VERSION 5.8 ;
BUSBITCHARS "[]" ;
DIVIDERCHAR "/" ;
UNITS
    DATABASE MICRONS 1000 ;
END UNITS

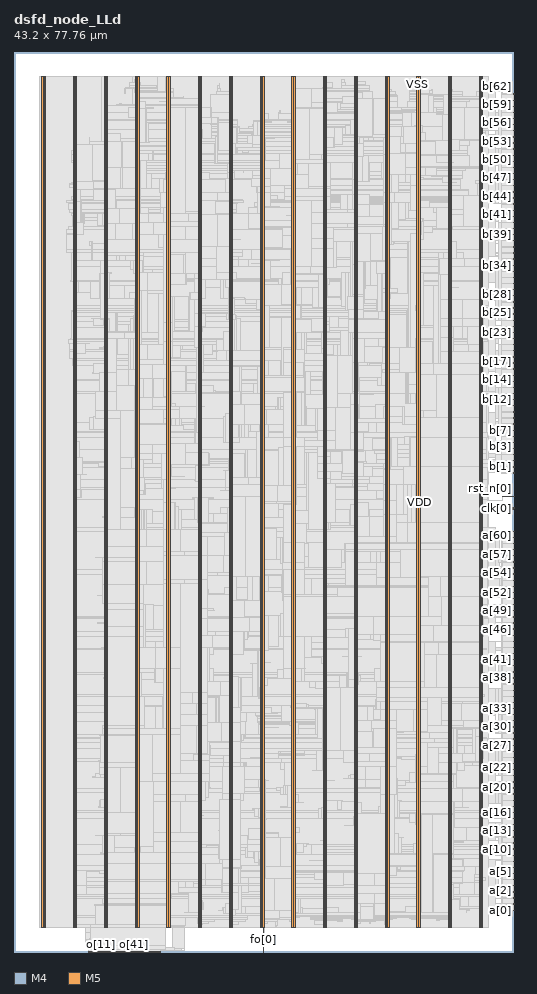
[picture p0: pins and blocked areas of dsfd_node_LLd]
MACRO dsfd_node_LLd
  FOREIGN dsfd_node_LLd 0 0 ;
  CLASS BLOCK ;
  SIZE 43.2 BY 77.76 ;
  PIN a[0]
    DIRECTION INPUT ;
    USE SIGNAL ;
    PORT
      LAYER M4 ;
        RECT  43.116 3.6 43.2 3.624 ;
    END
  END a[0]
  PIN a[10]
    DIRECTION INPUT ;
    USE SIGNAL ;
    PORT
      LAYER M4 ;
        RECT  43.116 8.88 43.2 8.904 ;
    END
  END a[10]
  PIN a[11]
    DIRECTION INPUT ;
    USE SIGNAL ;
    PORT
      LAYER M4 ;
        RECT  43.116 9.408 43.2 9.432 ;
    END
  END a[11]
  PIN a[12]
    DIRECTION INPUT ;
    USE SIGNAL ;
    PORT
      LAYER M4 ;
        RECT  43.116 9.936 43.2 9.96 ;
    END
  END a[12]
  PIN a[13]
    DIRECTION INPUT ;
    USE SIGNAL ;
    PORT
      LAYER M4 ;
        RECT  43.116 10.464 43.2 10.488 ;
    END
  END a[13]
  PIN a[14]
    DIRECTION INPUT ;
    USE SIGNAL ;
    PORT
      LAYER M4 ;
        RECT  43.116 10.992 43.2 11.016 ;
    END
  END a[14]
  PIN a[15]
    DIRECTION INPUT ;
    USE SIGNAL ;
    PORT
      LAYER M4 ;
        RECT  43.116 11.52 43.2 11.544 ;
    END
  END a[15]
  PIN a[16]
    DIRECTION INPUT ;
    USE SIGNAL ;
    PORT
      LAYER M4 ;
        RECT  43.116 12.048 43.2 12.072 ;
    END
  END a[16]
  PIN a[17]
    DIRECTION INPUT ;
    USE SIGNAL ;
    PORT
      LAYER M4 ;
        RECT  43.116 12.576 43.2 12.6 ;
    END
  END a[17]
  PIN a[18]
    DIRECTION INPUT ;
    USE SIGNAL ;
    PORT
      LAYER M4 ;
        RECT  43.116 13.104 43.2 13.128 ;
    END
  END a[18]
  PIN a[19]
    DIRECTION INPUT ;
    USE SIGNAL ;
    PORT
      LAYER M4 ;
        RECT  43.116 13.632 43.2 13.656 ;
    END
  END a[19]
  PIN a[1]
    DIRECTION INPUT ;
    USE SIGNAL ;
    PORT
      LAYER M4 ;
        RECT  43.116 4.128 43.2 4.152 ;
    END
  END a[1]
  PIN a[20]
    DIRECTION INPUT ;
    USE SIGNAL ;
    PORT
      LAYER M4 ;
        RECT  43.116 14.16 43.2 14.184 ;
    END
  END a[20]
  PIN a[21]
    DIRECTION INPUT ;
    USE SIGNAL ;
    PORT
      LAYER M4 ;
        RECT  43.116 14.688 43.2 14.712 ;
    END
  END a[21]
  PIN a[22]
    DIRECTION INPUT ;
    USE SIGNAL ;
    PORT
      LAYER M4 ;
        RECT  43.116 15.216 43.2 15.24 ;
    END
  END a[22]
  PIN a[23]
    DIRECTION INPUT ;
    USE SIGNAL ;
    PORT
      LAYER M4 ;
        RECT  43.116 15.744 43.2 15.768 ;
    END
  END a[23]
  PIN a[24]
    DIRECTION INPUT ;
    USE SIGNAL ;
    PORT
      LAYER M4 ;
        RECT  43.116 16.272 43.2 16.296 ;
    END
  END a[24]
  PIN a[25]
    DIRECTION INPUT ;
    USE SIGNAL ;
    PORT
      LAYER M4 ;
        RECT  43.116 16.8 43.2 16.824 ;
    END
  END a[25]
  PIN a[26]
    DIRECTION INPUT ;
    USE SIGNAL ;
    PORT
      LAYER M4 ;
        RECT  43.116 17.328 43.2 17.352 ;
    END
  END a[26]
  PIN a[27]
    DIRECTION INPUT ;
    USE SIGNAL ;
    PORT
      LAYER M4 ;
        RECT  43.116 17.856 43.2 17.88 ;
    END
  END a[27]
  PIN a[28]
    DIRECTION INPUT ;
    USE SIGNAL ;
    PORT
      LAYER M4 ;
        RECT  43.116 18.384 43.2 18.408 ;
    END
  END a[28]
  PIN a[29]
    DIRECTION INPUT ;
    USE SIGNAL ;
    PORT
      LAYER M4 ;
        RECT  43.116 18.912 43.2 18.936 ;
    END
  END a[29]
  PIN a[2]
    DIRECTION INPUT ;
    USE SIGNAL ;
    PORT
      LAYER M4 ;
        RECT  43.116 4.656 43.2 4.68 ;
    END
  END a[2]
  PIN a[30]
    DIRECTION INPUT ;
    USE SIGNAL ;
    PORT
      LAYER M4 ;
        RECT  43.116 19.44 43.2 19.464 ;
    END
  END a[30]
  PIN a[31]
    DIRECTION INPUT ;
    USE SIGNAL ;
    PORT
      LAYER M4 ;
        RECT  43.116 19.968 43.2 19.992 ;
    END
  END a[31]
  PIN a[32]
    DIRECTION INPUT ;
    USE SIGNAL ;
    PORT
      LAYER M4 ;
        RECT  43.116 20.496 43.2 20.52 ;
    END
  END a[32]
  PIN a[33]
    DIRECTION INPUT ;
    USE SIGNAL ;
    PORT
      LAYER M4 ;
        RECT  43.116 21.024 43.2 21.048 ;
    END
  END a[33]
  PIN a[34]
    DIRECTION INPUT ;
    USE SIGNAL ;
    PORT
      LAYER M4 ;
        RECT  43.116 21.552 43.2 21.576 ;
    END
  END a[34]
  PIN a[35]
    DIRECTION INPUT ;
    USE SIGNAL ;
    PORT
      LAYER M4 ;
        RECT  43.116 22.08 43.2 22.104 ;
    END
  END a[35]
  PIN a[36]
    DIRECTION INPUT ;
    USE SIGNAL ;
    PORT
      LAYER M4 ;
        RECT  43.116 22.608 43.2 22.632 ;
    END
  END a[36]
  PIN a[37]
    DIRECTION INPUT ;
    USE SIGNAL ;
    PORT
      LAYER M4 ;
        RECT  43.116 23.136 43.2 23.16 ;
    END
  END a[37]
  PIN a[38]
    DIRECTION INPUT ;
    USE SIGNAL ;
    PORT
      LAYER M4 ;
        RECT  43.116 23.664 43.2 23.688 ;
    END
  END a[38]
  PIN a[39]
    DIRECTION INPUT ;
    USE SIGNAL ;
    PORT
      LAYER M4 ;
        RECT  43.116 24.192 43.2 24.216 ;
    END
  END a[39]
  PIN a[3]
    DIRECTION INPUT ;
    USE SIGNAL ;
    PORT
      LAYER M4 ;
        RECT  43.116 5.184 43.2 5.208 ;
    END
  END a[3]
  PIN a[40]
    DIRECTION INPUT ;
    USE SIGNAL ;
    PORT
      LAYER M4 ;
        RECT  43.116 24.72 43.2 24.744 ;
    END
  END a[40]
  PIN a[41]
    DIRECTION INPUT ;
    USE SIGNAL ;
    PORT
      LAYER M4 ;
        RECT  43.116 25.248 43.2 25.272 ;
    END
  END a[41]
  PIN a[42]
    DIRECTION INPUT ;
    USE SIGNAL ;
    PORT
      LAYER M4 ;
        RECT  43.116 25.776 43.2 25.8 ;
    END
  END a[42]
  PIN a[43]
    DIRECTION INPUT ;
    USE SIGNAL ;
    PORT
      LAYER M4 ;
        RECT  43.116 26.304 43.2 26.328 ;
    END
  END a[43]
  PIN a[44]
    DIRECTION INPUT ;
    USE SIGNAL ;
    PORT
      LAYER M4 ;
        RECT  43.116 26.832 43.2 26.856 ;
    END
  END a[44]
  PIN a[45]
    DIRECTION INPUT ;
    USE SIGNAL ;
    PORT
      LAYER M4 ;
        RECT  43.116 27.36 43.2 27.384 ;
    END
  END a[45]
  PIN a[46]
    DIRECTION INPUT ;
    USE SIGNAL ;
    PORT
      LAYER M4 ;
        RECT  43.116 27.888 43.2 27.912 ;
    END
  END a[46]
  PIN a[47]
    DIRECTION INPUT ;
    USE SIGNAL ;
    PORT
      LAYER M4 ;
        RECT  43.116 28.416 43.2 28.44 ;
    END
  END a[47]
  PIN a[48]
    DIRECTION INPUT ;
    USE SIGNAL ;
    PORT
      LAYER M4 ;
        RECT  43.116 28.944 43.2 28.968 ;
    END
  END a[48]
  PIN a[49]
    DIRECTION INPUT ;
    USE SIGNAL ;
    PORT
      LAYER M4 ;
        RECT  43.116 29.472 43.2 29.496 ;
    END
  END a[49]
  PIN a[4]
    DIRECTION INPUT ;
    USE SIGNAL ;
    PORT
      LAYER M4 ;
        RECT  43.116 5.712 43.2 5.736 ;
    END
  END a[4]
  PIN a[50]
    DIRECTION INPUT ;
    USE SIGNAL ;
    PORT
      LAYER M4 ;
        RECT  43.116 30 43.2 30.024 ;
    END
  END a[50]
  PIN a[51]
    DIRECTION INPUT ;
    USE SIGNAL ;
    PORT
      LAYER M4 ;
        RECT  43.116 30.528 43.2 30.552 ;
    END
  END a[51]
  PIN a[52]
    DIRECTION INPUT ;
    USE SIGNAL ;
    PORT
      LAYER M4 ;
        RECT  43.116 31.056 43.2 31.08 ;
    END
  END a[52]
  PIN a[53]
    DIRECTION INPUT ;
    USE SIGNAL ;
    PORT
      LAYER M4 ;
        RECT  43.116 31.584 43.2 31.608 ;
    END
  END a[53]
  PIN a[54]
    DIRECTION INPUT ;
    USE SIGNAL ;
    PORT
      LAYER M4 ;
        RECT  43.116 32.112 43.2 32.136 ;
    END
  END a[54]
  PIN a[55]
    DIRECTION INPUT ;
    USE SIGNAL ;
    PORT
      LAYER M4 ;
        RECT  43.116 32.64 43.2 32.664 ;
    END
  END a[55]
  PIN a[56]
    DIRECTION INPUT ;
    USE SIGNAL ;
    PORT
      LAYER M4 ;
        RECT  43.116 33.168 43.2 33.192 ;
    END
  END a[56]
  PIN a[57]
    DIRECTION INPUT ;
    USE SIGNAL ;
    PORT
      LAYER M4 ;
        RECT  43.116 33.696 43.2 33.72 ;
    END
  END a[57]
  PIN a[58]
    DIRECTION INPUT ;
    USE SIGNAL ;
    PORT
      LAYER M4 ;
        RECT  43.116 34.224 43.2 34.248 ;
    END
  END a[58]
  PIN a[59]
    DIRECTION INPUT ;
    USE SIGNAL ;
    PORT
      LAYER M4 ;
        RECT  43.116 34.752 43.2 34.776 ;
    END
  END a[59]
  PIN a[5]
    DIRECTION INPUT ;
    USE SIGNAL ;
    PORT
      LAYER M4 ;
        RECT  43.116 6.24 43.2 6.264 ;
    END
  END a[5]
  PIN a[60]
    DIRECTION INPUT ;
    USE SIGNAL ;
    PORT
      LAYER M4 ;
        RECT  43.116 35.28 43.2 35.304 ;
    END
  END a[60]
  PIN a[61]
    DIRECTION INPUT ;
    USE SIGNAL ;
    PORT
      LAYER M4 ;
        RECT  43.116 35.808 43.2 35.832 ;
    END
  END a[61]
  PIN a[62]
    DIRECTION INPUT ;
    USE SIGNAL ;
    PORT
      LAYER M4 ;
        RECT  43.116 36.336 43.2 36.36 ;
    END
  END a[62]
  PIN a[6]
    DIRECTION INPUT ;
    USE SIGNAL ;
    PORT
      LAYER M4 ;
        RECT  43.116 6.768 43.2 6.792 ;
    END
  END a[6]
  PIN a[7]
    DIRECTION INPUT ;
    USE SIGNAL ;
    PORT
      LAYER M4 ;
        RECT  43.116 7.296 43.2 7.32 ;
    END
  END a[7]
  PIN a[8]
    DIRECTION INPUT ;
    USE SIGNAL ;
    PORT
      LAYER M4 ;
        RECT  43.116 7.824 43.2 7.848 ;
    END
  END a[8]
  PIN a[9]
    DIRECTION INPUT ;
    USE SIGNAL ;
    PORT
      LAYER M4 ;
        RECT  43.116 8.352 43.2 8.376 ;
    END
  END a[9]
  PIN b[0]
    DIRECTION INPUT ;
    USE SIGNAL ;
    PORT
      LAYER M4 ;
        RECT  43.116 41.376 43.2 41.4 ;
    END
  END b[0]
  PIN b[10]
    DIRECTION INPUT ;
    USE SIGNAL ;
    PORT
      LAYER M4 ;
        RECT  43.116 46.656 43.2 46.68 ;
    END
  END b[10]
  PIN b[11]
    DIRECTION INPUT ;
    USE SIGNAL ;
    PORT
      LAYER M4 ;
        RECT  43.116 47.184 43.2 47.208 ;
    END
  END b[11]
  PIN b[12]
    DIRECTION INPUT ;
    USE SIGNAL ;
    PORT
      LAYER M4 ;
        RECT  43.116 47.712 43.2 47.736 ;
    END
  END b[12]
  PIN b[13]
    DIRECTION INPUT ;
    USE SIGNAL ;
    PORT
      LAYER M4 ;
        RECT  43.116 48.24 43.2 48.264 ;
    END
  END b[13]
  PIN b[14]
    DIRECTION INPUT ;
    USE SIGNAL ;
    PORT
      LAYER M4 ;
        RECT  43.116 48.768 43.2 48.792 ;
    END
  END b[14]
  PIN b[15]
    DIRECTION INPUT ;
    USE SIGNAL ;
    PORT
      LAYER M4 ;
        RECT  43.116 49.296 43.2 49.32 ;
    END
  END b[15]
  PIN b[16]
    DIRECTION INPUT ;
    USE SIGNAL ;
    PORT
      LAYER M4 ;
        RECT  43.116 49.824 43.2 49.848 ;
    END
  END b[16]
  PIN b[17]
    DIRECTION INPUT ;
    USE SIGNAL ;
    PORT
      LAYER M4 ;
        RECT  43.116 50.352 43.2 50.376 ;
    END
  END b[17]
  PIN b[18]
    DIRECTION INPUT ;
    USE SIGNAL ;
    PORT
      LAYER M4 ;
        RECT  43.116 50.88 43.2 50.904 ;
    END
  END b[18]
  PIN b[19]
    DIRECTION INPUT ;
    USE SIGNAL ;
    PORT
      LAYER M4 ;
        RECT  43.116 51.408 43.2 51.432 ;
    END
  END b[19]
  PIN b[1]
    DIRECTION INPUT ;
    USE SIGNAL ;
    PORT
      LAYER M4 ;
        RECT  43.116 41.904 43.2 41.928 ;
    END
  END b[1]
  PIN b[20]
    DIRECTION INPUT ;
    USE SIGNAL ;
    PORT
      LAYER M4 ;
        RECT  43.116 51.936 43.2 51.96 ;
    END
  END b[20]
  PIN b[21]
    DIRECTION INPUT ;
    USE SIGNAL ;
    PORT
      LAYER M4 ;
        RECT  43.116 52.464 43.2 52.488 ;
    END
  END b[21]
  PIN b[22]
    DIRECTION INPUT ;
    USE SIGNAL ;
    PORT
      LAYER M4 ;
        RECT  43.116 52.992 43.2 53.016 ;
    END
  END b[22]
  PIN b[23]
    DIRECTION INPUT ;
    USE SIGNAL ;
    PORT
      LAYER M4 ;
        RECT  43.116 53.52 43.2 53.544 ;
    END
  END b[23]
  PIN b[24]
    DIRECTION INPUT ;
    USE SIGNAL ;
    PORT
      LAYER M4 ;
        RECT  43.116 54.048 43.2 54.072 ;
    END
  END b[24]
  PIN b[25]
    DIRECTION INPUT ;
    USE SIGNAL ;
    PORT
      LAYER M4 ;
        RECT  43.116 54.576 43.2 54.6 ;
    END
  END b[25]
  PIN b[26]
    DIRECTION INPUT ;
    USE SIGNAL ;
    PORT
      LAYER M4 ;
        RECT  43.116 55.104 43.2 55.128 ;
    END
  END b[26]
  PIN b[27]
    DIRECTION INPUT ;
    USE SIGNAL ;
    PORT
      LAYER M4 ;
        RECT  43.116 55.632 43.2 55.656 ;
    END
  END b[27]
  PIN b[28]
    DIRECTION INPUT ;
    USE SIGNAL ;
    PORT
      LAYER M4 ;
        RECT  43.116 56.16 43.2 56.184 ;
    END
  END b[28]
  PIN b[29]
    DIRECTION INPUT ;
    USE SIGNAL ;
    PORT
      LAYER M4 ;
        RECT  43.116 56.688 43.2 56.712 ;
    END
  END b[29]
  PIN b[2]
    DIRECTION INPUT ;
    USE SIGNAL ;
    PORT
      LAYER M4 ;
        RECT  43.116 42.432 43.2 42.456 ;
    END
  END b[2]
  PIN b[30]
    DIRECTION INPUT ;
    USE SIGNAL ;
    PORT
      LAYER M4 ;
        RECT  43.116 57.216 43.2 57.24 ;
    END
  END b[30]
  PIN b[31]
    DIRECTION INPUT ;
    USE SIGNAL ;
    PORT
      LAYER M4 ;
        RECT  43.116 57.744 43.2 57.768 ;
    END
  END b[31]
  PIN b[32]
    DIRECTION INPUT ;
    USE SIGNAL ;
    PORT
      LAYER M4 ;
        RECT  43.116 58.272 43.2 58.296 ;
    END
  END b[32]
  PIN b[33]
    DIRECTION INPUT ;
    USE SIGNAL ;
    PORT
      LAYER M4 ;
        RECT  43.116 58.8 43.2 58.824 ;
    END
  END b[33]
  PIN b[34]
    DIRECTION INPUT ;
    USE SIGNAL ;
    PORT
      LAYER M4 ;
        RECT  43.116 59.328 43.2 59.352 ;
    END
  END b[34]
  PIN b[35]
    DIRECTION INPUT ;
    USE SIGNAL ;
    PORT
      LAYER M4 ;
        RECT  43.116 59.856 43.2 59.88 ;
    END
  END b[35]
  PIN b[36]
    DIRECTION INPUT ;
    USE SIGNAL ;
    PORT
      LAYER M4 ;
        RECT  43.116 60.384 43.2 60.408 ;
    END
  END b[36]
  PIN b[37]
    DIRECTION INPUT ;
    USE SIGNAL ;
    PORT
      LAYER M4 ;
        RECT  43.116 60.912 43.2 60.936 ;
    END
  END b[37]
  PIN b[38]
    DIRECTION INPUT ;
    USE SIGNAL ;
    PORT
      LAYER M4 ;
        RECT  43.116 61.44 43.2 61.464 ;
    END
  END b[38]
  PIN b[39]
    DIRECTION INPUT ;
    USE SIGNAL ;
    PORT
      LAYER M4 ;
        RECT  43.116 61.968 43.2 61.992 ;
    END
  END b[39]
  PIN b[3]
    DIRECTION INPUT ;
    USE SIGNAL ;
    PORT
      LAYER M4 ;
        RECT  43.116 42.96 43.2 42.984 ;
    END
  END b[3]
  PIN b[40]
    DIRECTION INPUT ;
    USE SIGNAL ;
    PORT
      LAYER M4 ;
        RECT  43.116 62.496 43.2 62.52 ;
    END
  END b[40]
  PIN b[41]
    DIRECTION INPUT ;
    USE SIGNAL ;
    PORT
      LAYER M4 ;
        RECT  43.116 63.024 43.2 63.048 ;
    END
  END b[41]
  PIN b[42]
    DIRECTION INPUT ;
    USE SIGNAL ;
    PORT
      LAYER M4 ;
        RECT  43.116 63.552 43.2 63.576 ;
    END
  END b[42]
  PIN b[43]
    DIRECTION INPUT ;
    USE SIGNAL ;
    PORT
      LAYER M4 ;
        RECT  43.116 64.08 43.2 64.104 ;
    END
  END b[43]
  PIN b[44]
    DIRECTION INPUT ;
    USE SIGNAL ;
    PORT
      LAYER M4 ;
        RECT  43.116 64.608 43.2 64.632 ;
    END
  END b[44]
  PIN b[45]
    DIRECTION INPUT ;
    USE SIGNAL ;
    PORT
      LAYER M4 ;
        RECT  43.116 65.136 43.2 65.16 ;
    END
  END b[45]
  PIN b[46]
    DIRECTION INPUT ;
    USE SIGNAL ;
    PORT
      LAYER M4 ;
        RECT  43.116 65.664 43.2 65.688 ;
    END
  END b[46]
  PIN b[47]
    DIRECTION INPUT ;
    USE SIGNAL ;
    PORT
      LAYER M4 ;
        RECT  43.116 66.192 43.2 66.216 ;
    END
  END b[47]
  PIN b[48]
    DIRECTION INPUT ;
    USE SIGNAL ;
    PORT
      LAYER M4 ;
        RECT  43.116 66.72 43.2 66.744 ;
    END
  END b[48]
  PIN b[49]
    DIRECTION INPUT ;
    USE SIGNAL ;
    PORT
      LAYER M4 ;
        RECT  43.116 67.248 43.2 67.272 ;
    END
  END b[49]
  PIN b[4]
    DIRECTION INPUT ;
    USE SIGNAL ;
    PORT
      LAYER M4 ;
        RECT  43.116 43.488 43.2 43.512 ;
    END
  END b[4]
  PIN b[50]
    DIRECTION INPUT ;
    USE SIGNAL ;
    PORT
      LAYER M4 ;
        RECT  43.116 67.776 43.2 67.8 ;
    END
  END b[50]
  PIN b[51]
    DIRECTION INPUT ;
    USE SIGNAL ;
    PORT
      LAYER M4 ;
        RECT  43.116 68.304 43.2 68.328 ;
    END
  END b[51]
  PIN b[52]
    DIRECTION INPUT ;
    USE SIGNAL ;
    PORT
      LAYER M4 ;
        RECT  43.116 68.832 43.2 68.856 ;
    END
  END b[52]
  PIN b[53]
    DIRECTION INPUT ;
    USE SIGNAL ;
    PORT
      LAYER M4 ;
        RECT  43.116 69.36 43.2 69.384 ;
    END
  END b[53]
  PIN b[54]
    DIRECTION INPUT ;
    USE SIGNAL ;
    PORT
      LAYER M4 ;
        RECT  43.116 69.888 43.2 69.912 ;
    END
  END b[54]
  PIN b[55]
    DIRECTION INPUT ;
    USE SIGNAL ;
    PORT
      LAYER M4 ;
        RECT  43.116 70.416 43.2 70.44 ;
    END
  END b[55]
  PIN b[56]
    DIRECTION INPUT ;
    USE SIGNAL ;
    PORT
      LAYER M4 ;
        RECT  43.116 70.944 43.2 70.968 ;
    END
  END b[56]
  PIN b[57]
    DIRECTION INPUT ;
    USE SIGNAL ;
    PORT
      LAYER M4 ;
        RECT  43.116 71.472 43.2 71.496 ;
    END
  END b[57]
  PIN b[58]
    DIRECTION INPUT ;
    USE SIGNAL ;
    PORT
      LAYER M4 ;
        RECT  43.116 72 43.2 72.024 ;
    END
  END b[58]
  PIN b[59]
    DIRECTION INPUT ;
    USE SIGNAL ;
    PORT
      LAYER M4 ;
        RECT  43.116 72.528 43.2 72.552 ;
    END
  END b[59]
  PIN b[5]
    DIRECTION INPUT ;
    USE SIGNAL ;
    PORT
      LAYER M4 ;
        RECT  43.116 44.016 43.2 44.04 ;
    END
  END b[5]
  PIN b[60]
    DIRECTION INPUT ;
    USE SIGNAL ;
    PORT
      LAYER M4 ;
        RECT  43.116 73.056 43.2 73.08 ;
    END
  END b[60]
  PIN b[61]
    DIRECTION INPUT ;
    USE SIGNAL ;
    PORT
      LAYER M4 ;
        RECT  43.116 73.584 43.2 73.608 ;
    END
  END b[61]
  PIN b[62]
    DIRECTION INPUT ;
    USE SIGNAL ;
    PORT
      LAYER M4 ;
        RECT  43.116 74.112 43.2 74.136 ;
    END
  END b[62]
  PIN b[6]
    DIRECTION INPUT ;
    USE SIGNAL ;
    PORT
      LAYER M4 ;
        RECT  43.116 44.544 43.2 44.568 ;
    END
  END b[6]
  PIN b[7]
    DIRECTION INPUT ;
    USE SIGNAL ;
    PORT
      LAYER M4 ;
        RECT  43.116 45.072 43.2 45.096 ;
    END
  END b[7]
  PIN b[8]
    DIRECTION INPUT ;
    USE SIGNAL ;
    PORT
      LAYER M4 ;
        RECT  43.116 45.6 43.2 45.624 ;
    END
  END b[8]
  PIN b[9]
    DIRECTION INPUT ;
    USE SIGNAL ;
    PORT
      LAYER M4 ;
        RECT  43.116 46.128 43.2 46.152 ;
    END
  END b[9]
  PIN clk[0]
    DIRECTION INPUT ;
    USE SIGNAL ;
    PORT
      LAYER M4 ;
        RECT  43.116 38.352 43.2 38.376 ;
    END
    PORT
      LAYER M4 ;
        RECT  43.081 38.208 43.121 38.376 ;
    END
    PORT
      LAYER M4 ;
        RECT  43.121 38.352 43.164 38.376 ;
    END
  END clk[0]
  PIN fo[0]
    DIRECTION OUTPUT ;
    USE SIGNAL ;
    PORT
      LAYER M5 ;
        RECT  21.552 0 21.576 0.084 ;
    END
    PORT
      LAYER M5 ;
        RECT  21.552 0.016 21.576 2.137 ;
    END
  END fo[0]
  PIN o[0]
    DIRECTION OUTPUT ;
    USE SIGNAL ;
    PORT
      LAYER M5 ;
        RECT  6.432 0 6.456 0.084 ;
    END
  END o[0]
  PIN o[10]
    DIRECTION OUTPUT ;
    USE SIGNAL ;
    PORT
      LAYER M5 ;
        RECT  7.392 0 7.416 0.084 ;
    END
  END o[10]
  PIN o[11]
    DIRECTION OUTPUT ;
    USE SIGNAL ;
    PORT
      LAYER M5 ;
        RECT  7.488 0 7.512 0.084 ;
    END
  END o[11]
  PIN o[12]
    DIRECTION OUTPUT ;
    USE SIGNAL ;
    PORT
      LAYER M5 ;
        RECT  7.584 0 7.608 0.084 ;
    END
  END o[12]
  PIN o[13]
    DIRECTION OUTPUT ;
    USE SIGNAL ;
    PORT
      LAYER M5 ;
        RECT  7.68 0 7.704 0.084 ;
    END
  END o[13]
  PIN o[14]
    DIRECTION OUTPUT ;
    USE SIGNAL ;
    PORT
      LAYER M5 ;
        RECT  7.776 0 7.8 0.084 ;
    END
  END o[14]
  PIN o[15]
    DIRECTION OUTPUT ;
    USE SIGNAL ;
    PORT
      LAYER M5 ;
        RECT  7.872 0 7.896 0.084 ;
    END
  END o[15]
  PIN o[16]
    DIRECTION OUTPUT ;
    USE SIGNAL ;
    PORT
      LAYER M5 ;
        RECT  7.968 0 7.992 0.084 ;
    END
  END o[16]
  PIN o[17]
    DIRECTION OUTPUT ;
    USE SIGNAL ;
    PORT
      LAYER M5 ;
        RECT  8.064 0 8.088 0.084 ;
    END
  END o[17]
  PIN o[18]
    DIRECTION OUTPUT ;
    USE SIGNAL ;
    PORT
      LAYER M5 ;
        RECT  8.16 0 8.184 0.084 ;
    END
  END o[18]
  PIN o[19]
    DIRECTION OUTPUT ;
    USE SIGNAL ;
    PORT
      LAYER M5 ;
        RECT  8.256 0 8.28 0.084 ;
    END
  END o[19]
  PIN o[1]
    DIRECTION OUTPUT ;
    USE SIGNAL ;
    PORT
      LAYER M5 ;
        RECT  6.528 0 6.552 0.084 ;
    END
  END o[1]
  PIN o[20]
    DIRECTION OUTPUT ;
    USE SIGNAL ;
    PORT
      LAYER M5 ;
        RECT  8.352 0 8.376 0.084 ;
    END
  END o[20]
  PIN o[21]
    DIRECTION OUTPUT ;
    USE SIGNAL ;
    PORT
      LAYER M5 ;
        RECT  8.448 0 8.472 0.084 ;
    END
  END o[21]
  PIN o[22]
    DIRECTION OUTPUT ;
    USE SIGNAL ;
    PORT
      LAYER M5 ;
        RECT  8.544 0 8.568 0.084 ;
    END
  END o[22]
  PIN o[23]
    DIRECTION OUTPUT ;
    USE SIGNAL ;
    PORT
      LAYER M5 ;
        RECT  8.64 0 8.664 0.084 ;
    END
  END o[23]
  PIN o[24]
    DIRECTION OUTPUT ;
    USE SIGNAL ;
    PORT
      LAYER M5 ;
        RECT  8.736 0 8.76 0.084 ;
    END
  END o[24]
  PIN o[25]
    DIRECTION OUTPUT ;
    USE SIGNAL ;
    PORT
      LAYER M5 ;
        RECT  8.832 0 8.856 0.084 ;
    END
  END o[25]
  PIN o[26]
    DIRECTION OUTPUT ;
    USE SIGNAL ;
    PORT
      LAYER M5 ;
        RECT  8.928 0 8.952 0.084 ;
    END
  END o[26]
  PIN o[27]
    DIRECTION OUTPUT ;
    USE SIGNAL ;
    PORT
      LAYER M5 ;
        RECT  9.024 0 9.048 0.084 ;
    END
  END o[27]
  PIN o[28]
    DIRECTION OUTPUT ;
    USE SIGNAL ;
    PORT
      LAYER M5 ;
        RECT  9.12 0 9.144 0.084 ;
    END
  END o[28]
  PIN o[29]
    DIRECTION OUTPUT ;
    USE SIGNAL ;
    PORT
      LAYER M5 ;
        RECT  9.216 0 9.24 0.084 ;
    END
  END o[29]
  PIN o[2]
    DIRECTION OUTPUT ;
    USE SIGNAL ;
    PORT
      LAYER M5 ;
        RECT  6.624 0 6.648 0.084 ;
    END
  END o[2]
  PIN o[30]
    DIRECTION OUTPUT ;
    USE SIGNAL ;
    PORT
      LAYER M5 ;
        RECT  9.312 0 9.336 0.084 ;
    END
  END o[30]
  PIN o[31]
    DIRECTION OUTPUT ;
    USE SIGNAL ;
    PORT
      LAYER M5 ;
        RECT  9.408 0 9.432 0.084 ;
    END
  END o[31]
  PIN o[32]
    DIRECTION OUTPUT ;
    USE SIGNAL ;
    PORT
      LAYER M5 ;
        RECT  9.504 0 9.528 0.084 ;
    END
  END o[32]
  PIN o[33]
    DIRECTION OUTPUT ;
    USE SIGNAL ;
    PORT
      LAYER M5 ;
        RECT  9.6 0 9.624 0.084 ;
    END
  END o[33]
  PIN o[34]
    DIRECTION OUTPUT ;
    USE SIGNAL ;
    PORT
      LAYER M5 ;
        RECT  9.696 0 9.72 0.084 ;
    END
  END o[34]
  PIN o[35]
    DIRECTION OUTPUT ;
    USE SIGNAL ;
    PORT
      LAYER M5 ;
        RECT  9.792 0 9.816 0.084 ;
    END
  END o[35]
  PIN o[36]
    DIRECTION OUTPUT ;
    USE SIGNAL ;
    PORT
      LAYER M5 ;
        RECT  9.888 0 9.912 0.084 ;
    END
  END o[36]
  PIN o[37]
    DIRECTION OUTPUT ;
    USE SIGNAL ;
    PORT
      LAYER M5 ;
        RECT  9.984 0 10.008 0.084 ;
    END
  END o[37]
  PIN o[38]
    DIRECTION OUTPUT ;
    USE SIGNAL ;
    PORT
      LAYER M5 ;
        RECT  10.08 0 10.104 0.084 ;
    END
  END o[38]
  PIN o[39]
    DIRECTION OUTPUT ;
    USE SIGNAL ;
    PORT
      LAYER M5 ;
        RECT  10.176 0 10.2 0.084 ;
    END
  END o[39]
  PIN o[3]
    DIRECTION OUTPUT ;
    USE SIGNAL ;
    PORT
      LAYER M5 ;
        RECT  6.72 0 6.744 0.084 ;
    END
  END o[3]
  PIN o[40]
    DIRECTION OUTPUT ;
    USE SIGNAL ;
    PORT
      LAYER M5 ;
        RECT  10.272 0 10.296 0.084 ;
    END
  END o[40]
  PIN o[41]
    DIRECTION OUTPUT ;
    USE SIGNAL ;
    PORT
      LAYER M5 ;
        RECT  10.368 0 10.392 0.084 ;
    END
  END o[41]
  PIN o[42]
    DIRECTION OUTPUT ;
    USE SIGNAL ;
    PORT
      LAYER M5 ;
        RECT  10.464 0 10.488 0.084 ;
    END
  END o[42]
  PIN o[43]
    DIRECTION OUTPUT ;
    USE SIGNAL ;
    PORT
      LAYER M5 ;
        RECT  10.56 0 10.584 0.084 ;
    END
  END o[43]
  PIN o[44]
    DIRECTION OUTPUT ;
    USE SIGNAL ;
    PORT
      LAYER M5 ;
        RECT  10.656 0 10.68 0.084 ;
    END
  END o[44]
  PIN o[45]
    DIRECTION OUTPUT ;
    USE SIGNAL ;
    PORT
      LAYER M5 ;
        RECT  10.752 0 10.776 0.084 ;
    END
  END o[45]
  PIN o[46]
    DIRECTION OUTPUT ;
    USE SIGNAL ;
    PORT
      LAYER M5 ;
        RECT  10.848 0 10.872 0.084 ;
    END
  END o[46]
  PIN o[47]
    DIRECTION OUTPUT ;
    USE SIGNAL ;
    PORT
      LAYER M5 ;
        RECT  10.944 0 10.968 0.084 ;
    END
  END o[47]
  PIN o[48]
    DIRECTION OUTPUT ;
    USE SIGNAL ;
    PORT
      LAYER M5 ;
        RECT  11.04 0 11.064 0.084 ;
    END
  END o[48]
  PIN o[49]
    DIRECTION OUTPUT ;
    USE SIGNAL ;
    PORT
      LAYER M5 ;
        RECT  11.136 0 11.16 0.084 ;
    END
  END o[49]
  PIN o[4]
    DIRECTION OUTPUT ;
    USE SIGNAL ;
    PORT
      LAYER M5 ;
        RECT  6.816 0 6.84 0.084 ;
    END
  END o[4]
  PIN o[50]
    DIRECTION OUTPUT ;
    USE SIGNAL ;
    PORT
      LAYER M5 ;
        RECT  11.232 0 11.256 0.084 ;
    END
  END o[50]
  PIN o[51]
    DIRECTION OUTPUT ;
    USE SIGNAL ;
    PORT
      LAYER M5 ;
        RECT  11.328 0 11.352 0.084 ;
    END
  END o[51]
  PIN o[52]
    DIRECTION OUTPUT ;
    USE SIGNAL ;
    PORT
      LAYER M5 ;
        RECT  11.424 0 11.448 0.084 ;
    END
  END o[52]
  PIN o[53]
    DIRECTION OUTPUT ;
    USE SIGNAL ;
    PORT
      LAYER M5 ;
        RECT  11.52 0 11.544 0.084 ;
    END
  END o[53]
  PIN o[54]
    DIRECTION OUTPUT ;
    USE SIGNAL ;
    PORT
      LAYER M5 ;
        RECT  11.616 0 11.64 0.084 ;
    END
  END o[54]
  PIN o[55]
    DIRECTION OUTPUT ;
    USE SIGNAL ;
    PORT
      LAYER M5 ;
        RECT  11.712 0 11.736 0.084 ;
    END
  END o[55]
  PIN o[56]
    DIRECTION OUTPUT ;
    USE SIGNAL ;
    PORT
      LAYER M5 ;
        RECT  11.808 0 11.832 0.084 ;
    END
  END o[56]
  PIN o[57]
    DIRECTION OUTPUT ;
    USE SIGNAL ;
    PORT
      LAYER M5 ;
        RECT  11.904 0 11.928 0.084 ;
    END
  END o[57]
  PIN o[58]
    DIRECTION OUTPUT ;
    USE SIGNAL ;
    PORT
      LAYER M5 ;
        RECT  12 0 12.024 0.084 ;
    END
  END o[58]
  PIN o[59]
    DIRECTION OUTPUT ;
    USE SIGNAL ;
    PORT
      LAYER M5 ;
        RECT  12.096 0 12.12 0.084 ;
    END
  END o[59]
  PIN o[5]
    DIRECTION OUTPUT ;
    USE SIGNAL ;
    PORT
      LAYER M5 ;
        RECT  6.912 0 6.936 0.084 ;
    END
  END o[5]
  PIN o[60]
    DIRECTION OUTPUT ;
    USE SIGNAL ;
    PORT
      LAYER M5 ;
        RECT  12.192 0 12.216 0.084 ;
    END
  END o[60]
  PIN o[61]
    DIRECTION OUTPUT ;
    USE SIGNAL ;
    PORT
      LAYER M5 ;
        RECT  12.288 0 12.312 0.084 ;
    END
  END o[61]
  PIN o[62]
    DIRECTION OUTPUT ;
    USE SIGNAL ;
    PORT
      LAYER M5 ;
        RECT  12.384 0 12.408 0.084 ;
    END
  END o[62]
  PIN o[63]
    DIRECTION OUTPUT ;
    USE SIGNAL ;
    PORT
      LAYER M5 ;
        RECT  12.48 0 12.504 0.084 ;
    END
  END o[63]
  PIN o[64]
    DIRECTION OUTPUT ;
    USE SIGNAL ;
    PORT
      LAYER M5 ;
        RECT  12.576 0 12.6 0.084 ;
    END
  END o[64]
  PIN o[65]
    DIRECTION OUTPUT ;
    USE SIGNAL ;
    PORT
      LAYER M5 ;
        RECT  12.672 0 12.696 0.084 ;
    END
  END o[65]
  PIN o[6]
    DIRECTION OUTPUT ;
    USE SIGNAL ;
    PORT
      LAYER M5 ;
        RECT  7.008 0 7.032 0.084 ;
    END
  END o[6]
  PIN o[7]
    DIRECTION OUTPUT ;
    USE SIGNAL ;
    PORT
      LAYER M5 ;
        RECT  7.104 0 7.128 0.084 ;
    END
  END o[7]
  PIN o[8]
    DIRECTION OUTPUT ;
    USE SIGNAL ;
    PORT
      LAYER M5 ;
        RECT  7.2 0 7.224 0.084 ;
    END
  END o[8]
  PIN o[9]
    DIRECTION OUTPUT ;
    USE SIGNAL ;
    PORT
      LAYER M5 ;
        RECT  7.296 0 7.32 0.084 ;
    END
  END o[9]
  PIN rst_n[0]
    DIRECTION INPUT ;
    USE SIGNAL ;
    PORT
      LAYER M4 ;
        RECT  43.116 39.36 43.2 39.384 ;
    END
    PORT
      LAYER M4 ;
        RECT  42.181 39.36 43.164 39.384 ;
    END
  END rst_n[0]
  PIN VDD
    DIRECTION INOUT ;
    USE POWER ;
    PORT
      LAYER M5 ;
        RECT  40.392 2.151 40.512 75.609 ;
        RECT  37.692 2.151 37.812 75.609 ;
        RECT  34.992 2.151 35.112 75.609 ;
        RECT  32.292 2.151 32.412 75.609 ;
        RECT  29.592 2.151 29.712 75.609 ;
        RECT  26.892 2.151 27.012 75.609 ;
        RECT  24.192 2.151 24.312 75.609 ;
        RECT  21.492 2.151 21.612 75.609 ;
        RECT  18.792 2.151 18.912 75.609 ;
        RECT  16.092 2.151 16.212 75.609 ;
        RECT  13.392 2.151 13.512 75.609 ;
        RECT  10.692 2.151 10.812 75.609 ;
        RECT  7.992 2.151 8.112 75.609 ;
        RECT  5.292 2.151 5.412 75.609 ;
        RECT  2.592 2.151 2.712 75.609 ;
    END
  END VDD
  PIN VSS
    DIRECTION INOUT ;
    USE GROUND ;
    PORT
      LAYER M5 ;
        RECT  40.2 2.137 40.32 75.623 ;
        RECT  37.5 2.137 37.62 75.623 ;
        RECT  34.8 2.137 34.92 75.623 ;
        RECT  32.1 2.137 32.22 75.623 ;
        RECT  29.4 2.137 29.52 75.623 ;
        RECT  26.7 2.137 26.82 75.623 ;
        RECT  24 2.137 24.12 75.623 ;
        RECT  21.3 2.137 21.42 75.623 ;
        RECT  18.6 2.137 18.72 75.623 ;
        RECT  15.9 2.137 16.02 75.623 ;
        RECT  13.2 2.137 13.32 75.623 ;
        RECT  10.5 2.137 10.62 75.623 ;
        RECT  7.8 2.137 7.92 75.623 ;
        RECT  5.1 2.137 5.22 75.623 ;
        RECT  2.4 2.137 2.52 75.623 ;
    END
  END VSS
  # OT_OBS_CLOSED layer=M5 d_um=1.536 added=273
  OBS
    LAYER RVTN ;
     RECT  2.16 2.16 41.04 2.295 ;
     RECT  2.16 2.565 41.04 2.835 ;
     RECT  2.16 3.105 41.04 3.375 ;
     RECT  2.16 3.645 41.04 3.915 ;
     RECT  2.16 4.185 41.04 4.455 ;
     RECT  2.16 4.725 41.04 4.995 ;
     RECT  2.16 5.265 41.04 5.535 ;
     RECT  2.16 5.805 41.04 6.075 ;
     RECT  2.16 6.345 41.04 6.615 ;
     RECT  2.16 6.885 41.04 7.155 ;
     RECT  2.16 7.425 41.04 7.695 ;
     RECT  2.16 7.965 41.04 8.235 ;
     RECT  2.16 8.505 41.04 8.775 ;
     RECT  2.16 9.045 41.04 9.315 ;
     RECT  2.16 9.585 41.04 9.855 ;
     RECT  2.16 10.125 41.04 10.395 ;
     RECT  2.16 10.665 41.04 10.935 ;
     RECT  2.16 11.205 41.04 11.475 ;
     RECT  2.16 11.745 41.04 12.015 ;
     RECT  2.16 12.285 41.04 12.555 ;
     RECT  2.16 12.825 41.04 13.095 ;
     RECT  2.16 13.365 41.04 13.635 ;
     RECT  2.16 13.905 41.04 14.175 ;
     RECT  2.16 14.445 41.04 14.715 ;
     RECT  2.16 14.985 41.04 15.255 ;
     RECT  2.16 15.525 41.04 15.795 ;
     RECT  2.16 16.065 41.04 16.335 ;
     RECT  2.16 16.605 41.04 16.875 ;
     RECT  2.16 17.145 41.04 17.415 ;
     RECT  2.16 17.685 41.04 17.955 ;
     RECT  2.16 18.225 41.04 18.495 ;
     RECT  2.16 18.765 41.04 19.035 ;
     RECT  2.16 19.305 41.04 19.575 ;
     RECT  2.16 19.845 41.04 20.115 ;
     RECT  2.16 20.385 41.04 20.655 ;
     RECT  2.16 20.925 41.04 21.195 ;
     RECT  2.16 21.465 41.04 21.735 ;
     RECT  2.16 22.005 41.04 22.275 ;
     RECT  2.16 22.545 41.04 22.815 ;
     RECT  2.16 23.085 41.04 23.355 ;
     RECT  2.16 23.625 41.04 23.895 ;
     RECT  2.16 24.165 41.04 24.435 ;
     RECT  2.16 24.705 41.04 24.975 ;
     RECT  2.16 25.245 41.04 25.515 ;
     RECT  2.16 25.785 41.04 26.055 ;
     RECT  2.16 26.325 41.04 26.595 ;
     RECT  2.16 26.865 41.04 27.135 ;
     RECT  2.16 27.405 41.04 27.675 ;
     RECT  2.16 27.945 41.04 28.215 ;
     RECT  2.16 28.485 41.04 28.755 ;
     RECT  2.16 29.025 41.04 29.295 ;
     RECT  2.16 29.565 41.04 29.835 ;
     RECT  2.16 30.105 41.04 30.375 ;
     RECT  2.16 30.645 41.04 30.915 ;
     RECT  2.16 31.185 41.04 31.455 ;
     RECT  2.16 31.725 41.04 31.995 ;
     RECT  2.16 32.265 41.04 32.535 ;
     RECT  2.16 32.805 41.04 33.075 ;
     RECT  2.16 33.345 41.04 33.615 ;
     RECT  2.16 33.885 41.04 34.155 ;
     RECT  2.16 34.425 41.04 34.695 ;
     RECT  2.16 34.965 41.04 35.235 ;
     RECT  2.16 35.505 41.04 35.775 ;
     RECT  2.16 36.045 41.04 36.315 ;
     RECT  2.16 36.585 41.04 36.855 ;
     RECT  2.16 37.125 41.04 37.395 ;
     RECT  2.16 37.665 41.04 37.935 ;
     RECT  2.16 38.205 41.04 38.475 ;
     RECT  2.16 38.745 41.04 39.015 ;
     RECT  2.16 39.285 41.04 39.555 ;
     RECT  2.16 39.825 41.04 40.095 ;
     RECT  2.16 40.365 41.04 40.635 ;
     RECT  2.16 40.905 41.04 41.175 ;
     RECT  2.16 41.445 41.04 41.715 ;
     RECT  2.16 41.985 41.04 42.255 ;
     RECT  2.16 42.525 41.04 42.795 ;
     RECT  2.16 43.065 41.04 43.335 ;
     RECT  2.16 43.605 41.04 43.875 ;
     RECT  2.16 44.145 41.04 44.415 ;
     RECT  2.16 44.685 41.04 44.955 ;
     RECT  2.16 45.225 41.04 45.495 ;
     RECT  2.16 45.765 41.04 46.035 ;
     RECT  2.16 46.305 41.04 46.575 ;
     RECT  2.16 46.845 41.04 47.115 ;
     RECT  2.16 47.385 41.04 47.655 ;
     RECT  2.16 47.925 41.04 48.195 ;
     RECT  2.16 48.465 41.04 48.735 ;
     RECT  2.16 49.005 41.04 49.275 ;
     RECT  2.16 49.545 41.04 49.815 ;
     RECT  2.16 50.085 41.04 50.355 ;
     RECT  2.16 50.625 41.04 50.895 ;
     RECT  2.16 51.165 41.04 51.435 ;
     RECT  2.16 51.705 41.04 51.975 ;
     RECT  2.16 52.245 41.04 52.515 ;
     RECT  2.16 52.785 41.04 53.055 ;
     RECT  2.16 53.325 41.04 53.595 ;
     RECT  2.16 53.865 41.04 54.135 ;
     RECT  2.16 54.405 41.04 54.675 ;
     RECT  2.16 54.945 41.04 55.215 ;
     RECT  2.16 55.485 41.04 55.755 ;
     RECT  2.16 56.025 41.04 56.295 ;
     RECT  2.16 56.565 41.04 56.835 ;
     RECT  2.16 57.105 41.04 57.375 ;
     RECT  2.16 57.645 41.04 57.915 ;
     RECT  2.16 58.185 41.04 58.455 ;
     RECT  2.16 58.725 41.04 58.995 ;
     RECT  2.16 59.265 41.04 59.535 ;
     RECT  2.16 59.805 41.04 60.075 ;
     RECT  2.16 60.345 41.04 60.615 ;
     RECT  2.16 60.885 41.04 61.155 ;
     RECT  2.16 61.425 41.04 61.695 ;
     RECT  2.16 61.965 41.04 62.235 ;
     RECT  2.16 62.505 41.04 62.775 ;
     RECT  2.16 63.045 41.04 63.315 ;
     RECT  2.16 63.585 41.04 63.855 ;
     RECT  2.16 64.125 41.04 64.395 ;
     RECT  2.16 64.665 41.04 64.935 ;
     RECT  2.16 65.205 41.04 65.475 ;
     RECT  2.16 65.745 41.04 66.015 ;
     RECT  2.16 66.285 41.04 66.555 ;
     RECT  2.16 66.825 41.04 67.095 ;
     RECT  2.16 67.365 41.04 67.635 ;
     RECT  2.16 67.905 41.04 68.175 ;
     RECT  2.16 68.445 41.04 68.715 ;
     RECT  2.16 68.985 41.04 69.255 ;
     RECT  2.16 69.525 41.04 69.795 ;
     RECT  2.16 70.065 41.04 70.335 ;
     RECT  2.16 70.605 41.04 70.875 ;
     RECT  2.16 71.145 41.04 71.415 ;
     RECT  2.16 71.685 41.04 71.955 ;
     RECT  2.16 72.225 41.04 72.495 ;
     RECT  2.16 72.765 41.04 73.035 ;
     RECT  2.16 73.305 41.04 73.575 ;
     RECT  2.16 73.845 41.04 74.115 ;
     RECT  2.16 74.385 41.04 74.655 ;
     RECT  2.16 74.925 41.04 75.195 ;
     RECT  2.16 75.465 41.04 75.6 ;
    LAYER RVTP ;
     RECT  2.16 2.295 41.04 2.565 ;
     RECT  2.16 2.835 41.04 3.105 ;
     RECT  2.16 3.375 41.04 3.645 ;
     RECT  2.16 3.915 41.04 4.185 ;
     RECT  2.16 4.455 41.04 4.725 ;
     RECT  2.16 4.995 41.04 5.265 ;
     RECT  2.16 5.535 41.04 5.805 ;
     RECT  2.16 6.075 41.04 6.345 ;
     RECT  2.16 6.615 41.04 6.885 ;
     RECT  2.16 7.155 41.04 7.425 ;
     RECT  2.16 7.695 41.04 7.965 ;
     RECT  2.16 8.235 41.04 8.505 ;
     RECT  2.16 8.775 41.04 9.045 ;
     RECT  2.16 9.315 41.04 9.585 ;
     RECT  2.16 9.855 41.04 10.125 ;
     RECT  2.16 10.395 41.04 10.665 ;
     RECT  2.16 10.935 41.04 11.205 ;
     RECT  2.16 11.475 41.04 11.745 ;
     RECT  2.16 12.015 41.04 12.285 ;
     RECT  2.16 12.555 41.04 12.825 ;
     RECT  2.16 13.095 41.04 13.365 ;
     RECT  2.16 13.635 41.04 13.905 ;
     RECT  2.16 14.175 41.04 14.445 ;
     RECT  2.16 14.715 41.04 14.985 ;
     RECT  2.16 15.255 41.04 15.525 ;
     RECT  2.16 15.795 41.04 16.065 ;
     RECT  2.16 16.335 41.04 16.605 ;
     RECT  2.16 16.875 41.04 17.145 ;
     RECT  2.16 17.415 41.04 17.685 ;
     RECT  2.16 17.955 41.04 18.225 ;
     RECT  2.16 18.495 41.04 18.765 ;
     RECT  2.16 19.035 41.04 19.305 ;
     RECT  2.16 19.575 41.04 19.845 ;
     RECT  2.16 20.115 41.04 20.385 ;
     RECT  2.16 20.655 41.04 20.925 ;
     RECT  2.16 21.195 41.04 21.465 ;
     RECT  2.16 21.735 41.04 22.005 ;
     RECT  2.16 22.275 41.04 22.545 ;
     RECT  2.16 22.815 41.04 23.085 ;
     RECT  2.16 23.355 41.04 23.625 ;
     RECT  2.16 23.895 41.04 24.165 ;
     RECT  2.16 24.435 41.04 24.705 ;
     RECT  2.16 24.975 41.04 25.245 ;
     RECT  2.16 25.515 41.04 25.785 ;
     RECT  2.16 26.055 41.04 26.325 ;
     RECT  2.16 26.595 41.04 26.865 ;
     RECT  2.16 27.135 41.04 27.405 ;
     RECT  2.16 27.675 41.04 27.945 ;
     RECT  2.16 28.215 41.04 28.485 ;
     RECT  2.16 28.755 41.04 29.025 ;
     RECT  2.16 29.295 41.04 29.565 ;
     RECT  2.16 29.835 41.04 30.105 ;
     RECT  2.16 30.375 41.04 30.645 ;
     RECT  2.16 30.915 41.04 31.185 ;
     RECT  2.16 31.455 41.04 31.725 ;
     RECT  2.16 31.995 41.04 32.265 ;
     RECT  2.16 32.535 41.04 32.805 ;
     RECT  2.16 33.075 41.04 33.345 ;
     RECT  2.16 33.615 41.04 33.885 ;
     RECT  2.16 34.155 41.04 34.425 ;
     RECT  2.16 34.695 41.04 34.965 ;
     RECT  2.16 35.235 41.04 35.505 ;
     RECT  2.16 35.775 41.04 36.045 ;
     RECT  2.16 36.315 41.04 36.585 ;
     RECT  2.16 36.855 41.04 37.125 ;
     RECT  2.16 37.395 41.04 37.665 ;
     RECT  2.16 37.935 41.04 38.205 ;
     RECT  2.16 38.475 41.04 38.745 ;
     RECT  2.16 39.015 41.04 39.285 ;
     RECT  2.16 39.555 41.04 39.825 ;
     RECT  2.16 40.095 41.04 40.365 ;
     RECT  2.16 40.635 41.04 40.905 ;
     RECT  2.16 41.175 41.04 41.445 ;
     RECT  2.16 41.715 41.04 41.985 ;
     RECT  2.16 42.255 41.04 42.525 ;
     RECT  2.16 42.795 41.04 43.065 ;
     RECT  2.16 43.335 41.04 43.605 ;
     RECT  2.16 43.875 41.04 44.145 ;
     RECT  2.16 44.415 41.04 44.685 ;
     RECT  2.16 44.955 41.04 45.225 ;
     RECT  2.16 45.495 41.04 45.765 ;
     RECT  2.16 46.035 41.04 46.305 ;
     RECT  2.16 46.575 41.04 46.845 ;
     RECT  2.16 47.115 41.04 47.385 ;
     RECT  2.16 47.655 41.04 47.925 ;
     RECT  2.16 48.195 41.04 48.465 ;
     RECT  2.16 48.735 41.04 49.005 ;
     RECT  2.16 49.275 41.04 49.545 ;
     RECT  2.16 49.815 41.04 50.085 ;
     RECT  2.16 50.355 41.04 50.625 ;
     RECT  2.16 50.895 41.04 51.165 ;
     RECT  2.16 51.435 41.04 51.705 ;
     RECT  2.16 51.975 41.04 52.245 ;
     RECT  2.16 52.515 41.04 52.785 ;
     RECT  2.16 53.055 41.04 53.325 ;
     RECT  2.16 53.595 41.04 53.865 ;
     RECT  2.16 54.135 41.04 54.405 ;
     RECT  2.16 54.675 41.04 54.945 ;
     RECT  2.16 55.215 41.04 55.485 ;
     RECT  2.16 55.755 41.04 56.025 ;
     RECT  2.16 56.295 41.04 56.565 ;
     RECT  2.16 56.835 41.04 57.105 ;
     RECT  2.16 57.375 41.04 57.645 ;
     RECT  2.16 57.915 41.04 58.185 ;
     RECT  2.16 58.455 41.04 58.725 ;
     RECT  2.16 58.995 41.04 59.265 ;
     RECT  2.16 59.535 41.04 59.805 ;
     RECT  2.16 60.075 41.04 60.345 ;
     RECT  2.16 60.615 41.04 60.885 ;
     RECT  2.16 61.155 41.04 61.425 ;
     RECT  2.16 61.695 41.04 61.965 ;
     RECT  2.16 62.235 41.04 62.505 ;
     RECT  2.16 62.775 41.04 63.045 ;
     RECT  2.16 63.315 41.04 63.585 ;
     RECT  2.16 63.855 41.04 64.125 ;
     RECT  2.16 64.395 41.04 64.665 ;
     RECT  2.16 64.935 41.04 65.205 ;
     RECT  2.16 65.475 41.04 65.745 ;
     RECT  2.16 66.015 41.04 66.285 ;
     RECT  2.16 66.555 41.04 66.825 ;
     RECT  2.16 67.095 41.04 67.365 ;
     RECT  2.16 67.635 41.04 67.905 ;
     RECT  2.16 68.175 41.04 68.445 ;
     RECT  2.16 68.715 41.04 68.985 ;
     RECT  2.16 69.255 41.04 69.525 ;
     RECT  2.16 69.795 41.04 70.065 ;
     RECT  2.16 70.335 41.04 70.605 ;
     RECT  2.16 70.875 41.04 71.145 ;
     RECT  2.16 71.415 41.04 71.685 ;
     RECT  2.16 71.955 41.04 72.225 ;
     RECT  2.16 72.495 41.04 72.765 ;
     RECT  2.16 73.035 41.04 73.305 ;
     RECT  2.16 73.575 41.04 73.845 ;
     RECT  2.16 74.115 41.04 74.385 ;
     RECT  2.16 74.655 41.04 74.925 ;
     RECT  2.16 75.195 41.04 75.465 ;
    LAYER M1 ;
     RECT  2.16 2.151 41.04 75.609 ;
    LAYER M2 ;
     RECT  6.367 1.152 6.467 1.17 ;
     RECT  2.16 2.151 7.555 75.609 ;
     RECT  7.555 2.106 10.211 75.609 ;
     RECT  11.443 1.152 11.543 1.17 ;
     RECT  10.211 2.151 12.415 75.609 ;
     RECT  12.415 2.106 13.091 75.609 ;
     RECT  13.855 1.152 13.991 1.17 ;
     RECT  13.091 2.151 41.04 75.609 ;
     RECT  41.04 3.618 41.603 7.956 ;
     RECT  41.04 8.82 41.603 8.838 ;
     RECT  41.04 12.798 41.603 18.486 ;
     RECT  41.04 19.584 41.603 19.638 ;
     RECT  41.04 20.43 41.603 22.806 ;
     RECT  41.04 23.598 41.603 26.856 ;
     RECT  41.04 27.648 41.603 29.556 ;
     RECT  41.04 33.048 41.603 36.648 ;
     RECT  41.04 41.418 41.603 41.976 ;
     RECT  41.04 42.732 41.603 43.056 ;
     RECT  41.04 43.848 41.603 46.638 ;
     RECT  41.04 47.43 41.603 49.302 ;
     RECT  41.04 50.13 41.603 55.278 ;
     RECT  41.04 56.268 41.603 56.826 ;
     RECT  41.04 57.888 41.603 58.986 ;
     RECT  41.04 60.12 41.603 63.576 ;
     RECT  41.04 64.638 41.603 70.596 ;
     RECT  41.04 71.73 41.603 74.376 ;
     RECT  41.04 9.63 41.639 11.196 ;
     RECT  41.603 25.02 41.639 26.316 ;
     RECT  41.603 48.24 41.639 48.258 ;
     RECT  41.603 5.85 41.855 6.84 ;
     RECT  41.639 9.63 41.855 9.648 ;
     RECT  41.603 12.798 41.855 14.706 ;
     RECT  41.603 15.84 41.855 15.858 ;
     RECT  41.603 20.7 41.855 22.806 ;
     RECT  41.603 52.56 41.855 53.01 ;
     RECT  41.603 61.2 41.855 61.218 ;
     RECT  41.603 63.09 41.855 63.576 ;
     RECT  41.603 64.638 41.855 65.268 ;
     RECT  41.603 67.95 41.855 68.274 ;
     RECT  41.603 71.73 41.855 71.748 ;
     RECT  41.603 19.62 41.927 19.638 ;
     RECT  41.639 25.02 41.927 25.038 ;
     RECT  41.04 30.618 41.927 32.256 ;
     RECT  41.603 33.318 41.927 36.306 ;
     RECT  41.603 44.658 41.927 45.828 ;
     RECT  41.603 55.26 41.927 55.278 ;
     RECT  41.603 60.12 41.927 60.138 ;
     RECT  41.855 68.256 41.927 68.274 ;
     RECT  41.603 73.35 41.927 73.368 ;
     RECT  41.603 3.618 42.179 4.176 ;
     RECT  41.855 6.318 42.179 6.84 ;
     RECT  41.603 7.938 42.179 7.956 ;
     RECT  41.639 10.638 42.179 11.196 ;
     RECT  41.04 11.952 42.179 11.97 ;
     RECT  41.855 12.798 42.179 13.662 ;
     RECT  41.855 14.688 42.179 14.706 ;
     RECT  41.603 18.468 42.179 18.486 ;
     RECT  41.855 21.24 42.179 22.806 ;
     RECT  41.603 23.598 42.179 23.886 ;
     RECT  41.639 26.028 42.179 26.316 ;
     RECT  41.603 27.648 42.179 27.666 ;
     RECT  41.603 28.458 42.179 28.476 ;
     RECT  41.603 29.538 42.179 29.556 ;
     RECT  41.927 30.618 42.179 30.636 ;
     RECT  41.927 31.698 42.179 32.256 ;
     RECT  41.927 33.318 42.179 33.336 ;
     RECT  41.927 35.748 42.179 36.306 ;
     RECT  41.603 41.418 42.179 41.436 ;
     RECT  41.603 43.848 42.179 43.866 ;
     RECT  41.927 44.658 42.179 44.676 ;
     RECT  41.603 49.284 42.179 49.302 ;
     RECT  41.603 51.138 42.179 51.156 ;
     RECT  41.855 52.992 42.179 53.01 ;
     RECT  41.603 54.108 42.179 54.126 ;
     RECT  41.855 63.558 42.179 63.576 ;
     RECT  41.855 64.638 42.179 64.656 ;
     RECT  41.603 70.038 42.179 70.056 ;
     RECT  41.603 74.358 42.179 74.376 ;
     RECT  42.179 21.24 42.215 21.258 ;
     RECT  41.04 38.988 42.215 39.006 ;
    LAYER M3 ;
     RECT  11.16 0.091 11.178 0.139 ;
     RECT  11.916 0.091 11.934 0.139 ;
     RECT  13.68 0.139 13.698 0.187 ;
     RECT  13.68 0.187 13.95 0.283 ;
     RECT  14.688 0.091 14.706 0.283 ;
     RECT  8.352 0.091 8.802 0.317 ;
     RECT  6.444 0.427 6.462 0.475 ;
     RECT  8.676 0.317 8.802 0.523 ;
     RECT  6.156 0.475 6.462 0.571 ;
     RECT  7.236 0.091 7.254 0.571 ;
     RECT  11.16 0.139 11.934 0.571 ;
     RECT  6.156 0.571 7.254 1.003 ;
     RECT  6.156 1.003 7.326 1.099 ;
     RECT  8.676 0.523 9.09 1.147 ;
     RECT  8.676 1.147 9.126 1.675 ;
     RECT  6.156 1.099 7.362 1.723 ;
     RECT  8.172 1.675 9.126 1.723 ;
     RECT  10.08 0.523 10.098 1.723 ;
     RECT  11.16 0.571 12.654 1.723 ;
     RECT  10.08 1.723 12.654 2.101 ;
     RECT  13.68 0.283 14.706 2.101 ;
     RECT  21.636 1.723 21.654 2.143 ;
     RECT  6.156 1.723 9.126 2.191 ;
     RECT  10.08 2.101 14.706 2.191 ;
     RECT  22.68 2.191 22.698 2.227 ;
     RECT  5.115 2.143 5.205 2.263 ;
     RECT  6.156 2.191 14.742 2.263 ;
     RECT  22.608 2.227 22.698 2.263 ;
     RECT  15.915 2.143 16.005 2.371 ;
     RECT  18.615 2.143 18.705 2.371 ;
     RECT  26.715 2.143 26.805 2.371 ;
     RECT  32.115 2.143 32.205 2.371 ;
     RECT  2.415 2.143 2.505 2.413 ;
     RECT  24.015 2.143 24.105 2.413 ;
     RECT  25.992 2.371 26.805 2.413 ;
     RECT  29.415 2.143 29.505 2.413 ;
     RECT  32.04 2.371 32.205 2.413 ;
     RECT  34.815 2.143 34.905 2.413 ;
     RECT  37.515 2.143 37.605 2.413 ;
     RECT  40.215 2.143 40.305 2.413 ;
     RECT  15.915 2.371 16.254 2.461 ;
     RECT  21.315 2.143 21.654 2.461 ;
     RECT  15.915 2.461 16.614 2.497 ;
     RECT  29.415 2.413 29.697 2.497 ;
     RECT  30.744 2.497 30.762 2.533 ;
     RECT  21.315 2.461 21.87 2.605 ;
     RECT  22.608 2.263 22.77 2.605 ;
     RECT  15.876 2.497 16.83 2.641 ;
     RECT  18.615 2.371 19.422 2.641 ;
     RECT  24.015 2.413 24.297 2.641 ;
     RECT  28.368 2.605 28.386 2.641 ;
     RECT  29.415 2.497 29.97 2.641 ;
     RECT  30.708 2.533 30.762 2.641 ;
     RECT  25.992 2.413 26.997 2.731 ;
     RECT  27.936 2.641 28.386 2.731 ;
     RECT  29.415 2.641 31.23 2.731 ;
     RECT  32.04 2.413 32.397 2.731 ;
     RECT  29.415 2.731 32.397 2.767 ;
     RECT  25.992 2.731 28.386 2.803 ;
     RECT  29.268 2.767 32.397 2.803 ;
     RECT  36.54 2.731 36.774 2.803 ;
     RECT  37.515 2.413 37.797 2.803 ;
     RECT  15.876 2.641 17.298 2.839 ;
     RECT  18.615 2.641 19.962 2.839 ;
     RECT  21.315 2.605 22.77 2.839 ;
     RECT  23.76 2.641 24.297 2.839 ;
     RECT  29.124 2.803 32.397 2.839 ;
     RECT  34.815 2.413 35.097 2.839 ;
     RECT  25.632 2.803 28.386 2.875 ;
     RECT  29.124 2.839 32.67 2.875 ;
     RECT  36.54 2.803 37.797 2.875 ;
     RECT  25.632 2.875 32.67 2.911 ;
     RECT  34.344 2.839 35.097 2.911 ;
     RECT  36.396 2.875 37.797 2.911 ;
     RECT  5.115 2.263 14.778 3.001 ;
     RECT  15.876 2.839 20.142 3.001 ;
     RECT  21.315 2.839 24.297 3.001 ;
     RECT  25.632 2.911 33.03 3.001 ;
     RECT  34.164 2.911 37.797 3.001 ;
     RECT  21.315 3.001 24.642 3.037 ;
     RECT  25.632 3.001 37.797 3.037 ;
     RECT  5.115 3.001 20.142 3.145 ;
     RECT  5.115 3.145 20.286 3.181 ;
     RECT  21.315 3.037 37.797 3.181 ;
     RECT  39.096 3.451 39.114 3.577 ;
     RECT  39.096 3.577 39.366 3.649 ;
     RECT  38.52 3.649 39.366 3.721 ;
     RECT  40.215 2.413 40.497 3.721 ;
     RECT  38.52 3.721 40.497 3.947 ;
     RECT  42.156 3.595 42.174 4.181 ;
     RECT  5.115 3.181 37.797 4.621 ;
     RECT  38.52 3.947 38.538 4.621 ;
     RECT  5.115 4.621 38.538 4.801 ;
     RECT  39.276 3.947 40.497 4.801 ;
     RECT  5.115 4.801 40.497 4.955 ;
     RECT  5.115 4.955 38.466 4.991 ;
     RECT  41.58 4.651 41.598 5.333 ;
     RECT  6.228 4.991 38.466 5.567 ;
     RECT  41.832 5.707 41.85 5.873 ;
     RECT  15.552 5.567 38.466 5.881 ;
     RECT  39.78 4.955 40.497 5.995 ;
     RECT  39.708 5.995 40.497 6.035 ;
     RECT  6.228 5.567 14.778 6.071 ;
     RECT  39.78 6.035 40.497 6.151 ;
     RECT  39.78 6.151 40.698 6.413 ;
     RECT  6.3 6.071 14.778 6.421 ;
     RECT  15.552 5.881 38.79 6.421 ;
     RECT  39.78 6.413 40.497 6.683 ;
     RECT  42.156 6.235 42.174 6.845 ;
     RECT  6.3 6.421 38.79 6.961 ;
     RECT  5.115 4.991 5.397 7.051 ;
     RECT  6.3 6.961 38.826 7.051 ;
     RECT  41.58 7.291 41.598 7.421 ;
     RECT  5.115 7.051 38.898 7.501 ;
     RECT  39.852 6.683 40.497 7.501 ;
     RECT  42.156 7.819 42.174 7.961 ;
     RECT  5.115 7.501 40.497 8.429 ;
     RECT  26.604 8.429 40.497 8.465 ;
     RECT  41.58 8.347 41.598 8.843 ;
     RECT  26.715 8.465 40.497 8.875 ;
     RECT  26.715 8.875 41.022 9.113 ;
     RECT  5.115 8.429 25.722 9.247 ;
     RECT  26.715 9.113 40.497 9.247 ;
     RECT  41.832 9.403 41.85 9.653 ;
     RECT  41.616 9.895 41.634 9.965 ;
     RECT  42.156 10.459 42.174 11.201 ;
     RECT  5.115 9.247 40.497 11.515 ;
     RECT  5.115 11.515 40.554 12.091 ;
     RECT  5.115 12.091 40.626 12.209 ;
     RECT  42.156 11.947 42.174 13.667 ;
     RECT  5.115 12.209 40.497 13.801 ;
     RECT  5.115 13.801 40.734 14.099 ;
     RECT  41.832 14.155 41.85 14.243 ;
     RECT  42.156 14.683 42.174 14.72 ;
     RECT  41.58 15.211 41.598 15.323 ;
     RECT  41.832 15.739 41.85 15.863 ;
     RECT  5.115 14.099 40.497 16.681 ;
     RECT  5.115 16.681 40.59 17.581 ;
     RECT  41.58 16.267 41.598 18.023 ;
     RECT  5.115 17.581 40.806 18.121 ;
     RECT  5.115 18.121 40.914 18.419 ;
     RECT  42.156 18.379 42.174 18.491 ;
     RECT  5.115 18.419 40.806 18.527 ;
     RECT  5.115 18.527 40.518 18.833 ;
     RECT  41.58 18.907 41.598 19.435 ;
     RECT  41.58 19.435 41.922 19.643 ;
     RECT  21.096 18.833 40.518 19.651 ;
     RECT  21.096 19.651 40.842 19.769 ;
     RECT  21.096 19.769 40.497 19.849 ;
     RECT  5.115 18.833 20.034 19.921 ;
     RECT  21.06 19.849 40.497 19.949 ;
     RECT  23.94 19.949 40.497 20.075 ;
     RECT  21.06 19.949 23.13 20.155 ;
     RECT  21.024 20.155 23.13 20.353 ;
     RECT  20.952 20.353 23.13 20.425 ;
     RECT  41.58 19.643 41.598 20.453 ;
     RECT  41.832 20.491 41.85 20.723 ;
     RECT  5.115 19.921 20.106 20.731 ;
     RECT  20.844 20.425 23.13 20.731 ;
     RECT  23.976 20.075 40.497 21.001 ;
     RECT  23.976 21.001 40.518 21.091 ;
     RECT  23.868 21.091 40.518 21.155 ;
     RECT  42.192 21.019 42.21 21.263 ;
     RECT  5.115 20.731 23.13 21.271 ;
     RECT  23.868 21.155 40.497 21.271 ;
     RECT  5.115 21.271 40.497 22.081 ;
     RECT  5.115 22.081 40.662 22.235 ;
     RECT  42.156 21.547 42.174 23.891 ;
     RECT  5.115 22.235 40.497 23.971 ;
     RECT  5.115 23.971 40.626 24.161 ;
     RECT  41.58 24.187 41.598 24.431 ;
     RECT  41.904 24.715 41.922 25.043 ;
     RECT  41.616 25.243 41.634 25.547 ;
     RECT  5.115 24.161 40.497 26.131 ;
     RECT  5.115 26.131 40.842 26.249 ;
     RECT  42.156 25.771 42.174 26.333 ;
     RECT  41.58 26.824 41.598 26.861 ;
     RECT  5.115 26.249 40.497 27.301 ;
     RECT  42.156 27.355 42.174 27.671 ;
     RECT  5.115 27.301 40.554 27.715 ;
     RECT  41.58 27.883 41.598 27.941 ;
     RECT  42.156 28.411 42.174 28.481 ;
     RECT  5.115 27.715 40.59 28.831 ;
     RECT  5.115 28.831 40.878 28.939 ;
     RECT  5.115 28.939 41.598 29.021 ;
     RECT  42.156 29.467 42.174 29.561 ;
     RECT  42.156 30.523 42.174 30.641 ;
     RECT  41.904 31.051 41.922 31.253 ;
     RECT  42.156 31.579 42.174 32.261 ;
     RECT  5.115 29.021 40.878 32.635 ;
     RECT  5.115 32.635 41.598 33.071 ;
     RECT  41.904 33.163 42.174 33.341 ;
     RECT  41.904 33.341 41.922 35.033 ;
     RECT  42.156 35.275 42.174 36.311 ;
     RECT  5.115 33.071 40.878 36.331 ;
     RECT  5.115 36.331 41.598 36.653 ;
     RECT  43.092 38.203 43.11 38.381 ;
     RECT  5.115 36.653 40.878 39.091 ;
     RECT  42.192 38.983 42.21 39.389 ;
     RECT  5.115 39.091 40.95 40.091 ;
     RECT  5.115 40.091 40.914 40.829 ;
     RECT  42.156 41.371 42.174 41.441 ;
     RECT  5.115 40.829 40.878 41.899 ;
     RECT  5.115 41.899 41.598 42.179 ;
     RECT  5.115 42.179 30.474 42.359 ;
     RECT  31.356 42.179 41.598 42.521 ;
     RECT  31.356 42.521 40.806 43.033 ;
     RECT  41.58 42.521 41.598 43.061 ;
     RECT  5.115 42.359 30.402 43.411 ;
     RECT  31.176 43.033 40.806 43.411 ;
     RECT  42.156 43.483 42.174 44.011 ;
     RECT  41.58 44.011 42.174 44.213 ;
     RECT  5.115 43.411 40.806 44.419 ;
     RECT  42.156 44.213 42.174 44.681 ;
     RECT  5.115 44.419 40.914 44.879 ;
     RECT  5.115 44.879 30.618 44.987 ;
     RECT  5.115 44.987 20.43 45.733 ;
     RECT  21.168 44.987 30.618 45.733 ;
     RECT  5.115 45.733 30.618 45.769 ;
     RECT  31.356 44.879 40.806 45.769 ;
     RECT  41.904 45.067 41.922 45.833 ;
     RECT  41.58 46.123 41.598 48.229 ;
     RECT  41.58 48.229 41.634 48.269 ;
     RECT  5.115 45.769 40.806 48.271 ;
     RECT  41.58 48.269 41.598 48.271 ;
     RECT  5.115 48.271 41.598 48.461 ;
     RECT  41.58 48.461 41.598 49.001 ;
     RECT  42.156 49.279 42.174 49.325 ;
     RECT  5.115 48.461 40.806 49.351 ;
     RECT  5.115 49.351 40.914 49.469 ;
     RECT  41.58 49.819 41.598 50.423 ;
     RECT  5.115 49.469 40.554 50.701 ;
     RECT  5.04 50.701 40.554 51.089 ;
     RECT  42.156 50.875 42.174 51.161 ;
     RECT  5.04 51.089 17.514 51.241 ;
     RECT  4.752 51.241 17.514 51.871 ;
     RECT  41.58 51.403 41.598 51.971 ;
     RECT  4.752 51.871 17.55 52.051 ;
     RECT  18.324 51.089 40.554 52.051 ;
     RECT  41.832 52.459 41.85 52.583 ;
     RECT  4.752 52.051 40.554 52.789 ;
     RECT  4.752 52.789 40.914 52.925 ;
     RECT  4.896 52.925 40.914 52.979 ;
     RECT  42.156 52.987 42.174 53.024 ;
     RECT  41.58 53.515 41.598 53.591 ;
     RECT  5.115 52.979 40.554 53.969 ;
     RECT  42.156 54.043 42.174 54.131 ;
     RECT  5.115 53.969 27.27 54.445 ;
     RECT  41.58 54.571 41.598 54.635 ;
     RECT  28.044 53.969 40.554 54.751 ;
     RECT  28.044 54.751 40.626 54.869 ;
     RECT  5.004 54.445 27.27 54.949 ;
     RECT  28.044 54.869 40.554 54.949 ;
     RECT  41.904 55.099 41.922 55.283 ;
     RECT  5.004 54.949 40.554 55.291 ;
     RECT  4.968 55.291 40.554 55.409 ;
     RECT  5.115 55.409 40.554 55.627 ;
     RECT  5.115 55.627 41.022 55.823 ;
     RECT  5.115 55.823 40.554 55.859 ;
     RECT  41.58 56.155 41.598 56.831 ;
     RECT  5.115 55.859 40.497 57.931 ;
     RECT  4.896 57.931 40.497 57.983 ;
     RECT  41.58 57.739 41.598 58.991 ;
     RECT  5.115 57.983 40.497 59.261 ;
     RECT  20.268 59.261 40.497 59.837 ;
     RECT  5.115 59.261 19.386 60.115 ;
     RECT  41.904 59.851 41.922 60.143 ;
     RECT  5.115 60.115 19.782 60.427 ;
     RECT  41.58 60.379 41.598 60.611 ;
     RECT  4.572 60.427 19.782 60.655 ;
     RECT  20.52 59.837 40.497 60.655 ;
     RECT  41.832 60.907 41.85 61.223 ;
     RECT  4.572 60.655 40.497 62.465 ;
     RECT  41.58 61.435 41.598 62.573 ;
     RECT  4.716 62.465 40.497 62.699 ;
     RECT  41.832 63.019 41.85 63.113 ;
     RECT  5.04 62.699 40.497 63.239 ;
     RECT  42.156 63.544 42.174 63.581 ;
     RECT  5.04 63.239 19.422 63.661 ;
     RECT  5.004 63.661 19.422 63.779 ;
     RECT  5.004 63.779 19.242 63.823 ;
     RECT  4.932 63.823 19.242 63.931 ;
     RECT  4.824 63.931 19.242 64.129 ;
     RECT  20.232 63.239 40.497 64.355 ;
     RECT  42.156 64.603 42.174 64.661 ;
     RECT  4.68 64.129 19.242 64.705 ;
     RECT  4.68 64.705 19.278 64.741 ;
     RECT  20.808 64.355 40.497 64.769 ;
     RECT  21.06 64.769 40.497 64.831 ;
     RECT  21.06 64.831 40.734 64.859 ;
     RECT  4.572 64.741 19.818 64.895 ;
     RECT  4.572 64.895 19.746 64.925 ;
     RECT  21.132 64.859 40.734 64.931 ;
     RECT  4.932 64.925 19.746 64.973 ;
     RECT  21.168 64.931 40.734 64.973 ;
     RECT  19.728 64.973 19.746 65.039 ;
     RECT  23.868 64.973 40.734 65.129 ;
     RECT  23.868 65.129 40.662 65.165 ;
     RECT  4.932 64.973 18.897 65.237 ;
     RECT  23.868 65.165 40.497 65.237 ;
     RECT  41.832 65.131 41.85 65.273 ;
     RECT  21.168 64.973 22.77 65.399 ;
     RECT  21.168 65.399 22.158 65.659 ;
     RECT  23.868 65.237 39.294 65.785 ;
     RECT  23.508 65.785 39.294 65.821 ;
     RECT  23.004 65.821 39.294 65.849 ;
     RECT  5.115 65.237 18.897 66.091 ;
     RECT  20.988 65.659 22.158 66.139 ;
     RECT  20.556 66.139 22.158 66.187 ;
     RECT  23.004 65.849 38.538 66.187 ;
     RECT  4.788 66.091 18.897 66.361 ;
     RECT  40.068 65.237 40.497 66.361 ;
     RECT  4.788 66.361 18.918 66.365 ;
     RECT  4.932 66.365 18.918 66.479 ;
     RECT  5.115 66.479 18.918 66.515 ;
     RECT  39.852 66.361 40.497 66.623 ;
     RECT  20.556 66.187 38.538 66.757 ;
     RECT  5.115 66.515 18.897 66.785 ;
     RECT  20.232 66.757 38.538 66.793 ;
     RECT  20.232 66.793 38.754 66.797 ;
     RECT  20.592 66.797 38.754 67.055 ;
     RECT  20.592 67.055 35.55 67.091 ;
     RECT  5.115 66.785 5.454 67.199 ;
     RECT  6.228 66.785 18.897 67.291 ;
     RECT  6.228 67.291 19.062 67.531 ;
     RECT  19.836 67.369 19.854 67.531 ;
     RECT  20.592 67.091 21.597 67.531 ;
     RECT  36.54 67.055 38.754 67.531 ;
     RECT  41.58 65.659 41.598 67.631 ;
     RECT  6.228 67.531 21.597 67.711 ;
     RECT  36.54 67.531 39.006 67.711 ;
     RECT  40.215 66.623 40.497 67.711 ;
     RECT  22.5 67.091 35.55 67.801 ;
     RECT  36.54 67.711 40.497 67.801 ;
     RECT  22.5 67.801 40.497 67.901 ;
     RECT  5.115 67.199 5.397 67.945 ;
     RECT  6.192 67.711 21.597 67.945 ;
     RECT  41.832 67.771 41.85 67.973 ;
     RECT  5.115 67.945 21.597 68.251 ;
     RECT  40.215 67.901 40.497 68.251 ;
     RECT  41.904 68.251 41.922 68.333 ;
     RECT  4.968 68.251 21.597 68.347 ;
     RECT  40.215 68.251 40.698 68.405 ;
     RECT  23.04 67.901 39.33 68.783 ;
     RECT  4.968 68.347 22.194 68.945 ;
     RECT  7.416 68.945 22.194 68.989 ;
     RECT  23.04 68.783 39.15 68.989 ;
     RECT  4.968 68.945 6.642 69.215 ;
     RECT  7.416 68.989 39.15 69.215 ;
     RECT  6.264 69.215 6.642 69.521 ;
     RECT  41.58 68.827 41.598 69.521 ;
     RECT  7.416 69.215 37.797 69.581 ;
     RECT  40.215 68.405 40.497 69.601 ;
     RECT  6.516 69.521 6.642 69.691 ;
     RECT  7.416 69.581 20.214 69.691 ;
     RECT  38.52 69.215 39.15 69.691 ;
     RECT  40.215 69.601 40.554 69.871 ;
     RECT  6.516 69.691 20.214 69.989 ;
     RECT  21.204 69.581 37.797 69.989 ;
     RECT  42.156 69.883 42.174 70.061 ;
     RECT  38.52 69.691 39.366 70.141 ;
     RECT  40.215 69.871 40.734 70.141 ;
     RECT  7.815 69.989 20.214 70.295 ;
     RECT  21.204 69.989 33.498 70.375 ;
     RECT  6.516 69.989 6.534 70.403 ;
     RECT  34.236 69.989 37.797 70.411 ;
     RECT  38.52 70.141 40.734 70.411 ;
     RECT  17.028 70.295 20.214 70.507 ;
     RECT  21.06 70.375 33.498 70.507 ;
     RECT  41.58 70.411 41.598 70.601 ;
     RECT  17.028 70.507 33.498 70.807 ;
     RECT  34.236 70.411 40.734 70.807 ;
     RECT  17.028 70.807 40.734 70.835 ;
     RECT  17.028 70.835 38.61 70.877 ;
     RECT  39.348 70.835 40.734 70.939 ;
     RECT  34.38 70.877 38.61 70.979 ;
     RECT  34.38 70.979 37.854 71.069 ;
     RECT  7.815 70.295 16.29 71.105 ;
     RECT  39.348 70.939 41.022 71.141 ;
     RECT  17.028 70.877 33.534 71.177 ;
     RECT  39.744 71.141 41.022 71.213 ;
     RECT  17.028 71.177 19.494 71.339 ;
     RECT  20.232 71.177 33.534 71.339 ;
     RECT  17.028 71.339 19.314 71.455 ;
     RECT  20.592 71.339 33.534 71.483 ;
     RECT  41.832 71.467 41.85 71.753 ;
     RECT  38.592 70.979 38.61 71.761 ;
     RECT  38.592 71.761 38.898 71.837 ;
     RECT  7.815 71.105 16.197 71.851 ;
     RECT  16.956 71.455 19.314 71.851 ;
     RECT  20.736 71.483 33.534 71.879 ;
     RECT  39.744 71.213 40.497 71.879 ;
     RECT  7.815 71.851 19.314 71.915 ;
     RECT  21.315 71.879 33.534 71.915 ;
     RECT  38.592 71.837 38.61 72.265 ;
     RECT  21.315 71.915 21.978 72.419 ;
     RECT  22.824 71.915 33.534 72.419 ;
     RECT  39.888 71.879 40.497 72.455 ;
     RECT  7.815 71.915 18.897 72.563 ;
     RECT  22.824 72.419 22.986 72.563 ;
     RECT  23.94 72.419 33.534 72.571 ;
     RECT  34.38 71.069 37.797 72.571 ;
     RECT  23.94 72.571 37.797 72.661 ;
     RECT  38.52 72.265 38.61 72.661 ;
     RECT  22.968 72.563 22.986 72.689 ;
     RECT  23.94 72.661 38.61 72.769 ;
     RECT  23.94 72.769 39.114 72.833 ;
     RECT  41.58 71.995 41.598 72.833 ;
     RECT  24.015 72.833 39.114 72.959 ;
     RECT  25.128 72.959 39.114 72.989 ;
     RECT  25.128 72.989 33.102 72.995 ;
     RECT  7.815 72.563 16.197 73.103 ;
     RECT  8.892 73.103 16.197 73.229 ;
     RECT  8.892 73.229 9.306 73.265 ;
     RECT  9.108 73.265 9.306 73.301 ;
     RECT  9.108 73.301 9.126 73.337 ;
     RECT  41.904 73.051 41.922 73.373 ;
     RECT  25.128 72.995 31.158 73.421 ;
     RECT  40.215 72.455 40.497 73.471 ;
     RECT  26.028 73.421 31.158 73.499 ;
     RECT  32.076 72.995 33.102 73.499 ;
     RECT  34.02 72.989 39.114 73.499 ;
     RECT  34.164 73.499 39.114 73.507 ;
     RECT  25.128 73.421 25.146 73.535 ;
     RECT  34.164 73.507 39.366 73.651 ;
     RECT  40.215 73.471 40.554 73.651 ;
     RECT  10.515 73.229 16.197 73.769 ;
     RECT  26.028 73.499 31.014 73.769 ;
     RECT  34.164 73.651 40.554 73.769 ;
     RECT  10.515 73.769 14.67 73.805 ;
     RECT  41.58 73.579 41.598 73.841 ;
     RECT  34.164 73.769 40.497 73.877 ;
     RECT  32.115 73.499 33.102 73.885 ;
     RECT  14.652 73.805 14.67 73.913 ;
     RECT  34.164 73.877 39.042 73.949 ;
     RECT  32.115 73.885 33.138 74.039 ;
     RECT  34.164 73.949 38.79 74.075 ;
     RECT  16.992 72.563 18.897 74.111 ;
     RECT  32.115 74.039 33.066 74.111 ;
     RECT  34.164 74.075 36.774 74.111 ;
     RECT  34.164 74.111 36.126 74.147 ;
     RECT  10.515 73.805 13.77 74.281 ;
     RECT  17.532 74.111 18.897 74.309 ;
     RECT  26.028 73.769 30.978 74.309 ;
     RECT  32.115 74.111 32.994 74.309 ;
     RECT  39.924 73.877 40.497 74.309 ;
     RECT  10.404 74.281 13.77 74.345 ;
     RECT  37.515 74.075 38.79 74.345 ;
     RECT  17.568 74.309 18.897 74.381 ;
     RECT  34.164 74.147 35.154 74.381 ;
     RECT  37.515 74.345 38.142 74.381 ;
     RECT  42.156 74.107 42.174 74.381 ;
     RECT  35.928 74.147 36.126 74.417 ;
     RECT  10.404 74.345 12.402 74.425 ;
     RECT  34.164 74.381 35.097 74.453 ;
     RECT  26.028 74.309 30.726 74.461 ;
     RECT  32.115 74.309 32.634 74.489 ;
     RECT  36.108 74.417 36.126 74.489 ;
     RECT  37.515 74.381 37.854 74.489 ;
     RECT  9.576 74.191 9.594 74.579 ;
     RECT  13.215 74.345 13.77 74.579 ;
     RECT  25.92 74.461 30.726 74.579 ;
     RECT  17.568 74.381 17.838 74.615 ;
     RECT  25.92 74.579 25.938 74.621 ;
     RECT  10.368 74.425 12.402 74.623 ;
     RECT  9.684 74.623 12.402 74.651 ;
     RECT  26.676 74.579 27.522 74.651 ;
     RECT  9.684 74.651 12.33 74.717 ;
     RECT  9.972 74.717 12.33 74.849 ;
     RECT  17.568 74.615 17.766 74.849 ;
     RECT  28.296 74.579 30.726 74.849 ;
     RECT  29.415 74.849 30.366 74.957 ;
     RECT  17.748 74.849 17.766 75.029 ;
     RECT  9.972 74.849 10.926 75.119 ;
     RECT  26.715 74.651 27.522 75.119 ;
     RECT  28.296 74.849 28.674 75.119 ;
     RECT  9.972 75.119 10.797 75.155 ;
     RECT  26.715 75.119 27.378 75.155 ;
     RECT  29.415 74.957 30.33 75.191 ;
     RECT  2.415 2.413 2.697 75.347 ;
     RECT  5.115 69.215 5.397 75.347 ;
     RECT  7.815 73.103 8.097 75.347 ;
     RECT  10.404 75.155 10.797 75.347 ;
     RECT  13.215 74.579 13.497 75.347 ;
     RECT  15.915 73.769 16.197 75.347 ;
     RECT  18.615 74.381 18.897 75.347 ;
     RECT  21.315 72.419 21.597 75.347 ;
     RECT  24.015 72.959 24.297 75.347 ;
     RECT  26.715 75.155 26.997 75.347 ;
     RECT  29.415 75.191 29.697 75.347 ;
     RECT  32.115 74.489 32.397 75.347 ;
     RECT  34.815 74.453 35.097 75.347 ;
     RECT  37.515 74.489 37.797 75.347 ;
     RECT  40.215 74.309 40.497 75.347 ;
     RECT  28.296 75.119 28.53 75.389 ;
     RECT  10.404 75.347 10.605 75.425 ;
     RECT  28.296 75.389 28.314 75.425 ;
     RECT  2.415 75.347 2.505 75.617 ;
     RECT  5.115 75.347 5.205 75.617 ;
     RECT  7.815 75.347 7.905 75.617 ;
     RECT  10.515 75.425 10.605 75.617 ;
     RECT  13.215 75.347 13.305 75.617 ;
     RECT  15.915 75.347 16.005 75.617 ;
     RECT  18.615 75.347 18.705 75.617 ;
     RECT  21.315 75.347 21.405 75.617 ;
     RECT  24.015 75.347 24.105 75.617 ;
     RECT  26.715 75.347 26.805 75.617 ;
     RECT  29.415 75.347 29.505 75.617 ;
     RECT  32.115 75.347 32.205 75.617 ;
     RECT  34.815 75.347 34.905 75.617 ;
     RECT  37.515 75.347 37.605 75.617 ;
     RECT  40.215 75.347 40.305 75.617 ;
    LAYER M4 ;
     RECT  2.408 2.148 2.512 75.612 ;
     RECT  2.512 2.418 2.704 75.342 ;
     RECT  4.957 55.296 4.981 55.32 ;
     RECT  4.741 52.56 5.108 52.92 ;
     RECT  4.981 54.624 5.108 55.32 ;
     RECT  4.885 57.936 5.108 57.96 ;
     RECT  4.981 59.232 5.108 59.256 ;
     RECT  4.561 60.432 5.108 60.456 ;
     RECT  4.561 62.016 5.108 62.04 ;
     RECT  4.561 64.896 5.108 64.92 ;
     RECT  4.777 66.336 5.108 66.36 ;
     RECT  4.957 68.4 5.108 68.424 ;
     RECT  5.108 2.148 5.212 75.612 ;
     RECT  5.212 2.418 5.404 75.342 ;
     RECT  5.404 56.976 5.555 57.96 ;
     RECT  5.404 44.064 5.651 44.088 ;
     RECT  5.404 39.312 5.795 39.96 ;
     RECT  5.404 62.016 5.795 64.92 ;
     RECT  5.404 42.288 5.891 42.744 ;
     RECT  5.795 62.016 5.897 63.864 ;
     RECT  5.897 62.016 6.035 63.816 ;
     RECT  6.035 62.976 6.076 63.816 ;
     RECT  5.404 51.696 6.149 52.584 ;
     RECT  5.404 41.232 6.257 41.256 ;
     RECT  6.145 0.48 6.38 0.504 ;
     RECT  6.38 0.48 6.433 0.552 ;
     RECT  6.433 0.432 6.505 0.552 ;
     RECT  6.505 61.008 6.541 61.032 ;
     RECT  6.149 52.56 6.545 52.584 ;
     RECT  5.555 56.976 6.577 57.912 ;
     RECT  5.404 68.4 6.613 68.952 ;
     RECT  6.541 61.008 6.709 61.416 ;
     RECT  5.404 66.336 6.716 66.648 ;
     RECT  6.613 68.4 6.716 69.192 ;
     RECT  6.716 66.336 6.757 69.192 ;
     RECT  6.709 59.76 6.797 61.416 ;
     RECT  6.757 66.336 6.803 69.72 ;
     RECT  6.721 54.72 6.829 54.744 ;
     RECT  5.795 64.896 6.86 64.92 ;
     RECT  6.803 66.336 6.86 66.888 ;
     RECT  6.541 45.168 6.865 46.152 ;
     RECT  6.757 50.016 6.901 50.04 ;
     RECT  6.965 3.984 6.973 4.008 ;
     RECT  6.793 15.12 7.081 15.144 ;
     RECT  6.505 0.432 7.181 1.128 ;
     RECT  7.045 48.432 7.225 48.456 ;
     RECT  6.076 63.504 7.225 63.816 ;
     RECT  5.404 16.464 7.261 16.488 ;
     RECT  7.181 0.096 7.265 1.128 ;
     RECT  5.891 42.288 7.333 42.312 ;
     RECT  5.404 7.056 7.369 7.08 ;
     RECT  7.261 16.464 7.381 16.584 ;
     RECT  7.297 12.528 7.397 12.552 ;
     RECT  6.577 56.496 7.429 57.912 ;
     RECT  7.004 47.328 7.441 47.352 ;
     RECT  7.225 48.384 7.441 48.456 ;
     RECT  6.973 3.984 7.621 4.104 ;
     RECT  7.513 8.544 7.621 8.568 ;
     RECT  7.081 10.08 7.621 10.104 ;
     RECT  7.225 62.784 7.621 63.816 ;
     RECT  7.429 18.672 7.669 18.696 ;
     RECT  7.225 30.816 7.669 30.84 ;
     RECT  7.045 34.08 7.669 34.104 ;
     RECT  7.405 52.176 7.729 52.2 ;
     RECT  6.829 54.096 7.765 54.744 ;
     RECT  6.613 2.304 7.808 2.328 ;
     RECT  7.621 3.984 7.808 4.584 ;
     RECT  5.404 5.712 7.808 5.736 ;
     RECT  7.369 6.816 7.808 7.08 ;
     RECT  7.621 8.544 7.808 10.104 ;
     RECT  7.397 12.528 7.808 13.128 ;
     RECT  7.081 15.12 7.808 15.384 ;
     RECT  7.381 16.368 7.808 16.584 ;
     RECT  7.669 18.672 7.808 19.56 ;
     RECT  7.693 23.664 7.808 23.688 ;
     RECT  7.549 26.256 7.808 26.28 ;
     RECT  7.225 28.416 7.808 28.44 ;
     RECT  7.669 30.144 7.808 30.84 ;
     RECT  7.669 32.16 7.808 32.184 ;
     RECT  7.669 33.264 7.808 34.104 ;
     RECT  7.621 37.584 7.808 37.608 ;
     RECT  5.795 39.936 7.808 39.96 ;
     RECT  7.333 41.952 7.808 42.312 ;
     RECT  6.865 45.168 7.808 46.248 ;
     RECT  7.441 47.328 7.808 48.456 ;
     RECT  6.901 50.016 7.808 50.856 ;
     RECT  7.729 52.176 7.808 52.296 ;
     RECT  7.765 54.096 7.808 54.888 ;
     RECT  7.429 56.496 7.808 58.632 ;
     RECT  6.797 59.76 7.808 59.784 ;
     RECT  6.797 61.2 7.808 61.224 ;
     RECT  7.621 62.736 7.808 63.816 ;
     RECT  6.86 64.896 7.808 66.888 ;
     RECT  6.803 68.448 7.808 69.72 ;
     RECT  7.265 0.144 7.861 1.128 ;
     RECT  7.808 2.148 7.861 75.612 ;
     RECT  7.861 0.144 7.912 75.612 ;
     RECT  7.912 0.144 8.104 75.342 ;
     RECT  8.104 19.104 8.201 19.56 ;
     RECT  8.104 56.496 8.273 58.68 ;
     RECT  8.104 0.144 8.29 2.952 ;
     RECT  8.104 33.024 8.309 35.928 ;
     RECT  8.104 45.168 8.309 46.056 ;
     RECT  8.29 0.096 8.345 2.952 ;
     RECT  8.104 27.936 8.345 28.44 ;
     RECT  8.309 34.752 8.353 35.928 ;
     RECT  8.273 58.656 8.381 58.68 ;
     RECT  8.104 4.128 8.489 5.16 ;
     RECT  8.104 41.952 8.597 42.312 ;
     RECT  8.104 6.192 8.669 6.84 ;
     RECT  8.669 6.192 8.723 6.264 ;
     RECT  8.201 19.104 8.723 19.512 ;
     RECT  8.104 21.984 8.741 22.008 ;
     RECT  8.104 49.536 8.777 55.272 ;
     RECT  8.104 11.424 8.813 12.024 ;
     RECT  8.104 30.144 8.813 30.168 ;
     RECT  8.777 51.36 8.813 55.272 ;
     RECT  8.104 59.76 8.819 64.968 ;
     RECT  8.345 0.096 8.849 2.28 ;
     RECT  8.345 27.936 8.921 27.96 ;
     RECT  8.813 51.6 8.921 55.272 ;
     RECT  8.104 20.544 8.957 20.568 ;
     RECT  8.104 14.832 8.993 16.392 ;
     RECT  8.921 55.248 9.029 55.272 ;
     RECT  8.104 23.328 9.101 24.168 ;
     RECT  8.819 59.76 9.101 63 ;
     RECT  8.104 7.968 9.109 10.104 ;
     RECT  8.813 11.424 9.109 11.448 ;
     RECT  8.104 47.088 9.125 48.456 ;
     RECT  8.849 0.096 9.137 1.176 ;
     RECT  9.109 7.968 9.155 11.448 ;
     RECT  8.104 65.952 9.173 70.728 ;
     RECT  8.489 4.56 9.205 5.16 ;
     RECT  9.125 46.752 9.205 48.456 ;
     RECT  9.205 46.752 9.209 48.504 ;
     RECT  8.104 31.392 9.277 31.464 ;
     RECT  8.104 37.584 9.277 37.896 ;
     RECT  8.104 25.776 9.349 26.76 ;
     RECT  9.205 29.76 9.349 29.784 ;
     RECT  9.209 47.088 9.349 48.504 ;
     RECT  8.777 49.536 9.349 49.992 ;
     RECT  9.241 17.472 9.385 17.496 ;
     RECT  9.349 25.776 9.385 26.808 ;
     RECT  9.173 65.952 9.388 70.008 ;
     RECT  8.993 14.832 9.389 14.856 ;
     RECT  9.205 4.56 9.397 5.208 ;
     RECT  9.385 25.776 9.457 26.904 ;
     RECT  8.353 35.328 9.457 35.928 ;
     RECT  8.993 16.08 9.497 16.392 ;
     RECT  8.273 56.496 9.529 57.624 ;
     RECT  9.313 3.408 9.541 3.432 ;
     RECT  9.155 7.968 9.541 10.92 ;
     RECT  9.277 42.672 9.565 42.696 ;
     RECT  9.541 3.312 9.637 3.432 ;
     RECT  9.397 4.56 9.637 5.736 ;
     RECT  9.277 31.392 9.644 31.992 ;
     RECT  8.309 33.024 9.644 33.672 ;
     RECT  9.644 31.392 9.685 33.672 ;
     RECT  9.541 7.536 9.709 10.92 ;
     RECT  9.685 31.392 9.733 34.104 ;
     RECT  9.457 35.328 9.733 36.024 ;
     RECT  9.565 12.48 9.781 12.504 ;
     RECT  9.349 28.944 9.781 29.784 ;
     RECT  9.733 31.392 9.781 36.024 ;
     RECT  9.277 37.056 9.781 37.896 ;
     RECT  9.781 31.392 9.788 37.896 ;
     RECT  8.104 40.368 9.817 40.392 ;
     RECT  9.637 2.304 9.829 2.328 ;
     RECT  9.637 3.312 9.829 5.736 ;
     RECT  9.709 7.296 9.829 10.92 ;
     RECT  9.349 47.088 9.877 49.992 ;
     RECT  8.309 45.168 9.889 45.288 ;
     RECT  9.877 47.088 9.889 50.28 ;
     RECT  8.921 51.6 9.889 54.216 ;
     RECT  9.889 72.144 9.925 72.168 ;
     RECT  8.723 19.488 9.961 19.512 ;
     RECT  9.277 20.976 9.961 21.192 ;
     RECT  9.889 45.168 9.997 45.48 ;
     RECT  9.781 12.48 10.033 13.32 ;
     RECT  9.889 47.088 10.069 54.216 ;
     RECT  9.101 59.76 10.069 60.408 ;
     RECT  9.101 61.488 10.069 63 ;
     RECT  9.829 2.304 10.105 5.736 ;
     RECT  9.829 6.864 10.105 10.92 ;
     RECT  9.137 0.096 10.115 0.552 ;
     RECT  9.565 42 10.165 42.696 ;
     RECT  9.817 39.552 10.177 40.392 ;
     RECT  10.165 41.76 10.177 42.696 ;
     RECT  10.105 2.304 10.213 10.92 ;
     RECT  10.033 12.48 10.213 13.368 ;
     RECT  10.069 58.944 10.285 60.408 ;
     RECT  10.115 0.096 10.307 0.504 ;
     RECT  9.457 25.776 10.357 27.192 ;
     RECT  9.788 30.768 10.357 37.896 ;
     RECT  10.177 39.552 10.357 42.696 ;
     RECT  10.069 47.088 10.357 54.744 ;
     RECT  10.213 2.064 10.385 10.92 ;
     RECT  9.781 28.464 10.429 29.784 ;
     RECT  9.961 19.488 10.465 21.192 ;
     RECT  9.101 23.328 10.465 23.832 ;
     RECT  10.385 1.728 10.508 10.92 ;
     RECT  10.213 12.48 10.508 13.656 ;
     RECT  9.497 16.368 10.508 16.392 ;
     RECT  9.385 17.472 10.508 18.312 ;
     RECT  10.465 19.488 10.508 23.832 ;
     RECT  10.357 25.056 10.508 27.192 ;
     RECT  10.429 28.272 10.508 29.784 ;
     RECT  10.357 30.768 10.508 38.424 ;
     RECT  10.357 39.552 10.508 43.032 ;
     RECT  9.997 44.928 10.508 45.48 ;
     RECT  10.357 47.088 10.508 54.984 ;
     RECT  9.529 56.448 10.508 57.624 ;
     RECT  10.285 58.656 10.508 60.408 ;
     RECT  10.069 61.488 10.508 63.096 ;
     RECT  8.819 64.176 10.508 64.968 ;
     RECT  9.388 65.952 10.508 67.752 ;
     RECT  9.388 68.88 10.508 70.008 ;
     RECT  9.925 72.144 10.508 72.936 ;
     RECT  9.673 74.688 10.508 74.712 ;
     RECT  10.508 1.728 10.612 75.612 ;
     RECT  10.612 1.728 10.804 75.342 ;
     RECT  10.804 51.216 10.829 57.336 ;
     RECT  10.804 74.688 10.865 74.712 ;
     RECT  10.804 62.544 10.937 69 ;
     RECT  10.804 25.536 10.973 38.232 ;
     RECT  10.829 51.216 10.973 57.192 ;
     RECT  10.973 25.776 11.009 38.232 ;
     RECT  10.804 18.768 11.045 24.168 ;
     RECT  10.804 39.552 11.153 42.552 ;
     RECT  10.804 43.872 11.153 50.04 ;
     RECT  11.009 25.968 11.219 38.232 ;
     RECT  10.804 58.416 11.219 60.456 ;
     RECT  11.045 18.768 11.267 22.056 ;
     RECT  11.219 31.728 11.297 38.232 ;
     RECT  11.153 39.552 11.315 40.968 ;
     RECT  10.307 0.096 11.317 0.456 ;
     RECT  10.804 17.472 11.333 17.496 ;
     RECT  11.315 39.552 11.333 40.488 ;
     RECT  10.804 69.984 11.363 73.512 ;
     RECT  11.219 25.968 11.369 30.024 ;
     RECT  11.363 69.984 11.441 72.936 ;
     RECT  11.297 33.024 11.459 38.232 ;
     RECT  10.937 65.952 11.477 69 ;
     RECT  11.459 33.648 11.485 38.232 ;
     RECT  11.219 60.432 11.513 60.456 ;
     RECT  10.973 53.568 11.555 57.192 ;
     RECT  11.441 69.984 11.621 71.64 ;
     RECT  10.937 62.544 11.644 64.344 ;
     RECT  10.804 11.376 11.693 11.4 ;
     RECT  11.485 33.648 11.729 36.024 ;
     RECT  11.621 69.984 11.729 70.008 ;
     RECT  10.804 1.728 11.833 9.72 ;
     RECT  11.477 65.952 11.837 67.272 ;
     RECT  11.153 42.192 11.941 42.552 ;
     RECT  11.153 43.872 11.941 45.624 ;
     RECT  11.153 46.848 11.941 50.04 ;
     RECT  10.973 51.216 11.941 52.488 ;
     RECT  11.219 58.416 11.941 58.968 ;
     RECT  11.833 1.728 11.945 10.296 ;
     RECT  11.729 34.368 11.945 36.024 ;
     RECT  11.485 37.056 11.945 38.232 ;
     RECT  11.644 62.544 11.945 63.192 ;
     RECT  11.477 68.4 11.977 69 ;
     RECT  10.804 12.528 12.013 14.952 ;
     RECT  10.804 16.368 12.013 16.392 ;
     RECT  11.441 72.912 12.017 72.936 ;
     RECT  11.941 46.848 12.025 52.488 ;
     RECT  12.013 12.528 12.035 16.392 ;
     RECT  11.945 62.544 12.037 63.096 ;
     RECT  11.945 1.728 12.089 6.552 ;
     RECT  11.369 27.888 12.089 30.024 ;
     RECT  11.977 68.4 12.089 69.24 ;
     RECT  11.045 23.568 12.121 24.168 ;
     RECT  12.121 23.28 12.157 24.168 ;
     RECT  11.369 25.968 12.188 26.808 ;
     RECT  12.157 23.28 12.229 24.456 ;
     RECT  11.267 18.768 12.265 21.192 ;
     RECT  11.317 0.096 12.277 0.6 ;
     RECT  12.089 1.728 12.277 2.328 ;
     RECT  12.037 62.016 12.481 63.096 ;
     RECT  12.277 0.096 12.515 2.328 ;
     RECT  12.025 51.408 12.517 52.488 ;
     RECT  11.555 53.568 12.517 56.856 ;
     RECT  12.515 1.728 12.557 2.328 ;
     RECT  11.837 65.952 12.613 66.84 ;
     RECT  12.515 0.096 12.665 0.6 ;
     RECT  11.333 40.08 12.757 40.488 ;
     RECT  11.941 42.192 12.757 45.624 ;
     RECT  12.265 18.192 12.841 21.192 ;
     RECT  12.481 60.912 12.913 63.096 ;
     RECT  11.945 34.368 13.021 35.304 ;
     RECT  12.517 51.408 13.021 56.856 ;
     RECT  11.297 31.728 13.052 31.944 ;
     RECT  12.613 65.616 13.057 66.84 ;
     RECT  12.089 3.408 13.093 6.552 ;
     RECT  11.941 58.368 13.093 58.968 ;
     RECT  11.644 64.32 13.093 64.344 ;
     RECT  11.945 37.056 13.129 38.04 ;
     RECT  12.557 2.148 13.208 2.328 ;
     RECT  13.093 3.408 13.208 6.84 ;
     RECT  11.945 8.064 13.208 10.296 ;
     RECT  12.035 12.528 13.208 15.576 ;
     RECT  12.841 18.192 13.208 21.96 ;
     RECT  12.229 23.28 13.208 24.504 ;
     RECT  12.188 25.584 13.208 26.808 ;
     RECT  12.089 27.888 13.208 29.928 ;
     RECT  13.052 31.728 13.208 32.76 ;
     RECT  13.021 34.368 13.208 35.736 ;
     RECT  13.129 37.056 13.208 38.472 ;
     RECT  12.757 40.08 13.208 45.624 ;
     RECT  12.025 46.848 13.208 49.848 ;
     RECT  13.021 51.408 13.208 57.048 ;
     RECT  13.093 58.368 13.208 59.016 ;
     RECT  12.913 60.384 13.208 63.096 ;
     RECT  13.093 64.32 13.208 64.632 ;
     RECT  13.057 65.616 13.208 67.32 ;
     RECT  12.089 69.024 13.208 69.24 ;
     RECT  11.621 71.616 13.208 71.64 ;
     RECT  12.553 73.488 13.208 73.512 ;
     RECT  13.208 2.148 13.312 75.612 ;
     RECT  13.312 2.418 13.504 75.342 ;
     RECT  13.504 4.704 13.565 5.736 ;
     RECT  13.504 41.088 13.601 42.696 ;
     RECT  13.504 18.192 13.619 21.672 ;
     RECT  13.504 31.728 13.619 31.848 ;
     RECT  13.504 45.456 13.619 50.136 ;
     RECT  13.504 34.896 13.637 38.808 ;
     RECT  13.504 60.864 13.637 60.984 ;
     RECT  13.619 20.928 13.667 21.672 ;
     RECT  13.504 51.408 13.667 56.616 ;
     RECT  13.504 6.816 13.673 9.768 ;
     RECT  13.504 40.032 13.673 40.104 ;
     RECT  13.619 18.192 13.811 19.8 ;
     RECT  13.504 23.568 13.817 24.12 ;
     RECT  13.811 18.672 13.852 19.368 ;
     RECT  13.817 23.664 13.853 24.12 ;
     RECT  12.665 0.096 13.889 0.36 ;
     RECT  13.667 53.616 13.889 56.616 ;
     RECT  13.504 64.608 13.889 67.32 ;
     RECT  13.504 25.248 13.925 29.016 ;
     RECT  13.673 40.08 13.925 40.104 ;
     RECT  13.619 45.456 13.925 47.352 ;
     RECT  13.504 62.544 13.925 63.24 ;
     RECT  13.637 34.944 13.933 38.808 ;
     RECT  13.889 64.608 13.961 64.632 ;
     RECT  13.925 27.216 13.997 29.016 ;
     RECT  13.673 6.816 14.033 8.568 ;
     RECT  13.889 67.056 14.105 67.32 ;
     RECT  13.997 27.216 14.14 27.912 ;
     RECT  13.565 5.088 14.195 5.736 ;
     RECT  13.925 25.248 14.213 25.704 ;
     RECT  13.933 34.944 14.213 38.472 ;
     RECT  14.033 6.816 14.285 8.184 ;
     RECT  13.925 45.456 14.291 47.16 ;
     RECT  13.504 17.04 14.321 17.064 ;
     RECT  13.667 51.408 14.393 52.44 ;
     RECT  13.889 0.096 14.429 0.312 ;
     RECT  14.285 7.152 14.429 8.184 ;
     RECT  13.504 15.36 14.429 15.576 ;
     RECT  13.852 18.96 14.465 19.368 ;
     RECT  14.105 67.296 14.497 67.32 ;
     RECT  14.213 34.944 14.501 38.232 ;
     RECT  14.291 45.456 14.501 46.152 ;
     RECT  14.393 52.032 14.537 52.44 ;
     RECT  13.601 42.672 14.569 42.696 ;
     RECT  13.667 20.928 14.605 21.528 ;
     RECT  13.925 62.64 14.605 63.24 ;
     RECT  13.504 30.192 14.608 30.744 ;
     RECT  13.637 60.864 14.629 60.936 ;
     RECT  14.501 45.456 14.641 45.576 ;
     RECT  14.501 34.944 14.645 35.736 ;
     RECT  13.504 12.288 14.677 13.176 ;
     RECT  14.569 42.672 14.677 43.272 ;
     RECT  14.629 60.24 14.677 60.936 ;
     RECT  14.497 67.296 14.681 67.416 ;
     RECT  14.677 60.24 14.716 61.608 ;
     RECT  14.429 0.096 14.717 0.12 ;
     RECT  14.14 27.216 14.717 27.24 ;
     RECT  13.601 41.088 14.717 41.112 ;
     RECT  14.681 67.392 14.717 67.416 ;
     RECT  13.619 31.824 14.723 31.848 ;
     RECT  14.677 42.144 14.741 43.272 ;
     RECT  14.677 11.952 14.773 13.176 ;
     RECT  13.504 57.696 14.78 58.68 ;
     RECT  13.619 48.432 14.785 50.136 ;
     RECT  14.773 11.952 14.819 13.656 ;
     RECT  14.741 42.144 14.819 43.896 ;
     RECT  14.716 60.432 14.819 61.608 ;
     RECT  14.605 62.64 14.821 63.528 ;
     RECT  13.504 69.84 14.821 69.864 ;
     RECT  13.504 71.616 14.821 71.928 ;
     RECT  13.504 72.96 14.821 72.984 ;
     RECT  14.608 30.192 14.825 30.792 ;
     RECT  14.819 60.432 14.825 60.888 ;
     RECT  13.997 28.944 14.861 29.016 ;
     RECT  14.785 48.432 14.861 50.664 ;
     RECT  14.78 57.696 14.861 59.064 ;
     RECT  13.889 65.904 14.861 65.976 ;
     RECT  14.861 58.128 14.867 59.064 ;
     RECT  14.821 71.616 14.867 72.984 ;
     RECT  14.429 15.36 14.893 15.432 ;
     RECT  14.465 19.2 14.897 19.368 ;
     RECT  14.821 69.84 14.905 70.44 ;
     RECT  14.605 20.544 14.929 21.528 ;
     RECT  13.504 33.12 15.037 33.288 ;
     RECT  13.889 53.616 15.037 53.688 ;
     RECT  13.889 54.672 15.037 56.616 ;
     RECT  13.673 9.648 15.061 9.768 ;
     RECT  14.713 3.408 15.073 3.432 ;
     RECT  14.195 5.088 15.073 5.112 ;
     RECT  14.821 62.64 15.109 63.816 ;
     RECT  14.897 19.296 15.145 19.368 ;
     RECT  14.929 20.544 15.145 22.2 ;
     RECT  15.037 53.616 15.153 56.616 ;
     RECT  15.145 19.296 15.181 22.2 ;
     RECT  13.853 23.664 15.181 23.928 ;
     RECT  14.905 69.84 15.289 69.864 ;
     RECT  15.061 9.648 15.361 10.296 ;
     RECT  14.861 28.944 15.361 28.968 ;
     RECT  15.109 62.64 15.361 64.008 ;
     RECT  15.037 33.12 15.397 33.432 ;
     RECT  14.677 34.608 15.397 34.632 ;
     RECT  15.361 9.6 15.541 10.296 ;
     RECT  14.501 37.392 15.577 38.232 ;
     RECT  15.433 39.216 15.577 39.24 ;
     RECT  14.537 52.416 15.589 52.44 ;
     RECT  14.641 45.12 15.613 45.576 ;
     RECT  14.819 43.872 15.637 43.896 ;
     RECT  15.613 45.12 15.637 46.104 ;
     RECT  15.289 69.216 15.649 69.864 ;
     RECT  14.861 48.432 15.685 49.08 ;
     RECT  15.541 16.56 15.692 17.16 ;
     RECT  14.291 47.136 15.749 47.16 ;
     RECT  15.685 48.384 15.749 49.08 ;
     RECT  14.861 65.952 15.757 65.976 ;
     RECT  15.589 52.224 15.781 52.44 ;
     RECT  14.213 25.68 15.793 25.704 ;
     RECT  14.819 11.952 15.865 12.312 ;
     RECT  15.577 37.392 15.865 39.24 ;
     RECT  15.781 51.936 15.865 52.44 ;
     RECT  14.825 60.432 15.865 60.456 ;
     RECT  15.073 3.408 15.901 5.112 ;
     RECT  15.061 6.096 15.901 6.12 ;
     RECT  15.541 9.264 15.901 10.296 ;
     RECT  15.865 11.76 15.901 12.312 ;
     RECT  15.901 3.408 15.908 6.12 ;
     RECT  14.429 7.152 15.908 7.176 ;
     RECT  14.429 8.16 15.908 8.184 ;
     RECT  15.901 9.264 15.908 12.312 ;
     RECT  14.819 13.632 15.908 13.656 ;
     RECT  14.893 14.928 15.908 15.432 ;
     RECT  15.692 16.56 15.908 17.64 ;
     RECT  15.181 19.296 15.908 23.928 ;
     RECT  15.793 25.008 15.908 25.704 ;
     RECT  15.505 27.696 15.908 27.72 ;
     RECT  15.361 28.704 15.908 28.968 ;
     RECT  14.825 30.192 15.908 30.696 ;
     RECT  15.397 32.208 15.908 34.632 ;
     RECT  14.645 35.616 15.908 35.736 ;
     RECT  15.865 37.104 15.908 39.24 ;
     RECT  15.637 40.704 15.908 40.728 ;
     RECT  15.865 42.72 15.908 42.744 ;
     RECT  15.637 43.872 15.908 46.104 ;
     RECT  15.749 47.136 15.908 49.08 ;
     RECT  14.861 50.112 15.908 50.664 ;
     RECT  15.865 51.648 15.908 52.488 ;
     RECT  15.153 53.616 15.908 57 ;
     RECT  14.867 58.128 15.908 58.152 ;
     RECT  15.865 60.288 15.908 60.456 ;
     RECT  15.361 62.256 15.908 64.008 ;
     RECT  15.757 65.952 15.908 66.792 ;
     RECT  15.649 69.024 15.908 69.864 ;
     RECT  14.867 71.616 15.908 72.264 ;
     RECT  15.908 2.148 16.012 75.612 ;
     RECT  16.012 2.418 16.204 75.342 ;
     RECT  16.204 62.256 16.229 62.568 ;
     RECT  16.204 53.616 16.265 54.12 ;
     RECT  16.204 3.696 16.301 4.44 ;
     RECT  16.204 28.704 16.301 29.64 ;
     RECT  16.301 3.696 16.373 4.248 ;
     RECT  16.204 11.76 16.373 11.784 ;
     RECT  16.204 65.568 16.373 67.32 ;
     RECT  16.204 50.112 16.409 52.488 ;
     RECT  16.204 47.136 16.481 47.16 ;
     RECT  16.229 62.256 16.481 62.28 ;
     RECT  16.204 13.104 16.517 15.528 ;
     RECT  16.204 5.76 16.547 7.656 ;
     RECT  16.265 54.096 16.547 54.12 ;
     RECT  16.204 56.496 16.553 58.152 ;
     RECT  16.204 9.072 16.589 9.288 ;
     RECT  16.204 32.544 16.589 33.096 ;
     RECT  16.204 23.136 16.625 26.328 ;
     RECT  16.204 30.672 16.697 31.464 ;
     RECT  16.301 28.848 16.739 29.64 ;
     RECT  16.517 13.344 16.805 15.528 ;
     RECT  16.204 34.176 16.805 39.24 ;
     RECT  16.204 42.048 16.835 43.128 ;
     RECT  16.697 30.912 16.841 31.32 ;
     RECT  16.805 34.176 16.841 37.896 ;
     RECT  16.835 42.048 16.877 43.032 ;
     RECT  16.805 14.16 16.883 15.528 ;
     RECT  16.204 16.56 16.883 17.832 ;
     RECT  16.373 66.768 16.883 67.32 ;
     RECT  16.625 23.376 16.913 26.328 ;
     RECT  16.877 42.048 16.913 42.6 ;
     RECT  16.883 67.296 16.924 67.32 ;
     RECT  16.204 59.232 16.931 60.312 ;
     RECT  16.883 16.992 16.949 17.832 ;
     RECT  16.883 14.16 16.985 14.184 ;
     RECT  16.949 16.992 16.985 17.064 ;
     RECT  16.931 59.808 17.021 60.312 ;
     RECT  16.204 71.616 17.027 72.984 ;
     RECT  16.883 15.504 17.165 15.528 ;
     RECT  16.409 51.648 17.165 52.488 ;
     RECT  16.913 25.728 17.237 26.328 ;
     RECT  16.841 34.704 17.237 37.896 ;
     RECT  16.913 23.376 17.273 24.456 ;
     RECT  16.739 29.52 17.273 29.64 ;
     RECT  16.805 39.216 17.273 39.24 ;
     RECT  16.204 48.336 17.273 48.984 ;
     RECT  16.204 69.024 17.341 69.864 ;
     RECT  17.273 29.52 17.345 29.544 ;
     RECT  16.204 63.792 17.372 63.816 ;
     RECT  16.204 19.392 17.377 21.96 ;
     RECT  16.373 65.568 17.413 65.592 ;
     RECT  17.341 68.112 17.413 69.864 ;
     RECT  17.197 15.888 17.417 15.912 ;
     RECT  17.273 48.336 17.417 48.504 ;
     RECT  16.204 27.312 17.449 27.72 ;
     RECT  17.165 51.936 17.521 52.488 ;
     RECT  17.377 18.192 17.525 21.96 ;
     RECT  16.589 32.544 17.561 33.048 ;
     RECT  17.237 34.704 17.561 36.744 ;
     RECT  17.413 68.112 17.593 70.44 ;
     RECT  17.027 71.616 17.593 72.12 ;
     RECT  17.593 68.112 17.597 72.12 ;
     RECT  17.372 63.744 17.605 63.816 ;
     RECT  17.597 69.216 17.633 72.12 ;
     RECT  16.589 9.072 17.665 9.192 ;
     RECT  17.525 19.392 17.665 21.96 ;
     RECT  17.665 8.112 17.729 9.192 ;
     RECT  17.701 10.512 17.749 10.536 ;
     RECT  17.665 19.392 17.773 22.104 ;
     RECT  17.729 7.968 17.804 9.192 ;
     RECT  17.804 7.968 17.845 9.288 ;
     RECT  17.749 10.512 17.845 11.496 ;
     RECT  17.237 37.872 17.845 37.896 ;
     RECT  16.553 57.456 17.845 58.152 ;
     RECT  17.605 63.264 17.845 63.816 ;
     RECT  17.413 64.896 17.845 65.592 ;
     RECT  16.547 5.76 17.917 6.552 ;
     RECT  17.845 7.968 17.989 11.496 ;
     RECT  17.749 13.104 17.989 13.128 ;
     RECT  17.665 3.6 18.025 3.624 ;
     RECT  16.204 44.448 18.061 46.104 ;
     RECT  17.521 51.936 18.061 52.92 ;
     RECT  17.989 15.984 18.085 16.008 ;
     RECT  16.985 16.992 18.085 17.016 ;
     RECT  18.025 3.6 18.133 3.864 ;
     RECT  17.561 34.704 18.133 36.264 ;
     RECT  18.061 44.064 18.133 46.104 ;
     RECT  17.845 56.496 18.133 58.152 ;
     RECT  16.841 30.912 18.205 30.936 ;
     RECT  17.845 64.896 18.229 65.928 ;
     RECT  17.881 39.888 18.236 39.912 ;
     RECT  18.133 3.36 18.241 3.864 ;
     RECT  18.133 44.064 18.277 46.248 ;
     RECT  17.417 48.336 18.277 48.36 ;
     RECT  18.241 3.36 18.313 4.152 ;
     RECT  17.917 5.136 18.313 6.552 ;
     RECT  17.989 7.968 18.313 13.128 ;
     RECT  16.204 55.152 18.385 55.176 ;
     RECT  18.229 64.896 18.469 66.792 ;
     RECT  17.597 68.112 18.469 68.136 ;
     RECT  17.845 62.736 18.493 63.816 ;
     RECT  18.061 41.568 18.529 41.592 ;
     RECT  16.913 42.576 18.529 42.6 ;
     RECT  18.385 54.672 18.529 55.176 ;
     RECT  18.133 56.496 18.529 58.68 ;
     RECT  18.313 3.312 18.608 4.152 ;
     RECT  18.313 5.136 18.608 13.128 ;
     RECT  18.493 14.208 18.608 14.232 ;
     RECT  18.085 15.984 18.608 17.016 ;
     RECT  17.525 18.192 18.608 18.216 ;
     RECT  17.773 19.392 18.608 22.248 ;
     RECT  17.273 23.376 18.608 23.88 ;
     RECT  17.449 26.688 18.608 27.72 ;
     RECT  18.205 30.912 18.608 31.464 ;
     RECT  17.561 32.544 18.608 32.856 ;
     RECT  18.133 34.224 18.608 36.264 ;
     RECT  17.845 37.872 18.608 38.424 ;
     RECT  18.236 39.888 18.608 40.2 ;
     RECT  18.529 41.568 18.608 42.6 ;
     RECT  18.277 44.064 18.608 46.536 ;
     RECT  18.277 48.24 18.608 48.36 ;
     RECT  16.409 50.112 18.608 50.664 ;
     RECT  18.061 51.936 18.608 53.592 ;
     RECT  18.529 54.672 18.608 58.68 ;
     RECT  17.021 59.808 18.608 59.88 ;
     RECT  17.423 60.96 18.608 60.984 ;
     RECT  18.493 62.544 18.608 63.816 ;
     RECT  18.469 64.896 18.608 68.136 ;
     RECT  17.633 69.216 18.608 71.64 ;
     RECT  18.608 2.148 18.712 75.612 ;
     RECT  18.712 2.418 18.904 75.342 ;
     RECT  18.904 62.544 19.037 63.288 ;
     RECT  18.904 51.936 19.043 56.52 ;
     RECT  18.904 66.768 19.073 67.32 ;
     RECT  18.904 3.168 19.145 5.88 ;
     RECT  18.904 30.144 19.181 32.856 ;
     RECT  18.904 64.944 19.181 64.968 ;
     RECT  18.904 68.928 19.187 71.208 ;
     RECT  18.904 58.128 19.217 58.68 ;
     RECT  19.043 51.936 19.245 55.032 ;
     RECT  19.187 68.976 19.325 71.208 ;
     RECT  18.904 12 19.397 17.016 ;
     RECT  18.904 20.544 19.397 23.784 ;
     RECT  19.397 12 19.405 16.392 ;
     RECT  18.904 44.064 19.505 50.616 ;
     RECT  19.325 70.752 19.505 71.208 ;
     RECT  19.245 51.936 19.541 54.696 ;
     RECT  18.904 61.536 19.541 61.56 ;
     RECT  19.405 12.24 19.577 16.392 ;
     RECT  19.397 20.544 19.577 23.688 ;
     RECT  18.904 28.944 19.577 29.112 ;
     RECT  19.505 44.448 19.613 50.616 ;
     RECT  18.904 7.2 19.619 7.512 ;
     RECT  19.577 20.832 19.621 23.688 ;
     RECT  19.145 3.312 19.649 5.88 ;
     RECT  19.613 44.448 19.66 49.128 ;
     RECT  18.904 18.192 19.685 18.792 ;
     RECT  19.621 20.832 19.685 20.856 ;
     RECT  19.325 68.976 19.757 69.24 ;
     RECT  19.577 13.104 19.793 16.392 ;
     RECT  19.685 18.24 19.793 18.792 ;
     RECT  18.904 25.68 19.829 27.72 ;
     RECT  19.181 30.144 19.868 30.456 ;
     RECT  19.793 18.432 19.901 18.792 ;
     RECT  19.829 26.016 19.901 27.72 ;
     RECT  19.043 56.352 19.901 56.52 ;
     RECT  19.66 44.448 19.907 47.304 ;
     RECT  18.904 39.552 19.933 43.032 ;
     RECT  19.793 13.68 19.937 16.392 ;
     RECT  19.937 13.68 19.955 14.616 ;
     RECT  19.868 30 19.955 30.456 ;
     RECT  19.933 39.36 19.969 43.032 ;
     RECT  19.901 56.352 19.973 56.424 ;
     RECT  19.937 15.984 19.981 16.392 ;
     RECT  18.904 34.608 20.003 34.632 ;
     RECT  18.904 8.784 20.005 9.048 ;
     RECT  19.649 3.312 20.009 3.96 ;
     RECT  19.901 18.528 20.009 18.792 ;
     RECT  19.973 56.352 20.041 56.376 ;
     RECT  19.981 16.032 20.045 16.392 ;
     RECT  20.005 8.16 20.149 9.048 ;
     RECT  18.904 10.08 20.149 10.104 ;
     RECT  19.955 30.144 20.149 30.456 ;
     RECT  19.181 31.488 20.149 32.856 ;
     RECT  19.901 27.024 20.153 27.72 ;
     RECT  18.904 37.92 20.185 38.04 ;
     RECT  19.969 39.36 20.185 43.416 ;
     RECT  20.149 8.16 20.189 10.104 ;
     RECT  20.185 37.92 20.189 43.416 ;
     RECT  19.037 63.072 20.204 63.288 ;
     RECT  20.189 9.696 20.221 10.104 ;
     RECT  20.204 62.448 20.221 63.768 ;
     RECT  20.153 27.168 20.225 27.72 ;
     RECT  19.757 69.072 20.225 69.24 ;
     RECT  19.649 5.136 20.257 5.88 ;
     RECT  18.904 35.76 20.257 35.784 ;
     RECT  20.257 5.136 20.261 6.408 ;
     RECT  19.907 44.448 20.261 46.584 ;
     RECT  20.221 62.448 20.291 64.344 ;
     RECT  20.257 35.76 20.293 35.88 ;
     RECT  18.904 59.808 20.297 59.832 ;
     RECT  20.225 27.36 20.3 27.72 ;
     RECT  20.293 35.664 20.437 35.88 ;
     RECT  20.189 37.92 20.437 39.336 ;
     RECT  20.437 35.664 20.473 39.336 ;
     RECT  19.073 66.768 20.533 66.792 ;
     RECT  19.505 70.752 20.54 70.776 ;
     RECT  20.533 66.192 20.545 66.792 ;
     RECT  19.621 22.08 20.581 23.688 ;
     RECT  20.401 24.912 20.581 24.936 ;
     RECT  20.149 30.144 20.581 32.856 ;
     RECT  20.54 70.512 20.581 70.776 ;
     RECT  19.66 48.432 20.653 49.128 ;
     RECT  20.189 8.16 20.725 8.664 ;
     RECT  20.581 69.552 20.725 70.776 ;
     RECT  20.617 12.336 20.761 12.36 ;
     RECT  20.725 8.112 20.797 8.664 ;
     RECT  20.761 12.288 20.797 12.36 ;
     RECT  20.291 64.32 20.869 64.344 ;
     RECT  20.189 40.368 20.941 43.416 ;
     RECT  20.261 44.448 20.941 44.952 ;
     RECT  20.041 56.064 20.977 56.376 ;
     RECT  20.545 66.144 20.977 66.792 ;
     RECT  19.955 13.872 21.013 14.616 ;
     RECT  21.013 13.872 21.049 14.712 ;
     RECT  20.581 22.08 21.049 24.936 ;
     RECT  19.901 26.016 21.049 26.04 ;
     RECT  20.653 48.288 21.049 49.128 ;
     RECT  19.613 50.304 21.049 50.616 ;
     RECT  19.577 28.944 21.085 28.968 ;
     RECT  21.049 13.872 21.109 14.808 ;
     RECT  20.797 7.728 21.157 8.664 ;
     RECT  20.797 11.712 21.157 12.36 ;
     RECT  21.049 22.08 21.157 26.04 ;
     RECT  20.581 30.144 21.229 33.048 ;
     RECT  21.229 30.144 21.265 33.96 ;
     RECT  20.009 3.36 21.308 3.96 ;
     RECT  20.261 5.232 21.308 6.408 ;
     RECT  21.157 7.488 21.308 8.664 ;
     RECT  20.221 9.696 21.308 10.632 ;
     RECT  21.157 11.664 21.308 12.36 ;
     RECT  21.109 13.872 21.308 14.856 ;
     RECT  20.473 16.8 21.308 16.824 ;
     RECT  21.157 21.888 21.308 26.04 ;
     RECT  20.3 27.36 21.308 27.768 ;
     RECT  21.085 28.944 21.308 29.112 ;
     RECT  21.265 30.144 21.308 34.152 ;
     RECT  20.473 35.232 21.308 39.336 ;
     RECT  20.941 40.368 21.308 44.952 ;
     RECT  20.261 46.08 21.308 46.584 ;
     RECT  21.049 48.288 21.308 50.616 ;
     RECT  19.541 51.936 21.308 54.456 ;
     RECT  20.977 55.536 21.308 56.376 ;
     RECT  19.217 58.128 21.308 58.152 ;
     RECT  20.509 59.472 21.308 59.496 ;
     RECT  20.291 62.544 21.308 63.288 ;
     RECT  20.869 64.32 21.308 64.44 ;
     RECT  20.977 65.664 21.308 66.792 ;
     RECT  20.725 69.552 21.308 71.736 ;
     RECT  21.308 2.148 21.412 75.612 ;
     RECT  21.412 2.148 21.541 75.342 ;
     RECT  21.541 1.728 21.604 75.342 ;
     RECT  21.604 11.472 21.629 11.736 ;
     RECT  21.604 1.728 21.665 1.752 ;
     RECT  21.604 64.32 21.665 65.688 ;
     RECT  21.604 14.448 21.701 14.856 ;
     RECT  21.604 67.872 21.731 70.344 ;
     RECT  21.629 11.472 21.779 11.496 ;
     RECT  21.604 4.704 21.875 8.472 ;
     RECT  21.604 23.04 21.881 23.688 ;
     RECT  21.875 4.704 21.916 5.16 ;
     RECT  21.604 26.016 21.953 29.112 ;
     RECT  21.701 14.832 21.989 14.856 ;
     RECT  21.604 44.448 21.989 45.576 ;
     RECT  21.604 48.432 21.989 51.144 ;
     RECT  21.604 31.152 22.025 32.568 ;
     RECT  21.989 44.448 22.097 44.472 ;
     RECT  21.604 52.224 22.097 56.088 ;
     RECT  21.604 58.128 22.133 59.736 ;
     RECT  21.665 64.416 22.133 65.688 ;
     RECT  21.604 25.008 22.169 25.032 ;
     RECT  22.133 58.128 22.169 58.68 ;
     RECT  22.133 65.664 22.211 65.688 ;
     RECT  21.731 67.872 22.211 68.952 ;
     RECT  21.604 20.592 22.277 21.144 ;
     RECT  21.604 71.712 22.277 71.736 ;
     RECT  21.916 5.136 22.499 5.16 ;
     RECT  21.875 6.288 22.499 8.472 ;
     RECT  21.989 48.432 22.499 48.456 ;
     RECT  21.731 70.32 22.529 70.344 ;
     RECT  21.989 45.552 22.633 45.576 ;
     RECT  21.604 46.56 22.633 47.112 ;
     RECT  21.604 33.936 22.709 36.552 ;
     RECT  22.277 20.592 22.745 20.616 ;
     RECT  21.881 23.664 22.777 23.688 ;
     RECT  22.633 45.552 22.777 47.112 ;
     RECT  21.604 16.656 22.805 17.064 ;
     RECT  21.604 10.272 22.813 10.296 ;
     RECT  22.025 32.544 22.813 32.568 ;
     RECT  22.169 58.128 22.813 58.152 ;
     RECT  21.604 19.392 22.817 19.416 ;
     RECT  21.953 26.4 22.817 29.112 ;
     RECT  21.604 37.584 22.849 43.32 ;
     RECT  22.813 9.888 22.853 10.296 ;
     RECT  22.849 37.584 22.853 43.56 ;
     RECT  22.777 45.552 22.853 47.88 ;
     RECT  22.805 16.656 22.885 17.16 ;
     RECT  22.211 67.872 22.892 67.896 ;
     RECT  22.853 45.552 22.925 45.576 ;
     RECT  22.133 59.712 22.925 59.736 ;
     RECT  22.133 64.416 22.925 64.44 ;
     RECT  21.604 2.88 22.961 3.72 ;
     RECT  22.892 67.68 22.979 67.896 ;
     RECT  22.817 27.264 22.993 29.112 ;
     RECT  22.499 6.672 22.997 8.472 ;
     RECT  22.853 46.56 22.997 47.88 ;
     RECT  22.997 6.672 23.027 7.416 ;
     RECT  22.853 9.888 23.027 9.912 ;
     RECT  22.669 13.968 23.029 14.184 ;
     RECT  22.885 16.512 23.029 17.352 ;
     RECT  22.709 33.936 23.029 35.832 ;
     RECT  21.989 49.776 23.029 51.144 ;
     RECT  22.025 31.152 23.101 31.464 ;
     RECT  22.813 32.544 23.101 32.616 ;
     RECT  22.097 56.064 23.125 56.088 ;
     RECT  22.813 57.6 23.125 58.152 ;
     RECT  23.029 49.488 23.137 51.144 ;
     RECT  22.097 52.224 23.137 54.792 ;
     RECT  23.101 31.104 23.209 32.616 ;
     RECT  23.125 55.872 23.209 58.152 ;
     RECT  23.209 30.336 23.221 32.616 ;
     RECT  23.029 33.6 23.221 35.832 ;
     RECT  21.604 62.544 23.221 62.568 ;
     RECT  23.029 13.632 23.324 14.184 ;
     RECT  22.993 27.264 23.353 29.256 ;
     RECT  23.221 30.336 23.353 35.832 ;
     RECT  23.324 13.632 23.425 14.424 ;
     RECT  23.065 12.528 23.605 12.552 ;
     RECT  23.425 13.584 23.605 14.424 ;
     RECT  23.029 19.872 23.785 19.896 ;
     RECT  22.853 37.584 23.785 38.232 ;
     RECT  21.604 60.816 23.852 60.84 ;
     RECT  23.209 55.872 23.893 58.68 ;
     RECT  23.852 60 23.893 60.84 ;
     RECT  23.365 64.944 24.001 64.968 ;
     RECT  22.961 2.976 24.008 3.72 ;
     RECT  23.027 6.672 24.008 6.696 ;
     RECT  22.997 8.4 24.008 8.472 ;
     RECT  23.605 12.528 24.008 14.424 ;
     RECT  23.029 15.792 24.008 17.352 ;
     RECT  23.785 19.536 24.008 19.896 ;
     RECT  22.777 23.664 24.008 24.408 ;
     RECT  23.713 25.44 24.008 25.464 ;
     RECT  23.353 27.264 24.008 35.832 ;
     RECT  23.785 37.008 24.008 38.232 ;
     RECT  22.853 39.216 24.008 43.56 ;
     RECT  23.749 44.928 24.008 44.952 ;
     RECT  22.997 47.136 24.008 47.88 ;
     RECT  23.137 49.488 24.008 54.792 ;
     RECT  23.893 55.872 24.008 60.84 ;
     RECT  23.221 61.872 24.008 62.568 ;
     RECT  23.533 63.6 24.008 63.624 ;
     RECT  24.001 64.656 24.008 64.968 ;
     RECT  22.597 66.192 24.008 66.216 ;
     RECT  22.979 67.872 24.008 67.896 ;
     RECT  22.933 68.976 24.008 69 ;
     RECT  23.137 70.368 24.008 70.392 ;
     RECT  23.641 71.712 24.008 71.736 ;
     RECT  24.008 2.148 24.112 75.612 ;
     RECT  24.112 2.418 24.304 75.342 ;
     RECT  24.304 8.448 24.365 9.336 ;
     RECT  24.304 40.368 24.419 57.432 ;
     RECT  24.304 12.912 24.581 13.608 ;
     RECT  24.304 59.184 24.581 59.208 ;
     RECT  24.304 18.768 24.617 19.848 ;
     RECT  24.304 10.368 24.653 10.728 ;
     RECT  24.304 61.008 24.689 61.032 ;
     RECT  24.304 3.36 24.761 4.584 ;
     RECT  24.304 23.376 24.797 34.2 ;
     RECT  24.419 45.456 24.803 57.432 ;
     RECT  24.761 3.36 24.905 3.816 ;
     RECT  24.365 8.64 24.977 9.336 ;
     RECT  24.581 12.912 25.049 12.936 ;
     RECT  24.304 62.496 25.049 68.52 ;
     RECT  25.049 64.416 25.085 68.52 ;
     RECT  24.304 16.992 25.091 17.448 ;
     RECT  24.797 23.376 25.121 24.504 ;
     RECT  24.797 25.488 25.139 34.2 ;
     RECT  24.419 40.368 25.139 44.472 ;
     RECT  24.803 45.456 25.139 54.744 ;
     RECT  25.121 24.48 25.165 24.504 ;
     RECT  25.139 44.448 25.18 44.472 ;
     RECT  25.139 45.456 25.193 50.136 ;
     RECT  24.304 70.128 25.228 72.936 ;
     RECT  24.977 9.12 25.229 9.336 ;
     RECT  25.193 45.456 25.229 47.112 ;
     RECT  24.304 21.12 25.265 21.432 ;
     RECT  24.304 35.328 25.265 37.032 ;
     RECT  24.304 38.112 25.297 39.384 ;
     RECT  25.139 40.368 25.297 43.128 ;
     RECT  25.228 72.384 25.297 72.936 ;
     RECT  25.139 51.744 25.301 54.744 ;
     RECT  25.229 9.312 25.409 9.336 ;
     RECT  25.139 33.264 25.441 34.2 ;
     RECT  25.265 35.328 25.441 35.352 ;
     RECT  25.265 36.48 25.441 37.032 ;
     RECT  25.297 38.112 25.441 43.128 ;
     RECT  25.265 21.12 25.445 21.384 ;
     RECT  25.085 64.656 25.523 68.52 ;
     RECT  25.121 23.376 25.549 23.4 ;
     RECT  25.333 59.424 25.58 59.448 ;
     RECT  25.193 48.192 25.589 50.136 ;
     RECT  25.297 72.384 25.697 73.416 ;
     RECT  25.58 58.656 25.717 59.448 ;
     RECT  25.139 25.488 25.733 32.28 ;
     RECT  24.803 55.92 25.801 57.432 ;
     RECT  24.304 6.672 25.945 6.84 ;
     RECT  25.621 21.024 25.945 21.048 ;
     RECT  25.549 22.896 26.053 23.4 ;
     RECT  24.617 18.768 26.089 19.32 ;
     RECT  25.945 20.976 26.089 21.048 ;
     RECT  25.229 45.456 26.089 46.92 ;
     RECT  25.717 58.56 26.089 59.448 ;
     RECT  25.765 15.696 26.125 15.72 ;
     RECT  25.091 17.088 26.125 17.448 ;
     RECT  26.089 18.768 26.197 21.048 ;
     RECT  26.089 45.024 26.197 46.92 ;
     RECT  25.049 62.496 26.197 62.856 ;
     RECT  25.228 70.128 26.233 71.208 ;
     RECT  25.801 55.728 26.269 57.432 ;
     RECT  26.089 58.56 26.269 59.592 ;
     RECT  25.333 11.52 26.341 11.544 ;
     RECT  25.523 64.656 26.369 65.112 ;
     RECT  25.523 66.144 26.377 68.52 ;
     RECT  26.377 66.144 26.557 68.664 ;
     RECT  25.301 51.744 26.581 52.44 ;
     RECT  25.301 53.52 26.581 54.744 ;
     RECT  26.557 66.144 26.581 68.808 ;
     RECT  26.341 11.52 26.593 12.36 ;
     RECT  25.733 25.488 26.593 25.512 ;
     RECT  26.125 15.696 26.629 17.448 ;
     RECT  26.197 18.432 26.629 21.048 ;
     RECT  25.589 48.192 26.665 48.552 ;
     RECT  25.589 49.728 26.665 50.136 ;
     RECT  24.905 3.36 26.708 3.72 ;
     RECT  25.945 6.24 26.708 6.84 ;
     RECT  25.549 7.872 26.708 7.896 ;
     RECT  26.485 9.6 26.708 9.624 ;
     RECT  26.593 11.52 26.708 12.504 ;
     RECT  26.629 15.696 26.708 21.048 ;
     RECT  26.053 22.752 26.708 23.4 ;
     RECT  26.593 24.912 26.708 25.512 ;
     RECT  25.733 26.784 26.708 32.28 ;
     RECT  25.441 33.264 26.708 35.352 ;
     RECT  25.441 36.48 26.708 43.128 ;
     RECT  26.197 44.208 26.708 46.92 ;
     RECT  26.665 48.192 26.708 50.136 ;
     RECT  26.581 51.744 26.708 54.744 ;
     RECT  26.269 55.728 26.708 59.592 ;
     RECT  26.089 60.816 26.708 60.84 ;
     RECT  26.197 62.448 26.708 62.856 ;
     RECT  26.369 64.416 26.708 65.112 ;
     RECT  26.581 66.144 26.708 68.904 ;
     RECT  26.233 69.984 26.708 71.208 ;
     RECT  25.697 72.864 26.708 73.416 ;
     RECT  25.669 74.592 26.708 74.616 ;
     RECT  26.708 2.148 26.812 75.612 ;
     RECT  26.812 2.418 27.004 75.342 ;
     RECT  27.004 56.544 27.065 58.152 ;
     RECT  27.004 40.32 27.101 43.32 ;
     RECT  27.004 74.592 27.101 74.664 ;
     RECT  27.004 36.528 27.209 38.232 ;
     RECT  27.065 57.648 27.245 58.152 ;
     RECT  27.004 53.52 27.281 54.168 ;
     RECT  27.209 36.528 27.317 37.128 ;
     RECT  27.101 40.416 27.347 43.32 ;
     RECT  27.004 65.328 27.347 68.232 ;
     RECT  27.347 66.432 27.353 68.232 ;
     RECT  27.101 74.592 27.389 74.616 ;
     RECT  27.004 48.192 27.587 52.488 ;
     RECT  27.004 59.184 27.628 61.608 ;
     RECT  27.004 69.504 27.676 71.208 ;
     RECT  27.004 14.832 27.677 14.856 ;
     RECT  27.347 40.464 27.779 43.32 ;
     RECT  27.004 44.304 27.827 47.112 ;
     RECT  27.628 59.184 27.893 61.416 ;
     RECT  27.827 45.216 27.923 47.112 ;
     RECT  27.587 49.488 27.923 52.488 ;
     RECT  27.004 12.24 27.929 13.08 ;
     RECT  27.004 72.528 27.965 73.416 ;
     RECT  27.004 3.408 28.037 3.864 ;
     RECT  27.004 20.352 28.073 20.376 ;
     RECT  27.004 23.376 28.141 23.928 ;
     RECT  27.004 62.976 28.177 63.864 ;
     RECT  27.347 65.328 28.177 65.448 ;
     RECT  27.965 72.816 28.181 73.416 ;
     RECT  27.004 17.376 28.211 17.448 ;
     RECT  27.923 49.776 28.213 52.488 ;
     RECT  27.281 53.52 28.213 53.736 ;
     RECT  27.065 56.544 28.213 56.664 ;
     RECT  27.245 58.128 28.213 58.152 ;
     RECT  28.213 56.544 28.249 58.152 ;
     RECT  28.249 56.352 28.285 58.152 ;
     RECT  27.779 40.848 28.309 43.32 ;
     RECT  28.285 56.352 28.321 58.728 ;
     RECT  27.929 12.336 28.325 13.08 ;
     RECT  27.004 33.264 28.325 34.776 ;
     RECT  28.181 73.344 28.357 73.416 ;
     RECT  28.325 13.008 28.361 13.08 ;
     RECT  27.676 69.744 28.361 71.208 ;
     RECT  27.004 5.76 28.433 6.84 ;
     RECT  28.211 17.376 28.465 17.4 ;
     RECT  28.325 33.648 28.597 34.776 ;
     RECT  28.321 55.776 28.609 58.728 ;
     RECT  28.609 55.68 28.645 58.728 ;
     RECT  28.361 70.656 28.645 71.208 ;
     RECT  27.004 27.168 28.681 27.864 ;
     RECT  28.141 22.752 28.717 23.928 ;
     RECT  28.717 22.752 28.789 24.12 ;
     RECT  27.923 45.216 28.789 46.632 ;
     RECT  28.177 62.976 28.796 65.448 ;
     RECT  28.465 14.976 28.861 15 ;
     RECT  27.587 48.192 28.861 48.504 ;
     RECT  28.861 48.144 28.933 48.504 ;
     RECT  28.213 49.776 28.933 53.736 ;
     RECT  28.645 55.44 28.933 58.728 ;
     RECT  27.317 36.816 28.969 37.128 ;
     RECT  27.209 38.208 28.969 38.232 ;
     RECT  28.357 25.536 29.029 25.56 ;
     RECT  28.681 27.168 29.029 27.96 ;
     RECT  28.861 14.976 29.041 15.24 ;
     RECT  28.165 20.592 29.041 20.952 ;
     RECT  29.029 25.536 29.041 25.656 ;
     RECT  28.933 49.776 29.041 58.728 ;
     RECT  27.893 60 29.041 61.416 ;
     RECT  28.645 70.656 29.041 71.4 ;
     RECT  29.041 20.064 29.077 21.192 ;
     RECT  28.969 36.816 29.077 38.232 ;
     RECT  28.309 40.848 29.221 43.368 ;
     RECT  28.933 48.144 29.257 48.696 ;
     RECT  29.041 49.776 29.257 61.416 ;
     RECT  27.353 66.816 29.257 68.232 ;
     RECT  28.789 22.752 29.269 24.168 ;
     RECT  29.041 25.296 29.269 25.656 ;
     RECT  29.221 40.608 29.269 43.368 ;
     RECT  28.573 10.896 29.365 10.92 ;
     RECT  28.037 3.408 29.408 3.432 ;
     RECT  28.433 5.856 29.408 6.84 ;
     RECT  27.004 8.592 29.408 8.616 ;
     RECT  29.365 10.896 29.408 11.736 ;
     RECT  28.361 13.008 29.408 13.032 ;
     RECT  29.041 14.976 29.408 15.336 ;
     RECT  28.465 16.416 29.408 17.4 ;
     RECT  28.789 18.816 29.408 18.84 ;
     RECT  29.077 19.824 29.408 21.192 ;
     RECT  29.269 22.752 29.408 25.656 ;
     RECT  29.029 26.784 29.408 27.96 ;
     RECT  27.004 29.232 29.408 32.28 ;
     RECT  28.597 33.648 29.408 35.304 ;
     RECT  29.077 36.816 29.408 38.664 ;
     RECT  29.269 40.272 29.408 43.368 ;
     RECT  28.789 44.4 29.408 46.632 ;
     RECT  29.257 48.144 29.408 61.416 ;
     RECT  28.796 62.592 29.408 65.448 ;
     RECT  29.257 66.72 29.408 68.232 ;
     RECT  29.041 70.656 29.408 71.928 ;
     RECT  28.357 73.344 29.408 73.896 ;
     RECT  29.408 2.148 29.512 75.612 ;
     RECT  29.512 2.418 29.704 75.342 ;
     RECT  29.704 23.088 29.801 24.12 ;
     RECT  29.704 46.08 29.801 53.496 ;
     RECT  29.801 46.08 29.865 49.608 ;
     RECT  29.865 46.08 29.881 48.216 ;
     RECT  29.801 23.376 29.909 23.88 ;
     RECT  29.704 25.536 30.017 25.56 ;
     RECT  29.704 11.328 30.053 12.888 ;
     RECT  29.704 73.488 30.083 74.28 ;
     RECT  29.704 66.576 30.089 72.264 ;
     RECT  29.704 39.888 30.197 42.264 ;
     RECT  29.704 43.296 30.227 44.856 ;
     RECT  29.704 54.672 30.227 60.552 ;
     RECT  30.089 69.84 30.227 72.264 ;
     RECT  30.227 43.296 30.233 44.472 ;
     RECT  30.227 56.064 30.268 60.552 ;
     RECT  29.704 8.544 30.305 8.568 ;
     RECT  29.704 5.088 30.323 6.84 ;
     RECT  29.704 9.744 30.323 9.768 ;
     RECT  30.268 57.36 30.341 60.552 ;
     RECT  30.053 11.328 30.371 11.976 ;
     RECT  29.704 14.208 30.521 21.192 ;
     RECT  29.801 50.64 30.557 53.496 ;
     RECT  29.704 36.528 30.593 38.808 ;
     RECT  30.227 70.08 30.593 72.264 ;
     RECT  30.089 66.576 30.665 68.808 ;
     RECT  30.083 73.488 30.665 73.752 ;
     RECT  29.704 62.016 30.689 63.576 ;
     RECT  29.704 64.56 30.689 65.448 ;
     RECT  30.557 50.688 30.701 53.496 ;
     RECT  30.689 62.016 30.701 65.448 ;
     RECT  30.593 36.528 30.707 38.232 ;
     RECT  30.665 66.576 30.737 68.232 ;
     RECT  29.704 26.976 30.805 27.624 ;
     RECT  29.704 33.648 30.805 35.304 ;
     RECT  30.701 50.832 30.805 53.496 ;
     RECT  30.227 54.672 30.805 54.744 ;
     RECT  30.341 57.6 30.805 60.552 ;
     RECT  30.701 62.016 30.805 64.632 ;
     RECT  30.323 5.088 30.845 6.792 ;
     RECT  29.704 28.992 30.877 29.304 ;
     RECT  29.704 30.384 30.877 31.608 ;
     RECT  30.707 36.528 30.881 36.552 ;
     RECT  30.197 39.888 30.953 41.928 ;
     RECT  30.877 28.992 30.985 31.608 ;
     RECT  30.233 43.344 30.989 44.472 ;
     RECT  30.593 70.08 31.043 72.024 ;
     RECT  30.665 73.728 31.043 73.752 ;
     RECT  29.704 2.784 31.057 3.96 ;
     RECT  30.845 5.088 31.057 6.648 ;
     RECT  31.057 2.784 31.061 6.648 ;
     RECT  30.521 14.4 31.061 21.192 ;
     RECT  30.805 26.976 31.093 27.912 ;
     RECT  29.881 48.192 31.097 48.216 ;
     RECT  29.909 23.376 31.129 23.64 ;
     RECT  31.061 2.784 31.133 5.256 ;
     RECT  29.881 46.08 31.201 47.16 ;
     RECT  31.061 20.928 31.273 21.192 ;
     RECT  30.985 28.992 31.285 31.656 ;
     RECT  30.953 39.888 31.309 40.44 ;
     RECT  31.273 20.928 31.345 21.816 ;
     RECT  30.805 50.832 31.345 54.744 ;
     RECT  30.268 56.064 31.345 56.376 ;
     RECT  31.285 28.992 31.371 32.52 ;
     RECT  31.371 28.992 31.417 32.568 ;
     RECT  30.805 33.648 31.417 35.4 ;
     RECT  29.865 49.392 31.417 49.608 ;
     RECT  31.345 50.832 31.417 56.376 ;
     RECT  30.805 57.6 31.417 64.632 ;
     RECT  30.371 11.664 31.489 11.976 ;
     RECT  31.417 28.992 31.597 35.4 ;
     RECT  31.093 26.88 31.633 27.912 ;
     RECT  31.597 28.992 31.633 35.928 ;
     RECT  31.417 48.96 31.765 49.608 ;
     RECT  31.417 50.832 31.765 64.632 ;
     RECT  30.737 67.44 31.777 68.232 ;
     RECT  31.633 26.88 31.885 35.928 ;
     RECT  30.953 41.76 31.885 41.928 ;
     RECT  30.707 37.632 31.909 38.232 ;
     RECT  31.309 39.216 31.909 40.44 ;
     RECT  31.777 66.864 31.909 68.232 ;
     RECT  31.1 8.784 31.921 8.808 ;
     RECT  31.489 11.664 31.993 12.552 ;
     RECT  31.345 20.928 31.993 22.008 ;
     RECT  31.129 23.376 31.993 24.456 ;
     RECT  31.777 65.76 32.101 65.784 ;
     RECT  31.909 66.864 32.101 68.952 ;
     RECT  31.133 2.784 32.108 2.808 ;
     RECT  31.133 4.224 32.108 5.256 ;
     RECT  31.061 6.624 32.108 6.648 ;
     RECT  31.921 8.544 32.108 8.808 ;
     RECT  31.993 11.136 32.108 12.552 ;
     RECT  31.061 14.736 32.108 19.608 ;
     RECT  31.993 20.928 32.108 24.456 ;
     RECT  31.885 26.784 32.108 35.928 ;
     RECT  31.909 37.632 32.108 40.44 ;
     RECT  31.885 41.76 32.108 42.216 ;
     RECT  30.989 43.344 32.108 43.368 ;
     RECT  30.989 44.352 32.108 44.472 ;
     RECT  31.201 46.08 32.108 47.304 ;
     RECT  31.765 48.96 32.108 64.632 ;
     RECT  32.101 65.76 32.108 68.952 ;
     RECT  31.043 70.08 32.108 70.872 ;
     RECT  31.043 72 32.108 72.024 ;
     RECT  32.108 2.148 32.212 75.612 ;
     RECT  32.212 2.418 32.404 75.342 ;
     RECT  32.404 46.08 32.465 47.16 ;
     RECT  32.404 56.496 32.465 72.984 ;
     RECT  32.465 56.496 32.501 60.024 ;
     RECT  32.404 22.752 32.531 24.696 ;
     RECT  32.531 22.848 32.545 24.696 ;
     RECT  32.404 25.68 32.545 44.472 ;
     RECT  32.545 25.68 32.579 25.704 ;
     RECT  32.545 26.784 32.581 44.472 ;
     RECT  32.545 22.848 32.609 23.928 ;
     RECT  32.465 61.152 32.609 71.352 ;
     RECT  32.581 26.784 32.627 40.392 ;
     RECT  32.609 61.152 32.825 61.416 ;
     RECT  32.825 61.2 32.861 61.416 ;
     RECT  32.404 8.544 32.897 14.952 ;
     RECT  32.627 33.264 32.915 40.392 ;
     RECT  32.404 20.928 32.963 21.144 ;
     RECT  32.404 6.624 33.005 7.416 ;
     RECT  32.609 23.136 33.107 23.928 ;
     RECT  33.005 7.056 33.113 7.416 ;
     RECT  32.581 41.664 33.113 44.472 ;
     RECT  32.897 11.664 33.12 14.952 ;
     RECT  33.12 14.352 33.149 14.952 ;
     RECT  32.609 62.544 33.221 71.352 ;
     RECT  32.897 8.544 33.257 10.2 ;
     RECT  32.915 33.264 33.257 36.6 ;
     RECT  33.221 62.544 33.257 64.824 ;
     RECT  33.257 34.656 33.293 36.6 ;
     RECT  33.12 11.664 33.329 13.128 ;
     RECT  33.113 7.152 33.365 7.416 ;
     RECT  33.329 13.008 33.437 13.128 ;
     RECT  32.404 16.848 33.469 16.872 ;
     RECT  32.465 72.672 33.473 72.984 ;
     RECT  32.404 5.568 33.509 5.592 ;
     RECT  33.257 8.544 33.509 9.912 ;
     RECT  32.465 46.272 33.577 47.16 ;
     RECT  32.627 26.784 33.613 32.232 ;
     RECT  33.509 9.888 33.617 9.912 ;
     RECT  32.915 37.824 33.637 40.392 ;
     RECT  32.404 18.96 33.689 19.368 ;
     RECT  33.113 43.872 33.757 44.472 ;
     RECT  33.577 45.6 33.761 47.16 ;
     RECT  33.149 14.352 33.797 14.808 ;
     RECT  33.221 66.48 33.827 71.352 ;
     RECT  33.107 23.568 33.829 23.928 ;
     RECT  32.404 48.24 33.829 50.664 ;
     RECT  33.257 63.264 33.833 64.824 ;
     RECT  32.404 3.456 33.865 3.48 ;
     RECT  33.829 47.424 33.901 50.664 ;
     RECT  32.404 51.792 33.901 55.08 ;
     RECT  33.901 47.424 33.937 55.08 ;
     RECT  33.937 47.424 33.973 55.464 ;
     RECT  32.501 56.88 34.009 60.024 ;
     RECT  32.861 61.2 34.009 61.368 ;
     RECT  33.293 34.752 34.021 36.6 ;
     RECT  33.637 37.824 34.021 40.44 ;
     RECT  33.613 26.784 34.045 32.568 ;
     RECT  33.973 47.424 34.045 55.56 ;
     RECT  34.009 56.88 34.045 61.368 ;
     RECT  33.329 11.664 34.153 11.976 ;
     RECT  33.797 14.688 34.153 14.808 ;
     RECT  34.045 26.592 34.153 32.568 ;
     RECT  33.113 41.664 34.213 42.744 ;
     RECT  33.757 43.872 34.213 44.52 ;
     RECT  33.689 19.056 34.225 19.368 ;
     RECT  33.925 20.976 34.225 21 ;
     RECT  33.833 63.36 34.261 64.824 ;
     RECT  33.827 66.48 34.261 69.048 ;
     RECT  34.213 41.664 34.297 44.52 ;
     RECT  34.045 47.424 34.297 61.368 ;
     RECT  34.021 34.752 34.333 40.44 ;
     RECT  33.829 23.568 34.369 23.976 ;
     RECT  34.153 26.544 34.369 32.568 ;
     RECT  33.509 8.544 34.477 8.712 ;
     RECT  34.369 23.28 34.508 23.976 ;
     RECT  33.473 72.672 34.585 72.696 ;
     RECT  33.827 70.08 34.621 71.352 ;
     RECT  34.153 14.688 34.693 15.528 ;
     RECT  33.469 16.656 34.693 16.872 ;
     RECT  34.369 25.728 34.693 32.568 ;
     RECT  34.333 33.84 34.693 40.44 ;
     RECT  34.153 11.184 34.729 11.976 ;
     RECT  33.865 3.456 34.808 3.912 ;
     RECT  33.365 7.392 34.808 7.416 ;
     RECT  34.477 8.544 34.808 9.336 ;
     RECT  34.729 10.992 34.808 11.976 ;
     RECT  33.437 13.008 34.808 13.032 ;
     RECT  34.693 14.688 34.808 17.064 ;
     RECT  34.225 19.056 34.808 19.848 ;
     RECT  34.225 20.976 34.808 21.432 ;
     RECT  34.508 22.656 34.808 23.976 ;
     RECT  34.693 25.728 34.808 40.44 ;
     RECT  34.297 41.616 34.808 44.52 ;
     RECT  33.761 45.6 34.808 46.296 ;
     RECT  34.297 47.424 34.808 62.04 ;
     RECT  34.261 63.36 34.808 69.048 ;
     RECT  34.621 70.08 34.808 71.4 ;
     RECT  34.585 72.528 34.808 72.696 ;
     RECT  34.513 74.064 34.808 74.088 ;
     RECT  34.808 2.148 34.912 75.612 ;
     RECT  34.912 2.418 35.104 75.342 ;
     RECT  35.104 50.304 35.129 53.064 ;
     RECT  35.104 5.328 35.219 5.544 ;
     RECT  35.104 8.448 35.219 9.528 ;
     RECT  35.104 32.88 35.219 43.032 ;
     RECT  35.104 44.112 35.273 49.08 ;
     RECT  35.104 70.08 35.309 71.4 ;
     RECT  35.104 22.8 35.345 23.928 ;
     RECT  35.104 25.2 35.345 29.064 ;
     RECT  35.104 54.096 35.345 58.68 ;
     RECT  35.104 66.768 35.345 66.936 ;
     RECT  35.104 61.536 35.356 63.336 ;
     RECT  35.104 10.896 35.381 12.504 ;
     RECT  35.104 30.096 35.381 31.416 ;
     RECT  35.356 61.536 35.381 62.664 ;
     RECT  35.104 6.816 35.417 6.84 ;
     RECT  35.273 49.056 35.417 49.08 ;
     RECT  35.104 14.112 35.424 21.672 ;
     RECT  35.345 25.2 35.459 26.808 ;
     RECT  35.104 3.408 35.633 4.2 ;
     RECT  35.381 10.992 35.633 12.504 ;
     RECT  35.633 3.408 35.741 3.96 ;
     RECT  35.104 72.528 35.777 74.088 ;
     RECT  35.273 44.112 35.795 47.928 ;
     RECT  35.424 14.112 35.813 19.416 ;
     RECT  35.813 14.112 35.849 16.152 ;
     RECT  35.104 64.32 35.885 64.92 ;
     RECT  35.741 3.408 35.921 3.672 ;
     RECT  35.219 34.08 35.957 43.032 ;
     RECT  35.345 27.84 35.993 29.064 ;
     RECT  35.219 32.88 36.085 33 ;
     RECT  35.381 30.192 36.137 31.416 ;
     RECT  35.381 62.16 36.137 62.664 ;
     RECT  35.129 50.304 36.169 52.776 ;
     RECT  36.085 32.448 36.181 33 ;
     RECT  35.777 72.528 36.209 74.04 ;
     RECT  36.169 50.16 36.229 52.776 ;
     RECT  36.229 49.872 36.241 52.776 ;
     RECT  35.345 54.096 36.241 57.576 ;
     RECT  35.885 64.32 36.241 64.344 ;
     RECT  35.219 8.448 36.281 9.336 ;
     RECT  35.424 20.592 36.313 21.672 ;
     RECT  35.459 25.2 36.323 26.76 ;
     RECT  35.993 27.84 36.323 28.248 ;
     RECT  36.313 20.592 36.325 22.152 ;
     RECT  35.345 23.136 36.325 23.928 ;
     RECT  35.957 34.8 36.385 43.032 ;
     RECT  35.795 44.112 36.385 45.48 ;
     RECT  36.325 20.592 36.421 23.928 ;
     RECT  35.219 5.52 36.457 5.544 ;
     RECT  36.137 30.72 36.457 31.416 ;
     RECT  36.181 32.448 36.457 33.048 ;
     RECT  35.104 68.928 36.493 68.952 ;
     RECT  36.209 72.528 36.493 72.936 ;
     RECT  36.493 68.208 36.497 68.952 ;
     RECT  36.137 62.544 36.529 62.664 ;
     RECT  36.241 63.936 36.529 64.344 ;
     RECT  35.921 3.408 36.533 3.576 ;
     RECT  36.493 72.384 36.533 72.936 ;
     RECT  36.457 5.52 36.601 5.832 ;
     RECT  35.345 58.656 36.673 58.68 ;
     RECT  35.104 60 36.673 60.408 ;
     RECT  35.633 11.328 36.709 12.504 ;
     RECT  36.241 49.872 36.716 57.576 ;
     RECT  36.673 58.656 36.716 60.408 ;
     RECT  35.849 14.544 36.817 16.152 ;
     RECT  35.813 17.184 36.817 19.416 ;
     RECT  36.385 34.8 36.889 45.48 ;
     RECT  35.795 46.512 36.889 47.928 ;
     RECT  36.817 14.544 36.901 19.416 ;
     RECT  36.889 34.8 36.925 47.928 ;
     RECT  36.097 67.008 36.997 67.032 ;
     RECT  35.309 70.08 36.997 71.352 ;
     RECT  36.533 72.384 36.997 72.408 ;
     RECT  36.716 49.872 37.105 60.408 ;
     RECT  36.277 7.152 37.141 7.176 ;
     RECT  36.901 14.544 37.177 19.608 ;
     RECT  36.421 20.592 37.177 24.12 ;
     RECT  36.709 11.136 37.285 12.504 ;
     RECT  37.285 11.136 37.321 13.128 ;
     RECT  37.177 14.544 37.321 24.12 ;
     RECT  36.323 28.176 37.465 28.248 ;
     RECT  36.533 3.408 37.508 3.48 ;
     RECT  36.601 5.136 37.508 5.832 ;
     RECT  37.141 7.152 37.508 7.416 ;
     RECT  36.281 8.448 37.508 8.52 ;
     RECT  37.329 9.504 37.508 9.528 ;
     RECT  37.321 11.136 37.508 24.12 ;
     RECT  36.323 25.2 37.508 26.568 ;
     RECT  37.465 28.176 37.508 29.256 ;
     RECT  36.457 30.72 37.508 33.048 ;
     RECT  36.925 34.416 37.508 47.928 ;
     RECT  37.105 49.776 37.508 60.408 ;
     RECT  36.529 62.544 37.508 64.344 ;
     RECT  36.997 66.48 37.508 67.032 ;
     RECT  36.497 68.208 37.508 68.232 ;
     RECT  36.997 70.08 37.508 72.408 ;
     RECT  36.209 74.016 37.508 74.04 ;
     RECT  37.508 2.148 37.612 75.612 ;
     RECT  37.612 2.418 37.804 75.342 ;
     RECT  37.804 15.312 37.829 25.56 ;
     RECT  37.804 41.568 37.901 51.912 ;
     RECT  37.804 62.544 37.901 64.104 ;
     RECT  37.804 5.76 37.955 6.024 ;
     RECT  37.901 62.688 37.955 64.104 ;
     RECT  37.804 28.176 37.973 40.488 ;
     RECT  37.804 68.208 37.973 68.232 ;
     RECT  37.804 11.856 38.099 14.184 ;
     RECT  37.804 59.856 38.189 61.368 ;
     RECT  37.829 15.312 38.243 20.328 ;
     RECT  37.804 66.48 38.261 66.504 ;
     RECT  38.243 15.696 38.297 20.328 ;
     RECT  37.901 43.248 38.333 51.912 ;
     RECT  38.333 43.248 38.369 49.56 ;
     RECT  37.804 57.408 38.369 57.432 ;
     RECT  38.333 50.688 38.405 51.912 ;
     RECT  37.973 28.368 38.477 40.488 ;
     RECT  38.405 50.688 38.513 51.336 ;
     RECT  37.804 4.512 38.549 4.536 ;
     RECT  38.477 30.192 38.549 40.488 ;
     RECT  38.369 43.296 38.621 43.32 ;
     RECT  37.804 70.176 38.657 70.296 ;
     RECT  38.369 44.352 38.665 49.56 ;
     RECT  38.549 35.28 38.675 40.488 ;
     RECT  38.549 30.192 38.693 34.248 ;
     RECT  37.804 53.04 38.729 55.272 ;
     RECT  38.099 12.48 38.771 14.184 ;
     RECT  38.729 53.04 38.771 54.744 ;
     RECT  37.804 7.392 38.773 7.992 ;
     RECT  37.804 26.544 38.797 26.952 ;
     RECT  37.901 41.568 38.797 42.264 ;
     RECT  38.477 28.368 38.801 29.208 ;
     RECT  37.804 56.352 38.801 56.376 ;
     RECT  38.189 59.856 38.801 60.456 ;
     RECT  38.773 7.392 38.819 8.04 ;
     RECT  37.804 65.328 38.821 65.352 ;
     RECT  37.804 72 38.828 72.024 ;
     RECT  37.804 9.504 38.837 9.528 ;
     RECT  38.819 8.016 38.86 8.04 ;
     RECT  38.828 71.808 38.861 72.024 ;
     RECT  37.955 62.688 38.867 63.672 ;
     RECT  38.821 64.944 38.867 65.352 ;
     RECT  38.801 59.856 38.869 59.88 ;
     RECT  38.513 51.12 38.873 51.336 ;
     RECT  38.867 64.944 38.908 64.968 ;
     RECT  38.869 59.232 38.915 59.88 ;
     RECT  38.657 70.176 38.915 70.2 ;
     RECT  38.861 71.808 38.915 72.984 ;
     RECT  38.297 15.696 38.945 17.88 ;
     RECT  38.797 41.04 38.945 42.264 ;
     RECT  38.665 46.752 38.945 49.56 ;
     RECT  38.915 72.96 38.945 72.984 ;
     RECT  38.915 59.232 38.956 59.256 ;
     RECT  38.675 35.28 38.981 39.96 ;
     RECT  38.945 46.752 39.011 49.032 ;
     RECT  38.981 35.28 39.017 38.232 ;
     RECT  39.011 47.328 39.1 49.032 ;
     RECT  39.02 9.648 39.107 9.672 ;
     RECT  39.017 35.28 39.125 35.352 ;
     RECT  38.665 44.352 39.125 45.672 ;
     RECT  39.1 49.008 39.133 49.032 ;
     RECT  38.873 51.168 39.153 51.336 ;
     RECT  38.771 53.04 39.221 54.36 ;
     RECT  38.771 12.48 39.233 12.504 ;
     RECT  37.829 21.504 39.445 25.56 ;
     RECT  38.797 26.544 39.445 27.144 ;
     RECT  38.945 16.08 39.625 17.88 ;
     RECT  38.297 19.248 39.625 20.328 ;
     RECT  38.945 41.232 39.692 42.264 ;
     RECT  38.693 31.872 39.733 34.248 ;
     RECT  39.125 35.28 39.733 35.304 ;
     RECT  37.955 6 40.208 6.024 ;
     RECT  37.804 10.704 40.208 10.728 ;
     RECT  38.771 13.632 40.208 14.184 ;
     RECT  39.625 16.08 40.208 20.328 ;
     RECT  39.445 21.504 40.208 27.144 ;
     RECT  38.801 28.368 40.208 29.112 ;
     RECT  38.693 30.192 40.208 30.792 ;
     RECT  39.733 31.872 40.208 35.304 ;
     RECT  39.017 36.48 40.208 38.232 ;
     RECT  38.981 39.264 40.208 39.96 ;
     RECT  39.692 41.232 40.208 42.36 ;
     RECT  39.125 44.352 40.208 45.192 ;
     RECT  39.1 47.328 40.208 47.976 ;
     RECT  39.153 51.312 40.208 51.336 ;
     RECT  39.221 52.464 40.208 54.36 ;
     RECT  40.208 2.148 40.312 75.612 ;
     RECT  40.312 2.418 40.504 75.342 ;
     RECT  40.504 8.88 41.569 8.904 ;
     RECT  40.504 55.632 41.569 55.656 ;
     RECT  40.504 57.216 41.569 57.24 ;
     RECT  40.504 59.328 41.569 59.352 ;
     RECT  40.504 70.944 41.569 70.968 ;
     RECT  41.569 46.128 41.605 47.736 ;
     RECT  41.569 48.768 41.605 48.792 ;
     RECT  41.569 4.656 41.821 5.208 ;
     RECT  41.569 8.352 41.821 8.904 ;
     RECT  41.605 9.936 41.821 9.96 ;
     RECT  41.569 15.216 41.821 15.24 ;
     RECT  41.569 16.272 41.821 17.88 ;
     RECT  41.569 19.968 41.821 19.992 ;
     RECT  41.569 51.408 41.821 51.96 ;
     RECT  41.569 60.384 41.821 60.408 ;
     RECT  41.569 61.44 41.821 62.52 ;
     RECT  41.569 65.664 41.821 67.272 ;
     RECT  41.569 70.416 41.821 70.968 ;
     RECT  41.569 72 41.821 72.552 ;
     RECT  41.569 18.912 41.893 18.936 ;
     RECT  41.821 19.968 41.893 20.52 ;
     RECT  41.569 24.192 41.893 24.216 ;
     RECT  41.605 25.248 41.893 25.272 ;
     RECT  41.605 46.128 41.893 48.792 ;
     RECT  41.569 54.576 41.893 54.6 ;
     RECT  41.569 55.632 41.893 59.352 ;
     RECT  41.821 60.384 41.893 63.048 ;
     RECT  41.821 65.136 41.893 67.8 ;
     RECT  41.569 68.832 41.893 69.384 ;
     RECT  41.821 70.416 41.893 72.552 ;
     RECT  41.569 73.584 41.893 73.608 ;
     RECT  41.821 4.656 42.145 5.736 ;
     RECT  41.569 7.296 42.145 7.32 ;
     RECT  41.821 8.352 42.145 9.96 ;
     RECT  40.504 11.52 42.145 11.544 ;
     RECT  41.821 14.16 42.145 14.184 ;
     RECT  41.821 15.216 42.145 17.88 ;
     RECT  41.893 18.912 42.145 20.52 ;
     RECT  41.893 24.192 42.145 25.272 ;
     RECT  41.569 26.832 42.145 26.856 ;
     RECT  41.569 27.888 42.145 27.912 ;
     RECT  41.569 28.944 42.145 28.968 ;
     RECT  40.504 30 42.145 30.024 ;
     RECT  41.893 31.056 42.145 31.08 ;
     RECT  41.569 32.64 42.145 32.664 ;
     RECT  41.893 33.696 42.145 34.776 ;
     RECT  41.569 36.336 42.145 36.36 ;
     RECT  41.569 41.904 42.145 42.984 ;
     RECT  41.569 44.016 42.145 44.04 ;
     RECT  41.893 45.072 42.145 48.792 ;
     RECT  41.569 49.824 42.145 50.376 ;
     RECT  41.821 51.408 42.145 52.488 ;
     RECT  41.569 53.52 42.145 53.544 ;
     RECT  41.893 54.576 42.145 63.048 ;
     RECT  40.504 64.08 42.145 64.104 ;
     RECT  41.893 65.136 42.145 69.384 ;
     RECT  41.893 70.416 42.145 73.608 ;
     RECT  42.145 3.6 42.181 20.52 ;
     RECT  42.145 21.552 42.181 36.36 ;
     RECT  40.504 38.208 43.081 38.232 ;
     RECT  42.181 3.6 43.116 3.624 ;
     RECT  42.181 3.624 43.164 4.128 ;
     RECT  42.181 4.128 43.116 4.152 ;
     RECT  42.181 4.152 43.164 4.656 ;
     RECT  42.181 4.656 43.116 4.68 ;
     RECT  42.181 4.68 43.164 5.184 ;
     RECT  42.181 5.184 43.116 5.208 ;
     RECT  42.181 5.208 43.164 5.712 ;
     RECT  42.181 5.712 43.116 5.736 ;
     RECT  42.181 5.736 43.164 6.24 ;
     RECT  42.181 6.24 43.116 6.264 ;
     RECT  42.181 6.264 43.164 6.768 ;
     RECT  42.181 6.768 43.116 6.792 ;
     RECT  42.181 6.792 43.164 7.296 ;
     RECT  42.181 7.296 43.116 7.32 ;
     RECT  42.181 7.32 43.164 7.824 ;
     RECT  42.181 7.824 43.116 7.848 ;
     RECT  42.181 7.848 43.164 8.352 ;
     RECT  42.181 8.352 43.116 8.376 ;
     RECT  42.181 8.376 43.164 8.88 ;
     RECT  42.181 8.88 43.116 8.904 ;
     RECT  42.181 8.904 43.164 9.408 ;
     RECT  42.181 9.408 43.116 9.432 ;
     RECT  42.181 9.432 43.164 9.936 ;
     RECT  42.181 9.936 43.116 9.96 ;
     RECT  42.181 9.96 43.164 10.464 ;
     RECT  42.181 10.464 43.116 10.488 ;
     RECT  42.181 10.488 43.164 10.992 ;
     RECT  42.181 10.992 43.116 11.016 ;
     RECT  42.181 11.016 43.164 11.52 ;
     RECT  42.181 11.52 43.116 11.544 ;
     RECT  42.181 11.544 43.164 12.048 ;
     RECT  42.181 12.048 43.116 12.072 ;
     RECT  42.181 12.072 43.164 12.576 ;
     RECT  42.181 12.576 43.116 12.6 ;
     RECT  42.181 12.6 43.164 13.104 ;
     RECT  42.181 13.104 43.116 13.128 ;
     RECT  42.181 13.128 43.164 13.632 ;
     RECT  42.181 13.632 43.116 13.656 ;
     RECT  42.181 13.656 43.164 14.16 ;
     RECT  42.181 14.16 43.116 14.184 ;
     RECT  42.181 14.184 43.164 14.688 ;
     RECT  42.181 14.688 43.116 14.712 ;
     RECT  42.181 14.712 43.164 15.216 ;
     RECT  42.181 15.216 43.116 15.24 ;
     RECT  42.181 15.24 43.164 15.744 ;
     RECT  42.181 15.744 43.116 15.768 ;
     RECT  42.181 15.768 43.164 16.272 ;
     RECT  42.181 16.272 43.116 16.296 ;
     RECT  42.181 16.296 43.164 16.8 ;
     RECT  42.181 16.8 43.116 16.824 ;
     RECT  42.181 16.824 43.164 17.328 ;
     RECT  42.181 17.328 43.116 17.352 ;
     RECT  42.181 17.352 43.164 17.856 ;
     RECT  42.181 17.856 43.116 17.88 ;
     RECT  42.181 17.88 43.164 18.384 ;
     RECT  42.181 18.384 43.116 18.408 ;
     RECT  42.181 18.408 43.164 18.912 ;
     RECT  42.181 18.912 43.116 18.936 ;
     RECT  42.181 18.936 43.164 19.44 ;
     RECT  42.181 19.44 43.116 19.464 ;
     RECT  42.181 19.464 43.164 19.968 ;
     RECT  42.181 19.968 43.116 19.992 ;
     RECT  42.181 19.992 43.164 20.496 ;
     RECT  42.181 20.496 43.116 20.52 ;
     RECT  42.181 20.52 43.164 21.024 ;
     RECT  42.181 21.024 43.116 21.048 ;
     RECT  42.181 21.048 43.164 21.552 ;
     RECT  42.181 21.552 43.116 21.576 ;
     RECT  42.181 21.576 43.164 22.08 ;
     RECT  42.181 22.08 43.116 22.104 ;
     RECT  42.181 22.104 43.164 22.608 ;
     RECT  42.181 22.608 43.116 22.632 ;
     RECT  42.181 22.632 43.164 23.136 ;
     RECT  42.181 23.136 43.116 23.16 ;
     RECT  42.181 23.16 43.164 23.664 ;
     RECT  42.181 23.664 43.116 23.688 ;
     RECT  42.181 23.688 43.164 24.192 ;
     RECT  42.181 24.192 43.116 24.216 ;
     RECT  42.181 24.216 43.164 24.72 ;
     RECT  42.181 24.72 43.116 24.744 ;
     RECT  42.181 24.744 43.164 25.248 ;
     RECT  42.181 25.248 43.116 25.272 ;
     RECT  42.181 25.272 43.164 25.776 ;
     RECT  42.181 25.776 43.116 25.8 ;
     RECT  42.181 25.8 43.164 26.304 ;
     RECT  42.181 26.304 43.116 26.328 ;
     RECT  42.181 26.328 43.164 26.832 ;
     RECT  42.181 26.832 43.116 26.856 ;
     RECT  42.181 26.856 43.164 27.36 ;
     RECT  42.181 27.36 43.116 27.384 ;
     RECT  42.181 27.384 43.164 27.888 ;
     RECT  42.181 27.888 43.116 27.912 ;
     RECT  42.181 27.912 43.164 28.416 ;
     RECT  42.181 28.416 43.116 28.44 ;
     RECT  42.181 28.44 43.164 28.944 ;
     RECT  42.181 28.944 43.116 28.968 ;
     RECT  42.181 28.968 43.164 29.472 ;
     RECT  42.181 29.472 43.116 29.496 ;
     RECT  42.181 29.496 43.164 30 ;
     RECT  42.181 30 43.116 30.024 ;
     RECT  42.181 30.024 43.164 30.528 ;
     RECT  42.181 30.528 43.116 30.552 ;
     RECT  42.181 30.552 43.164 31.056 ;
     RECT  42.181 31.056 43.116 31.08 ;
     RECT  42.181 31.08 43.164 31.584 ;
     RECT  42.181 31.584 43.116 31.608 ;
     RECT  42.181 31.608 43.164 32.112 ;
     RECT  42.181 32.112 43.116 32.136 ;
     RECT  42.181 32.136 43.164 32.64 ;
     RECT  42.181 32.64 43.116 32.664 ;
     RECT  42.181 32.664 43.164 33.168 ;
     RECT  42.181 33.168 43.116 33.192 ;
     RECT  42.181 33.192 43.164 33.696 ;
     RECT  42.181 33.696 43.116 33.72 ;
     RECT  42.181 33.72 43.164 34.224 ;
     RECT  42.181 34.224 43.116 34.248 ;
     RECT  42.181 34.248 43.164 34.752 ;
     RECT  42.181 34.752 43.116 34.776 ;
     RECT  42.181 34.776 43.164 35.28 ;
     RECT  42.181 35.28 43.116 35.304 ;
     RECT  42.181 35.304 43.164 35.808 ;
     RECT  42.181 35.808 43.116 35.832 ;
     RECT  42.181 35.832 43.164 36.336 ;
     RECT  42.181 36.336 43.116 36.36 ;
     RECT  42.145 41.376 43.116 41.4 ;
     RECT  42.145 41.4 43.164 41.904 ;
     RECT  42.145 41.904 43.116 41.928 ;
     RECT  42.145 41.928 43.164 42.432 ;
     RECT  42.145 42.432 43.116 42.456 ;
     RECT  42.145 42.456 43.164 42.96 ;
     RECT  42.145 42.96 43.116 42.984 ;
     RECT  42.145 42.984 43.164 43.488 ;
     RECT  42.145 43.488 43.116 43.512 ;
     RECT  42.145 43.512 43.164 44.016 ;
     RECT  42.145 44.016 43.116 44.04 ;
     RECT  42.145 44.04 43.164 44.544 ;
     RECT  42.145 44.544 43.116 44.568 ;
     RECT  42.145 44.568 43.164 45.072 ;
     RECT  42.145 45.072 43.116 45.096 ;
     RECT  42.145 45.096 43.164 45.6 ;
     RECT  42.145 45.6 43.116 45.624 ;
     RECT  42.145 45.624 43.164 46.128 ;
     RECT  42.145 46.128 43.116 46.152 ;
     RECT  42.145 46.152 43.164 46.656 ;
     RECT  42.145 46.656 43.116 46.68 ;
     RECT  42.145 46.68 43.164 47.184 ;
     RECT  42.145 47.184 43.116 47.208 ;
     RECT  42.145 47.208 43.164 47.712 ;
     RECT  42.145 47.712 43.116 47.736 ;
     RECT  42.145 47.736 43.164 48.24 ;
     RECT  42.145 48.24 43.116 48.264 ;
     RECT  42.145 48.264 43.164 48.768 ;
     RECT  42.145 48.768 43.116 48.792 ;
     RECT  42.145 48.792 43.164 49.296 ;
     RECT  42.145 49.296 43.116 49.32 ;
     RECT  42.145 49.32 43.164 49.824 ;
     RECT  42.145 49.824 43.116 49.848 ;
     RECT  42.145 49.848 43.164 50.352 ;
     RECT  42.145 50.352 43.116 50.376 ;
     RECT  42.145 50.376 43.164 50.88 ;
     RECT  42.145 50.88 43.116 50.904 ;
     RECT  42.145 50.904 43.164 51.408 ;
     RECT  42.145 51.408 43.116 51.432 ;
     RECT  42.145 51.432 43.164 51.936 ;
     RECT  42.145 51.936 43.116 51.96 ;
     RECT  42.145 51.96 43.164 52.464 ;
     RECT  42.145 52.464 43.116 52.488 ;
     RECT  42.145 52.488 43.164 52.992 ;
     RECT  42.145 52.992 43.116 53.016 ;
     RECT  42.145 53.016 43.164 53.52 ;
     RECT  42.145 53.52 43.116 53.544 ;
     RECT  42.145 53.544 43.164 54.048 ;
     RECT  42.145 54.048 43.116 54.072 ;
     RECT  42.145 54.072 43.164 54.576 ;
     RECT  42.145 54.576 43.116 54.6 ;
     RECT  42.145 54.6 43.164 55.104 ;
     RECT  42.145 55.104 43.116 55.128 ;
     RECT  42.145 55.128 43.164 55.632 ;
     RECT  42.145 55.632 43.116 55.656 ;
     RECT  42.145 55.656 43.164 56.16 ;
     RECT  42.145 56.16 43.116 56.184 ;
     RECT  42.145 56.184 43.164 56.688 ;
     RECT  42.145 56.688 43.116 56.712 ;
     RECT  42.145 56.712 43.164 57.216 ;
     RECT  42.145 57.216 43.116 57.24 ;
     RECT  42.145 57.24 43.164 57.744 ;
     RECT  42.145 57.744 43.116 57.768 ;
     RECT  42.145 57.768 43.164 58.272 ;
     RECT  42.145 58.272 43.116 58.296 ;
     RECT  42.145 58.296 43.164 58.8 ;
     RECT  42.145 58.8 43.116 58.824 ;
     RECT  42.145 58.824 43.164 59.328 ;
     RECT  42.145 59.328 43.116 59.352 ;
     RECT  42.145 59.352 43.164 59.856 ;
     RECT  42.145 59.856 43.116 59.88 ;
     RECT  42.145 59.88 43.164 60.384 ;
     RECT  42.145 60.384 43.116 60.408 ;
     RECT  42.145 60.408 43.164 60.912 ;
     RECT  42.145 60.912 43.116 60.936 ;
     RECT  42.145 60.936 43.164 61.44 ;
     RECT  42.145 61.44 43.116 61.464 ;
     RECT  42.145 61.464 43.164 61.968 ;
     RECT  42.145 61.968 43.116 61.992 ;
     RECT  42.145 61.992 43.164 62.496 ;
     RECT  42.145 62.496 43.116 62.52 ;
     RECT  42.145 62.52 43.164 63.024 ;
     RECT  42.145 63.024 43.116 63.048 ;
     RECT  42.145 63.048 43.164 63.552 ;
     RECT  42.145 63.552 43.116 63.576 ;
     RECT  42.145 63.576 43.164 64.08 ;
     RECT  42.145 64.08 43.116 64.104 ;
     RECT  42.145 64.104 43.164 64.608 ;
     RECT  42.145 64.608 43.116 64.632 ;
     RECT  42.145 64.632 43.164 65.136 ;
     RECT  42.145 65.136 43.116 65.16 ;
     RECT  42.145 65.16 43.164 65.664 ;
     RECT  42.145 65.664 43.116 65.688 ;
     RECT  42.145 65.688 43.164 66.192 ;
     RECT  42.145 66.192 43.116 66.216 ;
     RECT  42.145 66.216 43.164 66.72 ;
     RECT  42.145 66.72 43.116 66.744 ;
     RECT  42.145 66.744 43.164 67.248 ;
     RECT  42.145 67.248 43.116 67.272 ;
     RECT  42.145 67.272 43.164 67.776 ;
     RECT  42.145 67.776 43.116 67.8 ;
     RECT  42.145 67.8 43.164 68.304 ;
     RECT  42.145 68.304 43.116 68.328 ;
     RECT  42.145 68.328 43.164 68.832 ;
     RECT  42.145 68.832 43.116 68.856 ;
     RECT  42.145 68.856 43.164 69.36 ;
     RECT  42.145 69.36 43.116 69.384 ;
     RECT  42.145 69.384 43.164 69.888 ;
     RECT  42.145 69.888 43.116 69.912 ;
     RECT  42.145 69.912 43.164 70.416 ;
     RECT  42.145 70.416 43.116 70.44 ;
     RECT  42.145 70.44 43.164 70.944 ;
     RECT  42.145 70.944 43.116 70.968 ;
     RECT  42.145 70.968 43.164 71.472 ;
     RECT  42.145 71.472 43.116 71.496 ;
     RECT  42.145 71.496 43.164 72 ;
     RECT  42.145 72 43.116 72.024 ;
     RECT  42.145 72.024 43.164 72.528 ;
     RECT  42.145 72.528 43.116 72.552 ;
     RECT  42.145 72.552 43.164 73.056 ;
     RECT  42.145 73.056 43.116 73.08 ;
     RECT  42.145 73.08 43.164 73.584 ;
     RECT  42.145 73.584 43.116 73.608 ;
     RECT  42.145 73.608 43.164 74.112 ;
     RECT  42.145 74.112 43.116 74.136 ;
    LAYER M5 ;
     RECT  6.456 0.016 6.528 0.084 ;
     RECT  6.552 0.016 6.624 0.084 ;
     RECT  6.648 0.016 6.72 0.084 ;
     RECT  6.744 0.016 6.816 0.084 ;
     RECT  6.84 0.016 6.912 0.084 ;
     RECT  6.936 0.016 7.008 0.084 ;
     RECT  7.032 0.016 7.104 0.084 ;
     RECT  7.128 0.016 7.2 0.084 ;
     RECT  7.224 0.016 7.296 0.084 ;
     RECT  7.32 0.016 7.392 0.084 ;
     RECT  7.416 0.016 7.488 0.084 ;
     RECT  7.512 0.016 7.584 0.084 ;
     RECT  7.608 0.016 7.68 0.084 ;
     RECT  7.704 0.016 7.776 0.084 ;
     RECT  7.8 0.016 7.872 0.084 ;
     RECT  7.896 0.016 7.968 0.084 ;
     RECT  7.992 0.016 8.064 0.084 ;
     RECT  8.088 0.016 8.16 0.084 ;
     RECT  8.184 0.016 8.256 0.084 ;
     RECT  8.28 0.016 8.352 0.084 ;
     RECT  8.376 0.016 8.448 0.084 ;
     RECT  8.472 0.016 8.544 0.084 ;
     RECT  8.568 0.016 8.64 0.084 ;
     RECT  8.664 0.016 8.736 0.084 ;
     RECT  8.76 0.016 8.832 0.084 ;
     RECT  8.856 0.016 8.928 0.084 ;
     RECT  8.952 0.016 9.024 0.084 ;
     RECT  9.048 0.016 9.12 0.084 ;
     RECT  9.144 0.016 9.216 0.084 ;
     RECT  9.24 0.016 9.312 0.084 ;
     RECT  9.336 0.016 9.408 0.084 ;
     RECT  9.432 0.016 9.504 0.084 ;
     RECT  9.528 0.016 9.6 0.084 ;
     RECT  9.624 0.016 9.696 0.084 ;
     RECT  9.72 0.016 9.792 0.084 ;
     RECT  9.816 0.016 9.888 0.084 ;
     RECT  9.912 0.016 9.984 0.084 ;
     RECT  10.008 0.016 10.08 0.084 ;
     RECT  10.104 0.016 10.176 0.084 ;
     RECT  10.2 0.016 10.272 0.084 ;
     RECT  10.296 0.016 10.368 0.084 ;
     RECT  10.392 0.016 10.464 0.084 ;
     RECT  10.488 0.016 10.56 0.084 ;
     RECT  10.584 0.016 10.656 0.084 ;
     RECT  10.68 0.016 10.752 0.084 ;
     RECT  10.776 0.016 10.848 0.084 ;
     RECT  10.872 0.016 10.944 0.084 ;
     RECT  10.968 0.016 11.04 0.084 ;
     RECT  11.064 0.016 11.136 0.084 ;
     RECT  11.16 0.016 11.232 0.084 ;
     RECT  11.256 0.016 11.328 0.084 ;
     RECT  11.352 0.016 11.424 0.084 ;
     RECT  11.448 0.016 11.52 0.084 ;
     RECT  11.544 0.016 11.616 0.084 ;
     RECT  11.64 0.016 11.712 0.084 ;
     RECT  11.736 0.016 11.808 0.084 ;
     RECT  11.832 0.016 11.904 0.084 ;
     RECT  11.928 0.016 12 0.084 ;
     RECT  12.024 0.016 12.096 0.084 ;
     RECT  12.12 0.016 12.192 0.084 ;
     RECT  12.216 0.016 12.288 0.084 ;
     RECT  12.312 0.016 12.384 0.084 ;
     RECT  12.408 0.016 12.48 0.084 ;
     RECT  12.504 0.016 12.576 0.084 ;
     RECT  12.6 0.016 12.672 0.084 ;
     RECT  6.432 0.084 12.696 0.229 ;
     RECT  6.432 0.229 13.128 0.563 ;
     RECT  6.624 0.563 13.128 2.137 ;
     RECT  2.4 2.137 2.52 2.151 ;
     RECT  5.1 2.137 5.22 2.151 ;
     RECT  6.624 2.137 13.32 2.151 ;
     RECT  15.9 2.137 16.02 2.151 ;
     RECT  18.6 2.137 18.72 2.151 ;
     RECT  21.3 2.137 21.576 2.151 ;
     RECT  24 2.137 24.12 2.151 ;
     RECT  26.7 2.137 26.82 2.151 ;
     RECT  29.4 2.137 29.52 2.151 ;
     RECT  32.1 2.137 32.22 2.151 ;
     RECT  34.8 2.137 34.92 2.151 ;
     RECT  37.5 2.137 37.62 2.151 ;
     RECT  40.2 2.137 40.32 2.151 ;
     RECT  6.624 2.151 13.512 2.339 ;
     RECT  29.4 2.151 29.712 2.821 ;
     RECT  24 2.151 24.312 3.397 ;
     RECT  34.8 2.151 35.112 3.397 ;
     RECT  29.4 2.821 29.976 3.443 ;
     RECT  21.3 2.151 21.612 3.589 ;
     RECT  18.6 2.151 18.912 3.685 ;
     RECT  7.008 2.339 13.512 4.019 ;
     RECT  7.104 4.019 13.512 4.115 ;
     RECT  7.632 4.115 13.512 4.163 ;
     RECT  32.1 2.151 32.412 4.213 ;
     RECT  37.5 2.151 37.812 4.501 ;
     RECT  7.68 4.163 13.512 4.595 ;
     RECT  24 3.397 24.552 4.595 ;
     RECT  7.8 4.595 13.512 5.077 ;
     RECT  29.4 3.443 29.712 5.077 ;
     RECT  31.152 4.213 32.412 5.077 ;
     RECT  18.6 3.685 19.368 5.125 ;
     RECT  29.4 5.077 32.412 5.747 ;
     RECT  18 5.125 19.368 5.749 ;
     RECT  37.5 4.501 37.944 5.795 ;
     RECT  18 5.749 20.232 5.891 ;
     RECT  7.8 5.077 14.184 6.085 ;
     RECT  15.9 2.151 16.212 6.085 ;
     RECT  7.8 6.085 16.212 6.229 ;
     RECT  21.3 3.589 22.488 6.323 ;
     RECT  29.4 5.747 29.712 6.805 ;
     RECT  31.152 5.747 32.412 6.805 ;
     RECT  18 5.891 19.368 7.189 ;
     RECT  18 7.189 19.56 7.285 ;
     RECT  21.3 6.323 21.768 7.477 ;
     RECT  7.8 6.229 16.536 7.667 ;
     RECT  18 7.285 19.608 7.957 ;
     RECT  37.5 5.795 37.812 7.957 ;
     RECT  38.784 7.381 38.808 7.957 ;
     RECT  21.168 7.477 21.768 8.003 ;
     RECT  37.5 7.957 38.808 8.051 ;
     RECT  37.5 8.051 37.992 8.437 ;
     RECT  36.192 3.397 36.216 8.485 ;
     RECT  37.392 8.437 37.992 8.485 ;
     RECT  7.8 7.667 16.212 8.579 ;
     RECT  7.8 8.579 9.384 8.627 ;
     RECT  10.368 8.579 12.072 8.627 ;
     RECT  10.368 8.627 10.92 9.011 ;
     RECT  10.5 9.011 10.92 9.155 ;
     RECT  12.048 8.627 12.072 9.541 ;
     RECT  13.2 8.579 16.212 9.541 ;
     RECT  22.992 7.381 23.016 9.923 ;
     RECT  7.8 8.627 8.712 10.069 ;
     RECT  7.8 10.069 9.192 10.213 ;
     RECT  10.5 9.155 10.812 10.213 ;
     RECT  12.048 9.541 16.212 10.307 ;
     RECT  39.072 9.637 39.096 10.739 ;
     RECT  36.192 8.485 37.992 11.845 ;
     RECT  34.8 3.397 35.208 11.893 ;
     RECT  36.192 11.845 38.088 11.893 ;
     RECT  29.4 6.805 32.412 11.987 ;
     RECT  34.8 11.893 38.088 11.987 ;
     RECT  7.8 10.213 10.812 12.035 ;
     RECT  7.8 12.035 8.112 12.517 ;
     RECT  34.8 11.987 37.944 12.997 ;
     RECT  12.048 10.307 14.376 13.045 ;
     RECT  7.44 12.517 8.112 13.139 ;
     RECT  17.76 7.957 19.608 13.139 ;
     RECT  12.048 13.045 14.808 13.621 ;
     RECT  15.9 10.307 16.212 13.621 ;
     RECT  31.68 11.987 32.412 13.621 ;
     RECT  18 13.139 19.608 13.669 ;
     RECT  21.3 8.003 21.768 13.909 ;
     RECT  34.8 12.997 38.76 14.099 ;
     RECT  21.168 13.909 21.768 14.197 ;
     RECT  29.4 11.987 29.712 14.197 ;
     RECT  24 4.595 24.312 14.389 ;
     RECT  12.048 13.621 16.212 14.725 ;
     RECT  12.048 14.725 16.872 14.773 ;
     RECT  34.8 14.099 37.944 14.773 ;
     RECT  21.12 14.197 21.768 14.867 ;
     RECT  29.4 14.197 30.408 14.867 ;
     RECT  7.8 13.139 8.112 15.109 ;
     RECT  34.704 14.773 37.944 15.301 ;
     RECT  7.44 15.109 8.112 15.349 ;
     RECT  12 14.773 16.872 15.443 ;
     RECT  34.704 15.301 38.232 15.443 ;
     RECT  7.392 15.349 8.112 15.973 ;
     RECT  9.168 12.035 10.812 15.973 ;
     RECT  18 13.669 19.944 16.019 ;
     RECT  29.4 14.867 30.36 16.019 ;
     RECT  31.68 13.621 33.048 16.019 ;
     RECT  34.704 15.443 35.688 16.019 ;
     RECT  7.392 15.973 10.812 16.403 ;
     RECT  18.096 16.019 19.608 16.403 ;
     RECT  23.376 14.389 24.312 16.405 ;
     RECT  36.72 15.443 38.232 16.405 ;
     RECT  40.2 2.151 40.512 16.501 ;
     RECT  15.9 15.443 16.872 16.549 ;
     RECT  23.136 16.405 24.312 16.741 ;
     RECT  22.848 16.741 24.312 16.981 ;
     RECT  15.552 16.549 16.872 17.027 ;
     RECT  22.848 16.981 25.08 17.075 ;
     RECT  24 17.075 25.08 17.123 ;
     RECT  30.72 16.501 30.744 17.123 ;
     RECT  36.72 16.405 38.76 17.123 ;
     RECT  15.552 17.027 16.68 17.171 ;
     RECT  22.848 17.075 22.872 17.171 ;
     RECT  36.72 17.123 37.944 17.651 ;
     RECT  34.8 16.019 35.688 18.133 ;
     RECT  18.6 16.403 19.608 18.181 ;
     RECT  34.8 18.133 36.36 18.467 ;
     RECT  39.84 16.501 40.512 18.659 ;
     RECT  7.44 16.403 10.812 18.707 ;
     RECT  7.68 18.707 10.812 18.757 ;
     RECT  12 15.443 14.376 18.757 ;
     RECT  34.8 18.467 35.928 18.947 ;
     RECT  31.008 17.653 31.032 19.045 ;
     RECT  34.8 18.947 35.688 19.045 ;
     RECT  7.68 18.757 14.376 19.283 ;
     RECT  30.912 19.045 31.032 19.285 ;
     RECT  32.1 16.019 33.048 19.285 ;
     RECT  37.5 17.651 37.944 19.333 ;
     RECT  37.5 19.333 38.664 19.381 ;
     RECT  7.68 19.283 11.256 19.571 ;
     RECT  15.744 17.171 16.68 19.571 ;
     RECT  37.5 19.381 38.808 19.573 ;
     RECT  17.952 18.181 19.608 19.811 ;
     RECT  30.912 19.285 33.048 20.003 ;
     RECT  36.912 19.573 38.808 20.003 ;
     RECT  15.9 19.571 16.68 20.533 ;
     RECT  31.632 20.003 33.048 20.965 ;
     RECT  34.512 19.045 35.688 20.965 ;
     RECT  18.6 19.811 19.608 21.155 ;
     RECT  15.792 20.533 16.68 21.493 ;
     RECT  36.912 20.003 38.664 21.493 ;
     RECT  31.632 20.965 35.688 21.637 ;
     RECT  36.912 21.493 38.712 21.637 ;
     RECT  40.2 18.659 40.512 21.637 ;
     RECT  21.3 14.867 21.612 21.877 ;
     RECT  31.344 21.637 35.688 22.021 ;
     RECT  36.912 21.637 40.512 22.021 ;
     RECT  7.8 19.571 11.256 22.067 ;
     RECT  18.6 21.155 18.912 22.165 ;
     RECT  15.456 21.493 16.68 22.451 ;
     RECT  28.176 17.413 28.2 22.835 ;
     RECT  21.168 21.877 21.612 22.883 ;
     RECT  31.344 22.021 40.512 22.883 ;
     RECT  17.856 22.165 18.912 23.411 ;
     RECT  31.344 22.883 35.448 23.411 ;
     RECT  29.4 16.019 29.712 23.557 ;
     RECT  24 17.123 24.312 23.653 ;
     RECT  12.912 19.283 14.376 24.469 ;
     RECT  23.328 23.653 24.312 24.469 ;
     RECT  36.48 22.883 40.512 25.667 ;
     RECT  12.24 24.469 14.376 26.291 ;
     RECT  15.9 22.451 16.68 26.293 ;
     RECT  31.632 23.411 35.448 26.725 ;
     RECT  36.72 25.667 40.512 26.725 ;
     RECT  31.632 26.725 40.512 26.819 ;
     RECT  7.8 22.067 10.812 27.301 ;
     RECT  23.328 24.469 25.128 27.301 ;
     RECT  26.7 2.151 27.012 27.301 ;
     RECT  15.9 26.293 17.112 27.347 ;
     RECT  31.632 26.819 35.112 27.445 ;
     RECT  21.3 22.883 21.612 27.733 ;
     RECT  28.896 23.557 29.712 27.971 ;
     RECT  7.8 27.301 11.208 28.163 ;
     RECT  36.288 26.819 40.512 28.211 ;
     RECT  15.9 27.347 16.68 28.837 ;
     RECT  20.352 27.733 21.612 28.933 ;
     RECT  19.92 28.933 21.612 28.979 ;
     RECT  31.104 27.445 35.112 28.981 ;
     RECT  29.4 27.971 29.712 29.029 ;
     RECT  31.104 28.981 35.208 29.029 ;
     RECT  7.8 28.163 10.812 29.605 ;
     RECT  15.9 28.837 16.728 29.651 ;
     RECT  7.8 29.605 11.208 30.133 ;
     RECT  19.92 28.979 19.944 30.371 ;
     RECT  23.328 27.301 27.012 30.709 ;
     RECT  36.912 28.211 40.512 30.709 ;
     RECT  23.328 30.709 27.96 30.851 ;
     RECT  26.7 30.851 27.96 31.477 ;
     RECT  29.4 29.029 35.784 31.477 ;
     RECT  26.7 31.477 35.784 31.619 ;
     RECT  26.7 31.619 29.712 31.667 ;
     RECT  31.104 31.619 35.784 31.667 ;
     RECT  7.68 30.133 11.208 31.717 ;
     RECT  26.7 31.667 27.144 31.811 ;
     RECT  12.912 26.291 14.376 31.813 ;
     RECT  12.912 31.813 14.712 32.197 ;
     RECT  15.9 29.651 16.68 32.197 ;
     RECT  31.296 31.667 35.784 32.339 ;
     RECT  34.8 32.339 35.784 32.437 ;
     RECT  36.816 30.709 40.512 32.437 ;
     RECT  18.6 23.411 18.912 32.821 ;
     RECT  23.328 30.851 25.128 33.013 ;
     RECT  23.232 33.013 25.128 33.635 ;
     RECT  31.296 32.339 33.432 33.683 ;
     RECT  7.68 31.717 11.448 33.779 ;
     RECT  7.68 33.779 10.812 34.115 ;
     RECT  12.912 32.197 16.68 34.259 ;
     RECT  18.144 32.821 18.912 34.259 ;
     RECT  12.912 34.259 14.712 34.643 ;
     RECT  28.608 31.667 29.712 34.645 ;
     RECT  31.632 33.683 33.432 34.645 ;
     RECT  28.608 34.645 33.432 34.741 ;
     RECT  34.8 32.437 40.512 34.741 ;
     RECT  7.8 34.115 10.812 35.029 ;
     RECT  28.608 34.741 40.512 35.315 ;
     RECT  23.328 33.635 25.128 35.363 ;
     RECT  29.4 35.315 40.512 35.363 ;
     RECT  15.9 34.259 16.68 35.939 ;
     RECT  29.4 35.363 33.048 35.939 ;
     RECT  18.192 34.259 18.912 36.275 ;
     RECT  7.8 35.029 11.448 36.515 ;
     RECT  12.912 34.643 14.376 36.515 ;
     RECT  15.9 35.939 16.212 36.997 ;
     RECT  34.032 35.363 40.512 37.091 ;
     RECT  26.7 31.811 27.012 37.093 ;
     RECT  15.9 36.997 17.112 37.139 ;
     RECT  10.5 36.515 10.812 37.573 ;
     RECT  29.4 35.939 30.696 37.667 ;
     RECT  31.968 35.939 33.048 37.763 ;
     RECT  10.368 37.573 10.812 38.435 ;
     RECT  18.48 36.275 18.912 38.435 ;
     RECT  23.328 35.363 24.312 38.677 ;
     RECT  23.328 38.677 24.408 38.773 ;
     RECT  12.912 36.515 13.896 38.819 ;
     RECT  22.704 38.773 24.408 38.915 ;
     RECT  32.1 37.763 33.048 39.013 ;
     RECT  5.1 2.151 5.412 39.301 ;
     RECT  19.968 32.437 19.992 39.395 ;
     RECT  10.5 38.435 10.812 39.877 ;
     RECT  29.4 37.667 29.712 39.877 ;
     RECT  5.1 39.301 5.784 39.971 ;
     RECT  18.6 38.435 18.912 40.165 ;
     RECT  29.4 39.877 30.504 40.261 ;
     RECT  22.8 38.915 24.408 40.307 ;
     RECT  31.92 39.013 33.048 40.405 ;
     RECT  26.7 37.093 27.768 40.499 ;
     RECT  29.28 40.261 30.504 40.501 ;
     RECT  15.9 37.139 16.212 40.693 ;
     RECT  12.912 38.819 13.512 40.837 ;
     RECT  29.28 40.501 30.696 40.837 ;
     RECT  26.7 40.499 27.336 40.933 ;
     RECT  10.5 39.877 11.304 40.979 ;
     RECT  20.256 40.405 20.28 41.027 ;
     RECT  28.32 40.837 30.696 41.123 ;
     RECT  5.1 39.971 5.412 41.221 ;
     RECT  28.32 41.123 29.712 41.315 ;
     RECT  26.208 40.933 27.336 41.509 ;
     RECT  28.32 41.315 28.344 41.509 ;
     RECT  18.288 40.165 18.912 41.603 ;
     RECT  31.92 40.405 33.672 41.699 ;
     RECT  10.5 40.979 10.812 41.749 ;
     RECT  31.92 41.699 32.568 41.795 ;
     RECT  33.648 41.699 33.672 41.941 ;
     RECT  34.8 37.091 40.512 41.941 ;
     RECT  33.648 41.941 40.512 41.987 ;
     RECT  15.648 40.693 16.212 42.037 ;
     RECT  15.648 42.037 16.824 42.133 ;
     RECT  26.208 41.509 28.344 42.227 ;
     RECT  32.1 41.795 32.568 42.467 ;
     RECT  10.176 41.749 10.812 42.707 ;
     RECT  5.1 41.221 5.88 42.755 ;
     RECT  26.208 42.227 27.336 42.803 ;
     RECT  12.768 40.837 13.512 43.093 ;
     RECT  14.784 42.133 16.824 43.139 ;
     RECT  26.7 42.803 27.336 43.237 ;
     RECT  28.32 42.227 28.344 43.237 ;
     RECT  29.4 41.315 29.712 43.285 ;
     RECT  26.7 43.237 28.344 43.333 ;
     RECT  29.4 43.285 30.216 43.333 ;
     RECT  26.7 43.333 30.216 43.379 ;
     RECT  23.328 40.307 24.408 43.717 ;
     RECT  10.368 42.707 10.812 43.861 ;
     RECT  12 43.093 13.512 43.861 ;
     RECT  14.784 43.139 16.212 43.907 ;
     RECT  5.1 42.755 5.64 44.099 ;
     RECT  26.7 43.379 27.816 44.197 ;
     RECT  18.6 41.603 18.912 44.437 ;
     RECT  23.328 43.717 25.128 44.483 ;
     RECT  34.224 41.987 40.512 44.483 ;
     RECT  15.648 43.907 16.212 44.867 ;
     RECT  29.088 43.379 30.216 44.867 ;
     RECT  26.208 44.197 27.816 45.059 ;
     RECT  18.6 44.437 19.368 45.541 ;
     RECT  21.3 28.979 21.612 45.541 ;
     RECT  10.368 43.861 13.512 45.587 ;
     RECT  12 45.587 13.512 45.635 ;
     RECT  32.1 42.467 32.412 46.069 ;
     RECT  7.8 36.515 9.192 46.117 ;
     RECT  12.912 45.635 13.512 46.117 ;
     RECT  34.8 44.483 40.512 46.211 ;
     RECT  7.056 46.117 9.192 46.787 ;
     RECT  34.8 46.211 35.352 46.787 ;
     RECT  21.3 45.541 21.816 46.883 ;
     RECT  12.912 46.117 14.28 46.885 ;
     RECT  26.7 45.059 27.816 47.077 ;
     RECT  11.952 46.885 14.28 47.171 ;
     RECT  31.968 46.069 32.412 47.171 ;
     RECT  29.088 44.867 29.712 47.269 ;
     RECT  18.6 45.541 19.896 47.315 ;
     RECT  34.8 46.787 35.112 47.413 ;
     RECT  11.952 47.171 13.608 47.891 ;
     RECT  12.912 47.891 13.608 47.987 ;
     RECT  29.088 47.269 29.832 48.227 ;
     RECT  34.704 47.413 35.112 48.229 ;
     RECT  23.328 44.483 24.408 48.373 ;
     RECT  21.3 46.883 21.612 48.421 ;
     RECT  23.328 48.373 25.08 48.421 ;
     RECT  7.056 46.787 8.856 48.467 ;
     RECT  18.6 47.315 19.608 48.467 ;
     RECT  29.28 48.227 29.832 48.467 ;
     RECT  10.368 45.587 10.812 48.949 ;
     RECT  34.128 48.229 35.112 48.995 ;
     RECT  12.912 47.987 13.512 49.525 ;
     RECT  21.3 48.421 25.08 49.619 ;
     RECT  21.3 49.619 24.984 49.811 ;
     RECT  36.528 46.211 40.512 49.861 ;
     RECT  7.392 48.467 8.856 50.051 ;
     RECT  34.8 48.995 35.112 50.053 ;
     RECT  32.1 47.171 32.412 50.101 ;
     RECT  9.888 48.949 10.812 50.291 ;
     RECT  31.824 50.101 33.336 50.293 ;
     RECT  11.952 49.525 13.512 50.771 ;
     RECT  36.24 49.861 40.512 50.819 ;
     RECT  31.776 50.293 33.336 50.867 ;
     RECT  23.328 49.811 24.984 50.917 ;
     RECT  29.28 48.467 29.712 50.917 ;
     RECT  10.5 50.291 10.812 51.205 ;
     RECT  26.7 47.077 27.912 51.539 ;
     RECT  26.7 51.539 27.576 51.635 ;
     RECT  36.816 50.819 40.512 51.923 ;
     RECT  23.328 50.917 25.128 52.019 ;
     RECT  26.7 51.635 27.012 52.117 ;
     RECT  31.824 50.867 33.336 52.211 ;
     RECT  15.792 44.867 16.212 52.213 ;
     RECT  23.328 52.019 24.312 52.259 ;
     RECT  31.824 52.211 32.412 52.357 ;
     RECT  10.5 51.205 11.544 52.499 ;
     RECT  39.264 51.923 40.512 52.499 ;
     RECT  12.912 50.771 13.512 52.741 ;
     RECT  5.1 44.099 5.412 52.885 ;
     RECT  34.704 50.053 35.112 52.979 ;
     RECT  7.8 50.051 8.856 52.981 ;
     RECT  29.28 50.917 30.264 52.981 ;
     RECT  31.536 52.357 32.412 52.981 ;
     RECT  36.816 51.923 37.944 53.075 ;
     RECT  26.592 52.117 27.012 53.509 ;
     RECT  7.8 52.981 9.528 53.555 ;
     RECT  26.592 53.509 27.24 53.557 ;
     RECT  29.28 52.981 32.412 53.557 ;
     RECT  7.8 53.555 8.856 53.603 ;
     RECT  25.68 53.557 27.24 53.603 ;
     RECT  10.5 52.499 10.812 54.085 ;
     RECT  15.6 52.213 16.212 54.085 ;
     RECT  36.816 53.075 37.812 54.085 ;
     RECT  26.7 53.603 27.24 54.179 ;
     RECT  12.912 52.741 13.656 54.371 ;
     RECT  28.944 53.557 32.412 54.611 ;
     RECT  24 52.259 24.312 54.613 ;
     RECT  25.68 53.603 25.704 54.613 ;
     RECT  7.8 53.603 8.232 54.661 ;
     RECT  18.6 48.467 18.912 54.661 ;
     RECT  7.44 54.661 8.232 54.707 ;
     RECT  28.944 54.611 30.264 54.707 ;
     RECT  24 54.613 25.704 54.755 ;
     RECT  36.816 54.085 38.76 54.755 ;
     RECT  10.368 54.085 10.812 54.995 ;
     RECT  18.6 54.661 19.176 55.043 ;
     RECT  15.6 54.085 16.536 55.187 ;
     RECT  4.992 52.885 5.412 55.331 ;
     RECT  31.536 54.611 32.412 55.331 ;
     RECT  34.8 52.979 35.112 55.429 ;
     RECT  28.944 54.707 30.216 55.525 ;
     RECT  34.704 55.429 35.112 55.859 ;
     RECT  24 54.755 24.792 55.861 ;
     RECT  23.136 55.861 24.792 55.955 ;
     RECT  15.6 55.187 16.212 56.341 ;
     RECT  36.816 54.755 38.712 56.387 ;
     RECT  18.6 55.043 19.032 56.435 ;
     RECT  10.5 54.995 10.812 56.437 ;
     RECT  28.848 55.525 30.216 56.675 ;
     RECT  29.28 56.675 30.216 56.771 ;
     RECT  5.1 55.331 5.412 56.965 ;
     RECT  9.936 56.437 10.812 57.011 ;
     RECT  15.216 56.341 16.212 57.011 ;
     RECT  31.824 55.331 32.412 57.013 ;
     RECT  10.5 57.011 10.812 57.157 ;
     RECT  31.824 57.013 33.144 57.299 ;
     RECT  18.6 56.435 18.912 57.397 ;
     RECT  23.136 55.955 24.312 57.635 ;
     RECT  5.1 56.965 5.544 57.925 ;
     RECT  4.992 57.925 5.544 57.971 ;
     RECT  18.24 57.397 18.912 58.117 ;
     RECT  15.6 57.011 16.212 58.163 ;
     RECT  36.816 56.387 37.812 58.501 ;
     RECT  26.7 54.179 27.012 58.549 ;
     RECT  7.44 54.707 8.112 58.643 ;
     RECT  24 57.635 24.312 58.645 ;
     RECT  25.728 58.549 27.012 58.645 ;
     RECT  31.824 57.299 32.412 58.645 ;
     RECT  10.5 57.157 11.544 58.691 ;
     RECT  17.472 58.117 18.912 58.691 ;
     RECT  25.632 58.645 27.012 59.219 ;
     RECT  15.9 58.163 16.212 59.221 ;
     RECT  17.472 58.691 17.496 59.221 ;
     RECT  29.28 56.771 29.712 59.411 ;
     RECT  31.296 58.645 32.412 59.701 ;
     RECT  30.816 59.701 32.412 59.747 ;
     RECT  10.5 58.691 11.112 59.749 ;
     RECT  15.9 59.221 17.496 59.891 ;
     RECT  36.768 58.501 37.812 59.891 ;
     RECT  38.88 59.221 38.904 59.891 ;
     RECT  7.8 58.643 8.112 60.181 ;
     RECT  9.648 59.749 11.208 60.181 ;
     RECT  14.64 58.645 14.856 60.275 ;
     RECT  4.992 57.971 5.412 60.467 ;
     RECT  6.72 59.749 6.744 60.467 ;
     RECT  7.8 60.181 11.208 60.467 ;
     RECT  14.832 60.275 14.856 60.467 ;
     RECT  23.904 58.645 24.312 60.805 ;
     RECT  25.728 59.219 27.012 60.805 ;
     RECT  17.472 59.891 17.496 60.949 ;
     RECT  18.6 58.691 18.912 60.949 ;
     RECT  17.472 60.949 18.912 60.995 ;
     RECT  7.8 60.467 10.812 61.523 ;
     RECT  25.728 60.805 27.576 61.619 ;
     RECT  23.232 60.805 24.312 61.907 ;
     RECT  5.1 60.467 5.412 62.005 ;
     RECT  12.912 54.371 13.512 62.005 ;
     RECT  34.8 55.859 35.112 62.005 ;
     RECT  30.816 59.747 30.84 62.051 ;
     RECT  20.256 62.437 20.28 62.533 ;
     RECT  21.3 49.811 21.612 62.533 ;
     RECT  29.4 59.411 29.712 62.581 ;
     RECT  14.784 61.573 14.808 62.675 ;
     RECT  31.824 59.747 32.412 62.675 ;
     RECT  31.92 62.675 32.412 62.867 ;
     RECT  10.272 61.523 10.812 62.915 ;
     RECT  7.8 61.523 8.808 62.965 ;
     RECT  25.728 61.619 27.012 62.965 ;
     RECT  28.848 62.581 29.712 62.965 ;
     RECT  5.1 62.005 6.024 63.011 ;
     RECT  12.048 62.005 13.512 63.059 ;
     RECT  10.5 62.915 10.812 63.061 ;
     RECT  15.9 59.891 16.212 63.109 ;
     RECT  34.8 62.005 35.208 63.157 ;
     RECT  34.8 63.157 35.304 63.347 ;
     RECT  34.8 63.347 35.112 63.349 ;
     RECT  37.5 59.891 37.812 63.685 ;
     RECT  38.832 62.677 38.856 63.685 ;
     RECT  17.616 60.995 18.912 63.733 ;
     RECT  10.5 63.061 11.592 63.779 ;
     RECT  20.256 62.533 21.612 63.779 ;
     RECT  15.12 63.109 16.212 63.781 ;
     RECT  17.424 63.733 18.912 63.827 ;
     RECT  25.728 62.965 29.712 63.875 ;
     RECT  14.832 63.781 16.212 64.019 ;
     RECT  34.08 63.349 35.112 64.067 ;
     RECT  37.5 63.685 38.856 64.115 ;
     RECT  28.848 63.875 29.712 64.163 ;
     RECT  7.8 62.965 9.096 64.211 ;
     RECT  12.912 63.059 13.512 64.309 ;
     RECT  30.72 63.541 30.744 64.547 ;
     RECT  31.968 62.867 32.412 64.741 ;
     RECT  5.1 63.011 5.784 64.835 ;
     RECT  17.424 63.827 17.448 64.885 ;
     RECT  18.6 63.827 18.912 64.885 ;
     RECT  17.424 64.885 18.912 64.931 ;
     RECT  24 61.907 24.312 64.933 ;
     RECT  25.728 63.875 27.012 64.933 ;
     RECT  23.376 64.933 27.012 65.317 ;
     RECT  38.832 64.115 38.856 65.363 ;
     RECT  29.4 64.163 29.712 65.413 ;
     RECT  17.616 64.931 18.912 65.603 ;
     RECT  31.968 64.741 32.904 65.603 ;
     RECT  12.624 64.309 13.512 65.651 ;
     RECT  21.072 63.779 21.612 65.653 ;
     RECT  7.8 64.211 8.808 65.845 ;
     RECT  23.376 65.317 27.336 65.939 ;
     RECT  6.912 65.845 8.808 65.987 ;
     RECT  25.488 65.939 27.336 66.179 ;
     RECT  21.072 65.653 22.2 66.181 ;
     RECT  23.376 65.939 24.312 66.227 ;
     RECT  34.272 64.067 35.112 66.227 ;
     RECT  6.912 65.987 8.112 66.613 ;
     RECT  6.768 66.613 8.112 66.659 ;
     RECT  12.912 65.651 13.512 66.755 ;
     RECT  29.28 65.413 29.712 66.755 ;
     RECT  15.9 64.019 16.212 66.757 ;
     RECT  18.24 65.603 18.912 66.803 ;
     RECT  20.544 66.181 22.2 66.803 ;
     RECT  24 66.227 24.312 67.141 ;
     RECT  15.9 66.757 16.872 67.331 ;
     RECT  18.48 66.803 18.912 67.331 ;
     RECT  21.3 66.803 22.2 67.669 ;
     RECT  33.792 67.141 33.816 67.765 ;
     RECT  34.8 66.227 35.112 67.765 ;
     RECT  24 67.141 24.504 68.149 ;
     RECT  25.488 66.179 27.012 68.149 ;
     RECT  21.3 67.669 22.968 68.387 ;
     RECT  10.5 63.779 10.812 68.389 ;
     RECT  24 68.149 27.012 68.435 ;
     RECT  29.4 66.755 29.712 68.773 ;
     RECT  26.592 68.435 27.012 68.915 ;
     RECT  18.6 67.331 18.912 68.917 ;
     RECT  31.968 65.603 32.412 68.917 ;
     RECT  33.792 67.765 35.112 68.965 ;
     RECT  10.5 68.389 11.592 69.011 ;
     RECT  22.944 68.387 22.968 69.011 ;
     RECT  33.408 68.965 35.112 69.059 ;
     RECT  26.7 68.915 27.012 69.493 ;
     RECT  21.3 68.387 21.72 69.541 ;
     RECT  6.768 66.659 6.792 69.731 ;
     RECT  20.592 69.541 21.72 69.731 ;
     RECT  18.6 68.917 19.176 69.875 ;
     RECT  29.4 68.773 30.216 69.875 ;
     RECT  33.408 69.059 33.816 69.875 ;
     RECT  9.312 67.765 9.336 70.019 ;
     RECT  34.8 69.059 35.112 70.069 ;
     RECT  36.432 68.917 36.456 70.069 ;
     RECT  34.8 70.069 36.456 70.115 ;
     RECT  26.7 69.493 27.624 70.403 ;
     RECT  31.92 68.917 32.412 70.405 ;
     RECT  29.4 69.875 29.88 70.451 ;
     RECT  33.408 69.875 33.672 70.499 ;
     RECT  20.592 69.731 21.612 70.547 ;
     RECT  31.008 70.405 32.412 70.643 ;
     RECT  34.8 70.115 35.544 70.835 ;
     RECT  33.504 70.499 33.672 71.315 ;
     RECT  33.648 71.315 33.672 71.363 ;
     RECT  21.072 70.547 21.612 71.747 ;
     RECT  15.9 67.331 16.212 72.085 ;
     RECT  37.5 64.115 37.812 72.373 ;
     RECT  24 68.435 25.512 72.853 ;
     RECT  26.7 70.403 27.012 72.853 ;
     RECT  10.5 69.011 10.812 72.901 ;
     RECT  24 72.853 27.012 72.947 ;
     RECT  14.832 64.019 14.856 72.995 ;
     RECT  15.9 72.085 17.016 72.995 ;
     RECT  38.88 70.165 38.904 72.995 ;
     RECT  25.68 72.947 27.012 73.427 ;
     RECT  10.5 72.901 11.352 73.523 ;
     RECT  29.4 70.451 29.712 73.717 ;
     RECT  31.008 70.643 31.032 73.717 ;
     RECT  29.4 73.717 31.032 73.763 ;
     RECT  37.152 72.373 37.812 74.051 ;
     RECT  29.4 73.763 30.072 74.291 ;
     RECT  25.68 73.427 25.704 74.627 ;
     RECT  2.4 2.151 2.712 75.609 ;
     RECT  5.1 64.835 5.412 75.609 ;
     RECT  7.8 66.659 8.112 75.609 ;
     RECT  10.5 73.523 10.812 75.609 ;
     RECT  13.2 66.755 13.512 75.609 ;
     RECT  15.9 72.995 16.212 75.609 ;
     RECT  18.6 69.875 18.912 75.609 ;
     RECT  21.3 71.747 21.612 75.609 ;
     RECT  24 72.947 24.312 75.609 ;
     RECT  26.7 73.427 27.012 75.609 ;
     RECT  29.4 74.291 29.712 75.609 ;
     RECT  32.1 70.643 32.412 75.609 ;
     RECT  34.8 70.835 35.112 75.609 ;
     RECT  37.5 74.051 37.812 75.609 ;
     RECT  40.2 52.499 40.512 75.609 ;
     RECT  2.4 75.609 2.52 75.623 ;
     RECT  5.1 75.609 5.22 75.623 ;
     RECT  7.8 75.609 7.92 75.623 ;
     RECT  10.5 75.609 10.62 75.623 ;
     RECT  13.2 75.609 13.32 75.623 ;
     RECT  15.9 75.609 16.02 75.623 ;
     RECT  18.6 75.609 18.72 75.623 ;
     RECT  21.3 75.609 21.42 75.623 ;
     RECT  24 75.609 24.12 75.623 ;
     RECT  26.7 75.609 26.82 75.623 ;
     RECT  29.4 75.609 29.52 75.623 ;
     RECT  32.1 75.609 32.22 75.623 ;
     RECT  34.8 75.609 34.92 75.623 ;
     RECT  37.5 75.609 37.62 75.623 ;
     RECT  40.2 75.609 40.32 75.623 ;
     RECT  5.22 2.137 6.624 2.151 ;
     RECT  5.412 2.151 6.624 2.339 ;
     RECT  35.208 3.397 36.192 11.893 ;
     RECT  36.216 3.397 37.5 8.437 ;
     RECT  29.712 3.443 29.976 4.213 ;
     RECT  22.488 3.589 24 6.323 ;
     RECT  29.712 4.213 31.152 5.077 ;
     RECT  29.712 5.747 31.152 6.805 ;
     RECT  20.232 5.749 21.3 5.891 ;
     RECT  19.368 5.891 19.608 7.189 ;
     RECT  16.536 6.229 18 7.667 ;
     RECT  21.768 6.323 24 7.381 ;
     RECT  19.56 7.189 19.608 7.285 ;
     RECT  21.768 7.381 22.992 9.923 ;
     RECT  23.016 7.381 24 9.923 ;
     RECT  37.812 7.381 38.784 7.957 ;
     RECT  38.808 7.381 40.2 8.051 ;
     RECT  17.76 7.667 18 7.957 ;
     RECT  36.216 8.437 37.392 8.485 ;
     RECT  9.384 8.579 10.368 8.627 ;
     RECT  12.072 8.579 13.2 9.541 ;
     RECT  8.712 8.627 10.368 9.011 ;
     RECT  10.92 8.627 12.048 9.155 ;
     RECT  8.712 9.011 10.5 10.069 ;
     RECT  10.812 9.155 12.048 14.773 ;
     RECT  37.992 9.637 39.072 10.739 ;
     RECT  39.096 9.637 40.2 10.739 ;
     RECT  9.192 10.069 10.5 10.213 ;
     RECT  14.376 10.307 15.9 13.045 ;
     RECT  37.992 10.739 38.088 11.845 ;
     RECT  37.944 11.987 38.088 12.997 ;
     RECT  8.112 12.035 9.168 15.973 ;
     RECT  38.76 12.997 40.2 14.099 ;
     RECT  14.808 13.045 15.9 13.621 ;
     RECT  19.944 13.669 21.3 13.909 ;
     RECT  19.944 13.909 21.168 14.197 ;
     RECT  37.944 14.099 38.232 15.301 ;
     RECT  19.944 14.197 21.12 14.867 ;
     RECT  30.408 14.197 31.68 14.867 ;
     RECT  16.872 14.725 18 16.019 ;
     RECT  10.812 14.773 12 18.757 ;
     RECT  19.944 14.867 21.3 16.019 ;
     RECT  30.36 14.867 31.68 16.019 ;
     RECT  14.376 15.443 15.9 16.549 ;
     RECT  35.688 15.443 36.72 17.651 ;
     RECT  16.872 16.019 18.096 16.403 ;
     RECT  29.712 16.019 32.1 16.501 ;
     RECT  21.612 16.405 23.136 16.741 ;
     RECT  38.76 16.405 40.2 16.501 ;
     RECT  29.712 16.501 30.72 17.123 ;
     RECT  30.744 16.501 32.1 17.123 ;
     RECT  38.76 16.501 39.84 17.123 ;
     RECT  14.376 16.549 15.552 17.171 ;
     RECT  21.612 16.741 22.848 17.171 ;
     RECT  16.68 17.027 16.872 18.181 ;
     RECT  22.872 17.075 24 17.171 ;
     RECT  29.712 17.123 32.1 17.653 ;
     RECT  14.376 17.171 15.744 19.571 ;
     RECT  27.012 17.413 28.176 22.835 ;
     RECT  28.2 17.413 29.4 22.835 ;
     RECT  35.688 17.651 37.5 18.133 ;
     RECT  29.712 17.653 31.008 19.045 ;
     RECT  31.032 17.653 32.1 19.285 ;
     RECT  36.36 18.133 37.5 18.467 ;
     RECT  16.68 18.181 17.952 19.811 ;
     RECT  35.928 18.467 37.5 18.947 ;
     RECT  39.84 18.659 40.2 19.333 ;
     RECT  35.688 18.947 37.5 19.573 ;
     RECT  29.712 19.045 30.912 20.003 ;
     RECT  33.048 19.045 34.512 20.965 ;
     RECT  38.664 19.333 40.2 19.381 ;
     RECT  38.808 19.381 40.2 20.003 ;
     RECT  14.376 19.571 15.9 20.533 ;
     RECT  35.688 19.573 36.912 22.021 ;
     RECT  38.664 20.003 40.2 21.493 ;
     RECT  14.376 20.533 15.792 21.493 ;
     RECT  14.376 21.493 15.456 22.451 ;
     RECT  38.712 21.493 40.2 21.637 ;
     RECT  16.68 22.165 17.856 23.411 ;
     RECT  14.376 22.451 15.9 31.813 ;
     RECT  28.896 22.835 29.4 23.557 ;
     RECT  35.448 22.883 36.48 25.667 ;
     RECT  10.812 24.469 12.24 26.291 ;
     RECT  35.448 25.667 36.72 26.725 ;
     RECT  10.812 26.291 11.208 27.301 ;
     RECT  17.112 26.293 18.6 27.347 ;
     RECT  35.112 26.819 36.288 28.211 ;
     RECT  16.68 27.347 16.728 28.837 ;
     RECT  29.712 27.445 31.104 29.029 ;
     RECT  18.912 27.733 20.352 28.933 ;
     RECT  10.812 28.163 11.208 29.605 ;
     RECT  35.112 28.211 36.912 28.981 ;
     RECT  18.912 28.933 19.92 30.371 ;
     RECT  19.944 28.979 21.3 30.371 ;
     RECT  35.208 28.981 36.912 29.029 ;
     RECT  35.784 29.029 36.912 30.709 ;
     RECT  27.96 30.709 29.4 31.477 ;
     RECT  35.784 30.709 36.816 32.437 ;
     RECT  29.712 31.619 31.104 31.667 ;
     RECT  27.144 31.667 28.608 31.811 ;
     RECT  11.448 31.717 12.912 33.779 ;
     RECT  14.712 31.813 15.9 32.197 ;
     RECT  33.432 32.339 34.8 34.741 ;
     RECT  18.912 32.437 19.968 39.395 ;
     RECT  19.992 32.437 21.3 39.395 ;
     RECT  16.68 32.821 18.144 34.259 ;
     RECT  31.296 33.683 31.632 34.645 ;
     RECT  10.812 33.779 12.912 35.029 ;
     RECT  14.712 34.259 15.9 34.643 ;
     RECT  16.68 34.259 18.192 35.939 ;
     RECT  14.376 34.643 15.9 36.515 ;
     RECT  11.448 35.029 12.912 36.515 ;
     RECT  33.048 35.363 34.032 37.091 ;
     RECT  16.212 35.939 18.192 36.275 ;
     RECT  30.696 35.939 31.968 37.667 ;
     RECT  16.212 36.275 18.48 36.997 ;
     RECT  9.192 36.515 10.5 37.573 ;
     RECT  17.112 36.997 18.48 37.139 ;
     RECT  9.192 37.573 10.368 38.435 ;
     RECT  31.92 37.667 31.968 37.763 ;
     RECT  31.92 37.763 32.1 39.013 ;
     RECT  9.192 38.435 10.5 41.749 ;
     RECT  21.612 38.773 22.704 38.915 ;
     RECT  21.612 38.915 22.8 40.307 ;
     RECT  18.912 39.395 21.3 40.405 ;
     RECT  30.504 39.877 31.92 40.501 ;
     RECT  5.412 39.971 5.784 41.221 ;
     RECT  27.768 40.261 29.28 40.499 ;
     RECT  18.912 40.405 20.256 41.027 ;
     RECT  20.28 40.405 21.3 41.027 ;
     RECT  33.672 40.405 34.8 41.941 ;
     RECT  27.336 40.499 29.28 40.837 ;
     RECT  30.696 40.501 31.92 41.123 ;
     RECT  11.304 40.837 12.768 40.979 ;
     RECT  27.336 40.837 28.32 41.509 ;
     RECT  28.344 41.315 29.4 43.333 ;
     RECT  32.568 41.699 33.648 41.987 ;
     RECT  9.192 41.749 10.176 42.707 ;
     RECT  13.512 42.133 14.784 43.907 ;
     RECT  27.336 42.227 28.32 43.237 ;
     RECT  9.192 42.707 10.368 46.787 ;
     RECT  26.208 42.803 26.7 43.717 ;
     RECT  10.812 43.093 12 43.861 ;
     RECT  27.816 43.379 29.088 47.077 ;
     RECT  25.128 43.717 26.7 44.197 ;
     RECT  25.128 44.197 26.208 44.483 ;
     RECT  15.648 44.867 15.792 46.117 ;
     RECT  19.896 45.541 21.3 47.315 ;
     RECT  21.816 45.541 23.328 46.883 ;
     RECT  10.812 45.587 12 45.635 ;
     RECT  10.812 45.635 12.912 46.885 ;
     RECT  14.28 46.117 15.792 47.171 ;
     RECT  35.352 46.211 36.528 46.787 ;
     RECT  8.856 46.787 10.368 48.949 ;
     RECT  35.112 46.787 36.528 49.861 ;
     RECT  10.812 46.885 11.952 47.891 ;
     RECT  27.912 47.077 29.088 48.227 ;
     RECT  27.912 48.227 29.28 51.539 ;
     RECT  8.856 48.949 9.888 50.291 ;
     RECT  34.128 48.995 34.8 50.053 ;
     RECT  10.812 49.525 11.952 50.771 ;
     RECT  24.984 49.619 25.08 50.917 ;
     RECT  35.112 49.861 36.24 50.819 ;
     RECT  34.128 50.053 34.704 50.101 ;
     RECT  33.336 50.101 34.704 52.211 ;
     RECT  10.812 50.771 12.912 51.205 ;
     RECT  31.776 50.867 31.824 50.917 ;
     RECT  30.264 50.917 31.824 52.357 ;
     RECT  11.544 51.205 12.912 52.499 ;
     RECT  37.944 51.923 39.264 52.499 ;
     RECT  30.264 52.357 31.536 52.981 ;
     RECT  9.528 52.981 10.5 53.555 ;
     RECT  37.812 53.075 37.944 54.085 ;
     RECT  8.856 53.555 10.5 53.603 ;
     RECT  24.312 53.557 25.68 54.613 ;
     RECT  10.368 53.603 10.5 54.085 ;
     RECT  25.704 53.603 26.7 54.755 ;
     RECT  38.76 54.085 40.2 54.755 ;
     RECT  30.264 54.611 31.536 54.707 ;
     RECT  30.216 54.707 31.536 55.331 ;
     RECT  38.712 54.755 40.2 56.387 ;
     RECT  10.368 54.995 10.5 56.437 ;
     RECT  21.612 55.861 23.136 57.635 ;
     RECT  11.544 57.157 12.912 58.691 ;
     RECT  23.904 57.635 24 58.645 ;
     RECT  16.212 58.117 17.472 59.221 ;
     RECT  15.6 58.163 15.9 58.645 ;
     RECT  24.312 58.549 25.728 58.645 ;
     RECT  7.44 58.643 7.8 59.749 ;
     RECT  13.512 58.645 14.64 60.275 ;
     RECT  14.856 58.645 15.9 60.467 ;
     RECT  24.312 58.645 25.632 59.219 ;
     RECT  11.112 58.691 11.208 59.749 ;
     RECT  17.496 58.691 18.6 60.949 ;
     RECT  24.312 59.219 25.728 64.933 ;
     RECT  37.812 59.221 38.88 59.891 ;
     RECT  38.904 59.221 40.2 59.891 ;
     RECT  29.712 59.701 30.816 62.051 ;
     RECT  30.84 59.747 31.824 62.051 ;
     RECT  5.412 59.749 6.72 60.467 ;
     RECT  6.744 59.749 7.8 60.467 ;
     RECT  16.212 59.891 17.472 60.995 ;
     RECT  13.512 60.275 14.832 60.467 ;
     RECT  13.512 60.467 15.9 61.573 ;
     RECT  16.212 60.995 17.616 63.733 ;
     RECT  8.808 61.523 10.272 62.915 ;
     RECT  13.512 61.573 14.784 62.675 ;
     RECT  14.808 61.573 15.9 62.675 ;
     RECT  27.012 61.619 27.576 62.581 ;
     RECT  10.812 62.005 12.048 63.059 ;
     RECT  29.712 62.051 31.824 62.675 ;
     RECT  18.912 62.437 20.256 63.779 ;
     RECT  20.28 62.437 21.3 62.533 ;
     RECT  27.012 62.581 28.848 62.965 ;
     RECT  13.512 62.675 15.9 63.109 ;
     RECT  29.712 62.675 31.92 62.867 ;
     RECT  37.812 62.677 38.832 63.685 ;
     RECT  38.856 62.677 40.2 65.363 ;
     RECT  29.712 62.867 31.968 63.541 ;
     RECT  8.808 62.915 10.5 62.965 ;
     RECT  9.096 62.965 10.5 64.211 ;
     RECT  10.812 63.059 12.912 63.061 ;
     RECT  11.592 63.061 12.912 63.779 ;
     RECT  13.512 63.109 15.12 63.781 ;
     RECT  29.712 63.541 30.72 64.547 ;
     RECT  30.744 63.541 31.968 64.547 ;
     RECT  16.212 63.733 17.424 64.931 ;
     RECT  12.624 63.779 12.912 64.309 ;
     RECT  13.512 63.781 14.832 72.995 ;
     RECT  17.448 63.827 18.6 64.885 ;
     RECT  27.012 63.875 28.848 64.163 ;
     RECT  14.856 64.019 15.9 72.995 ;
     RECT  34.08 64.067 34.272 64.741 ;
     RECT  37.812 64.115 38.832 65.363 ;
     RECT  27.012 64.163 27.336 65.317 ;
     RECT  29.28 64.163 29.4 65.413 ;
     RECT  32.904 64.741 34.272 65.603 ;
     RECT  5.412 64.835 5.784 65.845 ;
     RECT  16.212 64.931 17.616 65.603 ;
     RECT  16.212 65.603 18.24 66.757 ;
     RECT  22.2 65.653 23.376 66.227 ;
     RECT  5.412 65.845 6.912 66.613 ;
     RECT  24.312 65.939 25.488 67.141 ;
     RECT  22.2 66.227 24 67.669 ;
     RECT  34.272 66.227 34.8 67.141 ;
     RECT  5.412 66.613 6.768 69.731 ;
     RECT  6.792 66.659 7.8 69.731 ;
     RECT  16.872 66.757 18.24 66.803 ;
     RECT  24.504 67.141 25.488 68.149 ;
     RECT  32.412 67.141 33.792 68.965 ;
     RECT  33.816 67.141 34.8 67.765 ;
     RECT  22.968 67.669 24 69.011 ;
     RECT  8.112 67.765 9.312 70.019 ;
     RECT  9.336 67.765 10.5 70.019 ;
     RECT  21.72 68.387 22.944 69.011 ;
     RECT  25.512 68.435 26.592 68.915 ;
     RECT  25.512 68.915 26.7 72.853 ;
     RECT  35.112 68.917 36.432 70.069 ;
     RECT  36.456 68.917 37.5 70.115 ;
     RECT  32.412 68.965 33.408 70.499 ;
     RECT  33.816 69.059 34.8 69.875 ;
     RECT  19.176 69.541 20.592 69.875 ;
     RECT  29.88 69.875 30.216 70.405 ;
     RECT  33.672 69.875 34.8 71.363 ;
     RECT  37.812 70.165 38.88 72.995 ;
     RECT  38.904 70.165 40.2 72.995 ;
     RECT  29.88 70.405 31.008 70.451 ;
     RECT  29.712 70.451 31.008 73.717 ;
     RECT  32.412 70.499 33.504 71.315 ;
     RECT  31.032 70.643 32.1 73.763 ;
     RECT  32.412 71.315 33.648 71.363 ;
     RECT  24.312 72.947 25.68 74.627 ;
     RECT  25.704 73.427 26.7 74.627 ;
  END
END dsfd_node_LLd
END LIBRARY
